VERSION 5.8 ;
BUSBITCHARS "[]" ;
DIVIDERCHAR "/" ;
UNITS
    DATABASE MICRONS 1000 ;
END UNITS

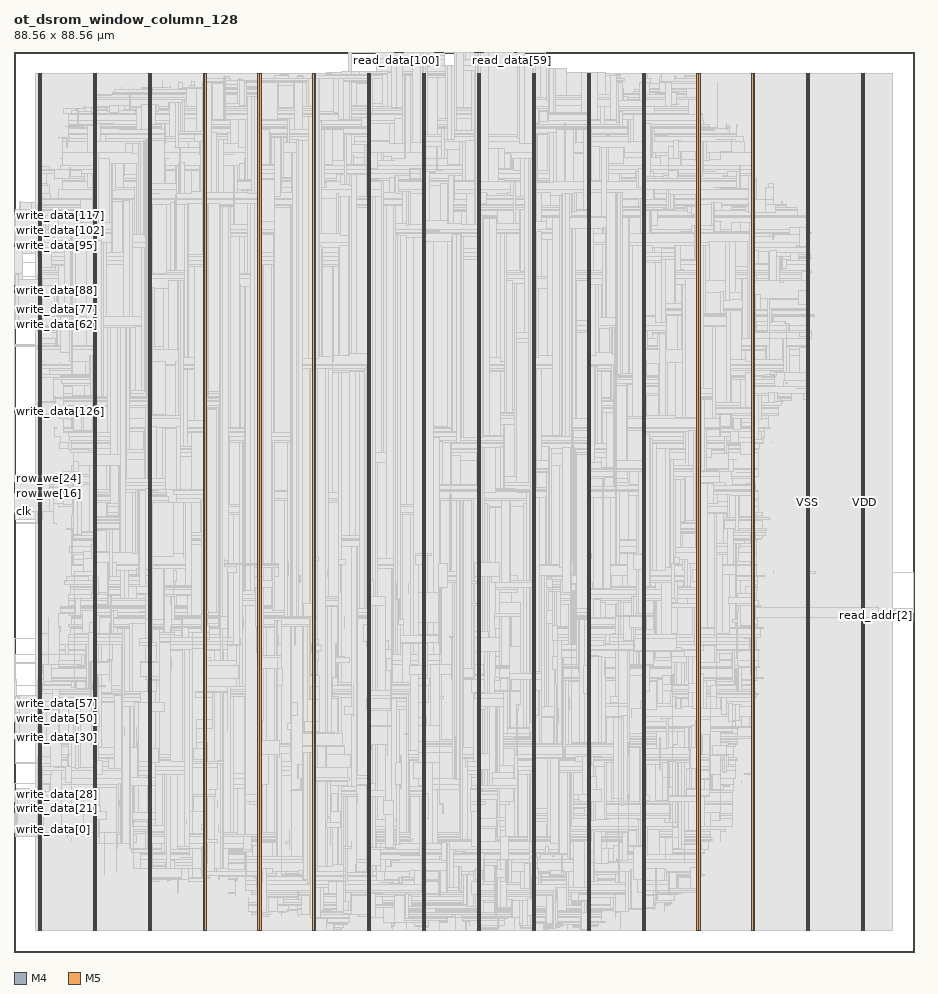
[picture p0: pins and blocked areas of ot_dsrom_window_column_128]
MACRO ot_dsrom_window_column_128
  FOREIGN ot_dsrom_window_column_128 0 0 ;
  CLASS BLOCK ;
  SIZE 88.56 BY 88.56 ;
  PIN clk
    DIRECTION INPUT ;
    USE SIGNAL ;
    PORT
      LAYER M4 ;
        RECT  0 43.344 0.084 43.368 ;
    END
  END clk
  PIN read_addr[0]
    DIRECTION INPUT ;
    USE SIGNAL ;
    PORT
      LAYER M4 ;
        RECT  88.476 32.88 88.56 32.904 ;
    END
  END read_addr[0]
  PIN read_addr[1]
    DIRECTION INPUT ;
    USE SIGNAL ;
    PORT
      LAYER M4 ;
        RECT  88.476 32.976 88.56 33 ;
    END
  END read_addr[1]
  PIN read_addr[2]
    DIRECTION INPUT ;
    USE SIGNAL ;
    PORT
      LAYER M4 ;
        RECT  88.476 33.072 88.56 33.096 ;
    END
  END read_addr[2]
  PIN read_addr[3]
    DIRECTION INPUT ;
    USE SIGNAL ;
    PORT
      LAYER M4 ;
        RECT  88.476 33.168 88.56 33.192 ;
    END
  END read_addr[3]
  PIN read_addr[4]
    DIRECTION INPUT ;
    USE SIGNAL ;
    PORT
      LAYER M4 ;
        RECT  88.476 33.264 88.56 33.288 ;
    END
  END read_addr[4]
  PIN read_data[0]
    DIRECTION OUTPUT ;
    USE SIGNAL ;
    PORT
      LAYER M5 ;
        RECT  43.344 88.476 43.368 88.56 ;
    END
  END read_data[0]
  PIN read_data[100]
    DIRECTION OUTPUT ;
    USE SIGNAL ;
    PORT
      LAYER M5 ;
        RECT  37.584 88.476 37.608 88.56 ;
    END
  END read_data[100]
  PIN read_data[101]
    DIRECTION OUTPUT ;
    USE SIGNAL ;
    PORT
      LAYER M5 ;
        RECT  37.68 88.476 37.704 88.56 ;
    END
  END read_data[101]
  PIN read_data[102]
    DIRECTION OUTPUT ;
    USE SIGNAL ;
    PORT
      LAYER M5 ;
        RECT  37.776 88.476 37.8 88.56 ;
    END
  END read_data[102]
  PIN read_data[103]
    DIRECTION OUTPUT ;
    USE SIGNAL ;
    PORT
      LAYER M5 ;
        RECT  37.872 88.476 37.896 88.56 ;
    END
  END read_data[103]
  PIN read_data[104]
    DIRECTION OUTPUT ;
    USE SIGNAL ;
    PORT
      LAYER M5 ;
        RECT  37.968 88.476 37.992 88.56 ;
    END
  END read_data[104]
  PIN read_data[105]
    DIRECTION OUTPUT ;
    USE SIGNAL ;
    PORT
      LAYER M5 ;
        RECT  38.064 88.476 38.088 88.56 ;
    END
  END read_data[105]
  PIN read_data[106]
    DIRECTION OUTPUT ;
    USE SIGNAL ;
    PORT
      LAYER M5 ;
        RECT  38.16 88.476 38.184 88.56 ;
    END
  END read_data[106]
  PIN read_data[107]
    DIRECTION OUTPUT ;
    USE SIGNAL ;
    PORT
      LAYER M5 ;
        RECT  38.256 88.476 38.28 88.56 ;
    END
  END read_data[107]
  PIN read_data[108]
    DIRECTION OUTPUT ;
    USE SIGNAL ;
    PORT
      LAYER M5 ;
        RECT  38.352 88.476 38.376 88.56 ;
    END
  END read_data[108]
  PIN read_data[109]
    DIRECTION OUTPUT ;
    USE SIGNAL ;
    PORT
      LAYER M5 ;
        RECT  38.448 88.476 38.472 88.56 ;
    END
  END read_data[109]
  PIN read_data[10]
    DIRECTION OUTPUT ;
    USE SIGNAL ;
    PORT
      LAYER M5 ;
        RECT  44.304 88.476 44.328 88.56 ;
    END
  END read_data[10]
  PIN read_data[110]
    DIRECTION OUTPUT ;
    USE SIGNAL ;
    PORT
      LAYER M5 ;
        RECT  38.544 88.476 38.568 88.56 ;
    END
  END read_data[110]
  PIN read_data[111]
    DIRECTION OUTPUT ;
    USE SIGNAL ;
    PORT
      LAYER M5 ;
        RECT  38.64 88.476 38.664 88.56 ;
    END
  END read_data[111]
  PIN read_data[112]
    DIRECTION OUTPUT ;
    USE SIGNAL ;
    PORT
      LAYER M5 ;
        RECT  38.736 88.476 38.76 88.56 ;
    END
  END read_data[112]
  PIN read_data[113]
    DIRECTION OUTPUT ;
    USE SIGNAL ;
    PORT
      LAYER M5 ;
        RECT  38.832 88.476 38.856 88.56 ;
    END
  END read_data[113]
  PIN read_data[114]
    DIRECTION OUTPUT ;
    USE SIGNAL ;
    PORT
      LAYER M5 ;
        RECT  38.928 88.476 38.952 88.56 ;
    END
  END read_data[114]
  PIN read_data[115]
    DIRECTION OUTPUT ;
    USE SIGNAL ;
    PORT
      LAYER M5 ;
        RECT  39.024 88.476 39.048 88.56 ;
    END
  END read_data[115]
  PIN read_data[116]
    DIRECTION OUTPUT ;
    USE SIGNAL ;
    PORT
      LAYER M5 ;
        RECT  39.12 88.476 39.144 88.56 ;
    END
  END read_data[116]
  PIN read_data[117]
    DIRECTION OUTPUT ;
    USE SIGNAL ;
    PORT
      LAYER M5 ;
        RECT  39.216 88.476 39.24 88.56 ;
    END
  END read_data[117]
  PIN read_data[118]
    DIRECTION OUTPUT ;
    USE SIGNAL ;
    PORT
      LAYER M5 ;
        RECT  39.312 88.476 39.336 88.56 ;
    END
  END read_data[118]
  PIN read_data[119]
    DIRECTION OUTPUT ;
    USE SIGNAL ;
    PORT
      LAYER M5 ;
        RECT  39.408 88.476 39.432 88.56 ;
    END
  END read_data[119]
  PIN read_data[11]
    DIRECTION OUTPUT ;
    USE SIGNAL ;
    PORT
      LAYER M5 ;
        RECT  44.4 88.476 44.424 88.56 ;
    END
  END read_data[11]
  PIN read_data[120]
    DIRECTION OUTPUT ;
    USE SIGNAL ;
    PORT
      LAYER M5 ;
        RECT  39.504 88.476 39.528 88.56 ;
    END
  END read_data[120]
  PIN read_data[121]
    DIRECTION OUTPUT ;
    USE SIGNAL ;
    PORT
      LAYER M5 ;
        RECT  39.6 88.476 39.624 88.56 ;
    END
  END read_data[121]
  PIN read_data[122]
    DIRECTION OUTPUT ;
    USE SIGNAL ;
    PORT
      LAYER M5 ;
        RECT  39.696 88.476 39.72 88.56 ;
    END
  END read_data[122]
  PIN read_data[123]
    DIRECTION OUTPUT ;
    USE SIGNAL ;
    PORT
      LAYER M5 ;
        RECT  39.792 88.476 39.816 88.56 ;
    END
  END read_data[123]
  PIN read_data[124]
    DIRECTION OUTPUT ;
    USE SIGNAL ;
    PORT
      LAYER M5 ;
        RECT  39.888 88.476 39.912 88.56 ;
    END
  END read_data[124]
  PIN read_data[125]
    DIRECTION OUTPUT ;
    USE SIGNAL ;
    PORT
      LAYER M5 ;
        RECT  39.984 88.476 40.008 88.56 ;
    END
  END read_data[125]
  PIN read_data[126]
    DIRECTION OUTPUT ;
    USE SIGNAL ;
    PORT
      LAYER M5 ;
        RECT  40.08 88.476 40.104 88.56 ;
    END
  END read_data[126]
  PIN read_data[127]
    DIRECTION OUTPUT ;
    USE SIGNAL ;
    PORT
      LAYER M5 ;
        RECT  40.176 88.476 40.2 88.56 ;
    END
  END read_data[127]
  PIN read_data[12]
    DIRECTION OUTPUT ;
    USE SIGNAL ;
    PORT
      LAYER M5 ;
        RECT  44.496 88.476 44.52 88.56 ;
    END
  END read_data[12]
  PIN read_data[13]
    DIRECTION OUTPUT ;
    USE SIGNAL ;
    PORT
      LAYER M5 ;
        RECT  44.592 88.476 44.616 88.56 ;
    END
  END read_data[13]
  PIN read_data[14]
    DIRECTION OUTPUT ;
    USE SIGNAL ;
    PORT
      LAYER M5 ;
        RECT  44.688 88.476 44.712 88.56 ;
    END
  END read_data[14]
  PIN read_data[15]
    DIRECTION OUTPUT ;
    USE SIGNAL ;
    PORT
      LAYER M5 ;
        RECT  44.784 88.476 44.808 88.56 ;
    END
  END read_data[15]
  PIN read_data[16]
    DIRECTION OUTPUT ;
    USE SIGNAL ;
    PORT
      LAYER M5 ;
        RECT  44.88 88.476 44.904 88.56 ;
    END
  END read_data[16]
  PIN read_data[17]
    DIRECTION OUTPUT ;
    USE SIGNAL ;
    PORT
      LAYER M5 ;
        RECT  44.976 88.476 45 88.56 ;
    END
  END read_data[17]
  PIN read_data[18]
    DIRECTION OUTPUT ;
    USE SIGNAL ;
    PORT
      LAYER M5 ;
        RECT  45.072 88.476 45.096 88.56 ;
    END
  END read_data[18]
  PIN read_data[19]
    DIRECTION OUTPUT ;
    USE SIGNAL ;
    PORT
      LAYER M5 ;
        RECT  45.168 88.476 45.192 88.56 ;
    END
  END read_data[19]
  PIN read_data[1]
    DIRECTION OUTPUT ;
    USE SIGNAL ;
    PORT
      LAYER M5 ;
        RECT  43.44 88.476 43.464 88.56 ;
    END
  END read_data[1]
  PIN read_data[20]
    DIRECTION OUTPUT ;
    USE SIGNAL ;
    PORT
      LAYER M5 ;
        RECT  45.264 88.476 45.288 88.56 ;
    END
  END read_data[20]
  PIN read_data[21]
    DIRECTION OUTPUT ;
    USE SIGNAL ;
    PORT
      LAYER M5 ;
        RECT  45.36 88.476 45.384 88.56 ;
    END
  END read_data[21]
  PIN read_data[22]
    DIRECTION OUTPUT ;
    USE SIGNAL ;
    PORT
      LAYER M5 ;
        RECT  45.456 88.476 45.48 88.56 ;
    END
  END read_data[22]
  PIN read_data[23]
    DIRECTION OUTPUT ;
    USE SIGNAL ;
    PORT
      LAYER M5 ;
        RECT  45.552 88.476 45.576 88.56 ;
    END
  END read_data[23]
  PIN read_data[24]
    DIRECTION OUTPUT ;
    USE SIGNAL ;
    PORT
      LAYER M5 ;
        RECT  45.648 88.476 45.672 88.56 ;
    END
  END read_data[24]
  PIN read_data[25]
    DIRECTION OUTPUT ;
    USE SIGNAL ;
    PORT
      LAYER M5 ;
        RECT  45.744 88.476 45.768 88.56 ;
    END
  END read_data[25]
  PIN read_data[26]
    DIRECTION OUTPUT ;
    USE SIGNAL ;
    PORT
      LAYER M5 ;
        RECT  45.84 88.476 45.864 88.56 ;
    END
  END read_data[26]
  PIN read_data[27]
    DIRECTION OUTPUT ;
    USE SIGNAL ;
    PORT
      LAYER M5 ;
        RECT  45.936 88.476 45.96 88.56 ;
    END
  END read_data[27]
  PIN read_data[28]
    DIRECTION OUTPUT ;
    USE SIGNAL ;
    PORT
      LAYER M5 ;
        RECT  46.032 88.476 46.056 88.56 ;
    END
  END read_data[28]
  PIN read_data[29]
    DIRECTION OUTPUT ;
    USE SIGNAL ;
    PORT
      LAYER M5 ;
        RECT  46.128 88.476 46.152 88.56 ;
    END
  END read_data[29]
  PIN read_data[2]
    DIRECTION OUTPUT ;
    USE SIGNAL ;
    PORT
      LAYER M5 ;
        RECT  43.536 88.476 43.56 88.56 ;
    END
  END read_data[2]
  PIN read_data[30]
    DIRECTION OUTPUT ;
    USE SIGNAL ;
    PORT
      LAYER M5 ;
        RECT  46.224 88.476 46.248 88.56 ;
    END
  END read_data[30]
  PIN read_data[31]
    DIRECTION OUTPUT ;
    USE SIGNAL ;
    PORT
      LAYER M5 ;
        RECT  46.32 88.476 46.344 88.56 ;
    END
  END read_data[31]
  PIN read_data[32]
    DIRECTION OUTPUT ;
    USE SIGNAL ;
    PORT
      LAYER M5 ;
        RECT  46.416 88.476 46.44 88.56 ;
    END
  END read_data[32]
  PIN read_data[33]
    DIRECTION OUTPUT ;
    USE SIGNAL ;
    PORT
      LAYER M5 ;
        RECT  46.512 88.476 46.536 88.56 ;
    END
  END read_data[33]
  PIN read_data[34]
    DIRECTION OUTPUT ;
    USE SIGNAL ;
    PORT
      LAYER M5 ;
        RECT  46.608 88.476 46.632 88.56 ;
    END
  END read_data[34]
  PIN read_data[35]
    DIRECTION OUTPUT ;
    USE SIGNAL ;
    PORT
      LAYER M5 ;
        RECT  46.704 88.476 46.728 88.56 ;
    END
  END read_data[35]
  PIN read_data[36]
    DIRECTION OUTPUT ;
    USE SIGNAL ;
    PORT
      LAYER M5 ;
        RECT  46.8 88.476 46.824 88.56 ;
    END
  END read_data[36]
  PIN read_data[37]
    DIRECTION OUTPUT ;
    USE SIGNAL ;
    PORT
      LAYER M5 ;
        RECT  46.896 88.476 46.92 88.56 ;
    END
  END read_data[37]
  PIN read_data[38]
    DIRECTION OUTPUT ;
    USE SIGNAL ;
    PORT
      LAYER M5 ;
        RECT  46.992 88.476 47.016 88.56 ;
    END
  END read_data[38]
  PIN read_data[39]
    DIRECTION OUTPUT ;
    USE SIGNAL ;
    PORT
      LAYER M5 ;
        RECT  47.088 88.476 47.112 88.56 ;
    END
  END read_data[39]
  PIN read_data[3]
    DIRECTION OUTPUT ;
    USE SIGNAL ;
    PORT
      LAYER M5 ;
        RECT  43.632 88.476 43.656 88.56 ;
    END
  END read_data[3]
  PIN read_data[40]
    DIRECTION OUTPUT ;
    USE SIGNAL ;
    PORT
      LAYER M5 ;
        RECT  47.184 88.476 47.208 88.56 ;
    END
  END read_data[40]
  PIN read_data[41]
    DIRECTION OUTPUT ;
    USE SIGNAL ;
    PORT
      LAYER M5 ;
        RECT  47.28 88.476 47.304 88.56 ;
    END
  END read_data[41]
  PIN read_data[42]
    DIRECTION OUTPUT ;
    USE SIGNAL ;
    PORT
      LAYER M5 ;
        RECT  47.376 88.476 47.4 88.56 ;
    END
  END read_data[42]
  PIN read_data[43]
    DIRECTION OUTPUT ;
    USE SIGNAL ;
    PORT
      LAYER M5 ;
        RECT  47.472 88.476 47.496 88.56 ;
    END
  END read_data[43]
  PIN read_data[44]
    DIRECTION OUTPUT ;
    USE SIGNAL ;
    PORT
      LAYER M5 ;
        RECT  47.568 88.476 47.592 88.56 ;
    END
  END read_data[44]
  PIN read_data[45]
    DIRECTION OUTPUT ;
    USE SIGNAL ;
    PORT
      LAYER M5 ;
        RECT  47.664 88.476 47.688 88.56 ;
    END
  END read_data[45]
  PIN read_data[46]
    DIRECTION OUTPUT ;
    USE SIGNAL ;
    PORT
      LAYER M5 ;
        RECT  47.76 88.476 47.784 88.56 ;
    END
  END read_data[46]
  PIN read_data[47]
    DIRECTION OUTPUT ;
    USE SIGNAL ;
    PORT
      LAYER M5 ;
        RECT  47.856 88.476 47.88 88.56 ;
    END
  END read_data[47]
  PIN read_data[48]
    DIRECTION OUTPUT ;
    USE SIGNAL ;
    PORT
      LAYER M5 ;
        RECT  47.952 88.476 47.976 88.56 ;
    END
  END read_data[48]
  PIN read_data[49]
    DIRECTION OUTPUT ;
    USE SIGNAL ;
    PORT
      LAYER M5 ;
        RECT  48.048 88.476 48.072 88.56 ;
    END
  END read_data[49]
  PIN read_data[4]
    DIRECTION OUTPUT ;
    USE SIGNAL ;
    PORT
      LAYER M5 ;
        RECT  43.728 88.476 43.752 88.56 ;
    END
  END read_data[4]
  PIN read_data[50]
    DIRECTION OUTPUT ;
    USE SIGNAL ;
    PORT
      LAYER M5 ;
        RECT  48.144 88.476 48.168 88.56 ;
    END
  END read_data[50]
  PIN read_data[51]
    DIRECTION OUTPUT ;
    USE SIGNAL ;
    PORT
      LAYER M5 ;
        RECT  48.24 88.476 48.264 88.56 ;
    END
  END read_data[51]
  PIN read_data[52]
    DIRECTION OUTPUT ;
    USE SIGNAL ;
    PORT
      LAYER M5 ;
        RECT  48.336 88.476 48.36 88.56 ;
    END
  END read_data[52]
  PIN read_data[53]
    DIRECTION OUTPUT ;
    USE SIGNAL ;
    PORT
      LAYER M5 ;
        RECT  48.432 88.476 48.456 88.56 ;
    END
  END read_data[53]
  PIN read_data[54]
    DIRECTION OUTPUT ;
    USE SIGNAL ;
    PORT
      LAYER M5 ;
        RECT  48.528 88.476 48.552 88.56 ;
    END
  END read_data[54]
  PIN read_data[55]
    DIRECTION OUTPUT ;
    USE SIGNAL ;
    PORT
      LAYER M5 ;
        RECT  48.624 88.476 48.648 88.56 ;
    END
  END read_data[55]
  PIN read_data[56]
    DIRECTION OUTPUT ;
    USE SIGNAL ;
    PORT
      LAYER M5 ;
        RECT  48.72 88.476 48.744 88.56 ;
    END
  END read_data[56]
  PIN read_data[57]
    DIRECTION OUTPUT ;
    USE SIGNAL ;
    PORT
      LAYER M5 ;
        RECT  48.816 88.476 48.84 88.56 ;
    END
  END read_data[57]
  PIN read_data[58]
    DIRECTION OUTPUT ;
    USE SIGNAL ;
    PORT
      LAYER M5 ;
        RECT  48.912 88.476 48.936 88.56 ;
    END
  END read_data[58]
  PIN read_data[59]
    DIRECTION OUTPUT ;
    USE SIGNAL ;
    PORT
      LAYER M5 ;
        RECT  49.008 88.476 49.032 88.56 ;
    END
  END read_data[59]
  PIN read_data[5]
    DIRECTION OUTPUT ;
    USE SIGNAL ;
    PORT
      LAYER M5 ;
        RECT  43.824 88.476 43.848 88.56 ;
    END
  END read_data[5]
  PIN read_data[60]
    DIRECTION OUTPUT ;
    USE SIGNAL ;
    PORT
      LAYER M5 ;
        RECT  49.104 88.476 49.128 88.56 ;
    END
  END read_data[60]
  PIN read_data[61]
    DIRECTION OUTPUT ;
    USE SIGNAL ;
    PORT
      LAYER M5 ;
        RECT  49.2 88.476 49.224 88.56 ;
    END
  END read_data[61]
  PIN read_data[62]
    DIRECTION OUTPUT ;
    USE SIGNAL ;
    PORT
      LAYER M5 ;
        RECT  49.296 88.476 49.32 88.56 ;
    END
  END read_data[62]
  PIN read_data[63]
    DIRECTION OUTPUT ;
    USE SIGNAL ;
    PORT
      LAYER M5 ;
        RECT  49.392 88.476 49.416 88.56 ;
    END
  END read_data[63]
  PIN read_data[64]
    DIRECTION OUTPUT ;
    USE SIGNAL ;
    PORT
      LAYER M5 ;
        RECT  40.272 88.476 40.296 88.56 ;
    END
  END read_data[64]
  PIN read_data[65]
    DIRECTION OUTPUT ;
    USE SIGNAL ;
    PORT
      LAYER M5 ;
        RECT  40.368 88.476 40.392 88.56 ;
    END
  END read_data[65]
  PIN read_data[66]
    DIRECTION OUTPUT ;
    USE SIGNAL ;
    PORT
      LAYER M5 ;
        RECT  40.464 88.476 40.488 88.56 ;
    END
  END read_data[66]
  PIN read_data[67]
    DIRECTION OUTPUT ;
    USE SIGNAL ;
    PORT
      LAYER M5 ;
        RECT  40.56 88.476 40.584 88.56 ;
    END
  END read_data[67]
  PIN read_data[68]
    DIRECTION OUTPUT ;
    USE SIGNAL ;
    PORT
      LAYER M5 ;
        RECT  40.656 88.476 40.68 88.56 ;
    END
  END read_data[68]
  PIN read_data[69]
    DIRECTION OUTPUT ;
    USE SIGNAL ;
    PORT
      LAYER M5 ;
        RECT  40.752 88.476 40.776 88.56 ;
    END
  END read_data[69]
  PIN read_data[6]
    DIRECTION OUTPUT ;
    USE SIGNAL ;
    PORT
      LAYER M5 ;
        RECT  43.92 88.476 43.944 88.56 ;
    END
  END read_data[6]
  PIN read_data[70]
    DIRECTION OUTPUT ;
    USE SIGNAL ;
    PORT
      LAYER M5 ;
        RECT  40.848 88.476 40.872 88.56 ;
    END
  END read_data[70]
  PIN read_data[71]
    DIRECTION OUTPUT ;
    USE SIGNAL ;
    PORT
      LAYER M5 ;
        RECT  40.944 88.476 40.968 88.56 ;
    END
  END read_data[71]
  PIN read_data[72]
    DIRECTION OUTPUT ;
    USE SIGNAL ;
    PORT
      LAYER M5 ;
        RECT  41.04 88.476 41.064 88.56 ;
    END
  END read_data[72]
  PIN read_data[73]
    DIRECTION OUTPUT ;
    USE SIGNAL ;
    PORT
      LAYER M5 ;
        RECT  41.136 88.476 41.16 88.56 ;
    END
  END read_data[73]
  PIN read_data[74]
    DIRECTION OUTPUT ;
    USE SIGNAL ;
    PORT
      LAYER M5 ;
        RECT  41.232 88.476 41.256 88.56 ;
    END
  END read_data[74]
  PIN read_data[75]
    DIRECTION OUTPUT ;
    USE SIGNAL ;
    PORT
      LAYER M5 ;
        RECT  41.328 88.476 41.352 88.56 ;
    END
  END read_data[75]
  PIN read_data[76]
    DIRECTION OUTPUT ;
    USE SIGNAL ;
    PORT
      LAYER M5 ;
        RECT  41.424 88.476 41.448 88.56 ;
    END
  END read_data[76]
  PIN read_data[77]
    DIRECTION OUTPUT ;
    USE SIGNAL ;
    PORT
      LAYER M5 ;
        RECT  41.52 88.476 41.544 88.56 ;
    END
  END read_data[77]
  PIN read_data[78]
    DIRECTION OUTPUT ;
    USE SIGNAL ;
    PORT
      LAYER M5 ;
        RECT  41.616 88.476 41.64 88.56 ;
    END
  END read_data[78]
  PIN read_data[79]
    DIRECTION OUTPUT ;
    USE SIGNAL ;
    PORT
      LAYER M5 ;
        RECT  41.712 88.476 41.736 88.56 ;
    END
  END read_data[79]
  PIN read_data[7]
    DIRECTION OUTPUT ;
    USE SIGNAL ;
    PORT
      LAYER M5 ;
        RECT  44.016 88.476 44.04 88.56 ;
    END
  END read_data[7]
  PIN read_data[80]
    DIRECTION OUTPUT ;
    USE SIGNAL ;
    PORT
      LAYER M5 ;
        RECT  41.808 88.476 41.832 88.56 ;
    END
  END read_data[80]
  PIN read_data[81]
    DIRECTION OUTPUT ;
    USE SIGNAL ;
    PORT
      LAYER M5 ;
        RECT  41.904 88.476 41.928 88.56 ;
    END
  END read_data[81]
  PIN read_data[82]
    DIRECTION OUTPUT ;
    USE SIGNAL ;
    PORT
      LAYER M5 ;
        RECT  42 88.476 42.024 88.56 ;
    END
  END read_data[82]
  PIN read_data[83]
    DIRECTION OUTPUT ;
    USE SIGNAL ;
    PORT
      LAYER M5 ;
        RECT  42.096 88.476 42.12 88.56 ;
    END
  END read_data[83]
  PIN read_data[84]
    DIRECTION OUTPUT ;
    USE SIGNAL ;
    PORT
      LAYER M5 ;
        RECT  42.192 88.476 42.216 88.56 ;
    END
  END read_data[84]
  PIN read_data[85]
    DIRECTION OUTPUT ;
    USE SIGNAL ;
    PORT
      LAYER M5 ;
        RECT  42.288 88.476 42.312 88.56 ;
    END
  END read_data[85]
  PIN read_data[86]
    DIRECTION OUTPUT ;
    USE SIGNAL ;
    PORT
      LAYER M5 ;
        RECT  42.384 88.476 42.408 88.56 ;
    END
  END read_data[86]
  PIN read_data[87]
    DIRECTION OUTPUT ;
    USE SIGNAL ;
    PORT
      LAYER M5 ;
        RECT  42.48 88.476 42.504 88.56 ;
    END
  END read_data[87]
  PIN read_data[88]
    DIRECTION OUTPUT ;
    USE SIGNAL ;
    PORT
      LAYER M5 ;
        RECT  42.576 88.476 42.6 88.56 ;
    END
  END read_data[88]
  PIN read_data[89]
    DIRECTION OUTPUT ;
    USE SIGNAL ;
    PORT
      LAYER M5 ;
        RECT  42.672 88.476 42.696 88.56 ;
    END
  END read_data[89]
  PIN read_data[8]
    DIRECTION OUTPUT ;
    USE SIGNAL ;
    PORT
      LAYER M5 ;
        RECT  44.112 88.476 44.136 88.56 ;
    END
  END read_data[8]
  PIN read_data[90]
    DIRECTION OUTPUT ;
    USE SIGNAL ;
    PORT
      LAYER M5 ;
        RECT  42.768 88.476 42.792 88.56 ;
    END
  END read_data[90]
  PIN read_data[91]
    DIRECTION OUTPUT ;
    USE SIGNAL ;
    PORT
      LAYER M5 ;
        RECT  42.864 88.476 42.888 88.56 ;
    END
  END read_data[91]
  PIN read_data[92]
    DIRECTION OUTPUT ;
    USE SIGNAL ;
    PORT
      LAYER M5 ;
        RECT  42.96 88.476 42.984 88.56 ;
    END
  END read_data[92]
  PIN read_data[93]
    DIRECTION OUTPUT ;
    USE SIGNAL ;
    PORT
      LAYER M5 ;
        RECT  43.056 88.476 43.08 88.56 ;
    END
  END read_data[93]
  PIN read_data[94]
    DIRECTION OUTPUT ;
    USE SIGNAL ;
    PORT
      LAYER M5 ;
        RECT  43.152 88.476 43.176 88.56 ;
    END
  END read_data[94]
  PIN read_data[95]
    DIRECTION OUTPUT ;
    USE SIGNAL ;
    PORT
      LAYER M5 ;
        RECT  43.248 88.476 43.272 88.56 ;
    END
  END read_data[95]
  PIN read_data[96]
    DIRECTION OUTPUT ;
    USE SIGNAL ;
    PORT
      LAYER M5 ;
        RECT  37.2 88.476 37.224 88.56 ;
    END
  END read_data[96]
  PIN read_data[97]
    DIRECTION OUTPUT ;
    USE SIGNAL ;
    PORT
      LAYER M5 ;
        RECT  37.296 88.476 37.32 88.56 ;
    END
  END read_data[97]
  PIN read_data[98]
    DIRECTION OUTPUT ;
    USE SIGNAL ;
    PORT
      LAYER M5 ;
        RECT  37.392 88.476 37.416 88.56 ;
    END
  END read_data[98]
  PIN read_data[99]
    DIRECTION OUTPUT ;
    USE SIGNAL ;
    PORT
      LAYER M5 ;
        RECT  37.488 88.476 37.512 88.56 ;
    END
  END read_data[99]
  PIN read_data[9]
    DIRECTION OUTPUT ;
    USE SIGNAL ;
    PORT
      LAYER M5 ;
        RECT  44.208 88.476 44.232 88.56 ;
    END
  END read_data[9]
  PIN read_v
    DIRECTION INPUT ;
    USE SIGNAL ;
    PORT
      LAYER M4 ;
        RECT  0 43.44 0.084 43.464 ;
    END
  END read_v
  PIN row_we[0]
    DIRECTION INPUT ;
    USE SIGNAL ;
    PORT
      LAYER M4 ;
        RECT  0 43.536 0.084 43.56 ;
    END
  END row_we[0]
  PIN row_we[10]
    DIRECTION INPUT ;
    USE SIGNAL ;
    PORT
      LAYER M4 ;
        RECT  0 44.496 0.084 44.52 ;
    END
  END row_we[10]
  PIN row_we[11]
    DIRECTION INPUT ;
    USE SIGNAL ;
    PORT
      LAYER M4 ;
        RECT  0 44.592 0.084 44.616 ;
    END
  END row_we[11]
  PIN row_we[12]
    DIRECTION INPUT ;
    USE SIGNAL ;
    PORT
      LAYER M4 ;
        RECT  0 44.688 0.084 44.712 ;
    END
  END row_we[12]
  PIN row_we[13]
    DIRECTION INPUT ;
    USE SIGNAL ;
    PORT
      LAYER M4 ;
        RECT  0 44.784 0.084 44.808 ;
    END
  END row_we[13]
  PIN row_we[14]
    DIRECTION INPUT ;
    USE SIGNAL ;
    PORT
      LAYER M4 ;
        RECT  0 44.88 0.084 44.904 ;
    END
  END row_we[14]
  PIN row_we[15]
    DIRECTION INPUT ;
    USE SIGNAL ;
    PORT
      LAYER M4 ;
        RECT  0 44.976 0.084 45 ;
    END
  END row_we[15]
  PIN row_we[16]
    DIRECTION INPUT ;
    USE SIGNAL ;
    PORT
      LAYER M4 ;
        RECT  0 45.072 0.084 45.096 ;
    END
  END row_we[16]
  PIN row_we[17]
    DIRECTION INPUT ;
    USE SIGNAL ;
    PORT
      LAYER M4 ;
        RECT  0 45.168 0.084 45.192 ;
    END
  END row_we[17]
  PIN row_we[18]
    DIRECTION INPUT ;
    USE SIGNAL ;
    PORT
      LAYER M4 ;
        RECT  0 45.264 0.084 45.288 ;
    END
  END row_we[18]
  PIN row_we[19]
    DIRECTION INPUT ;
    USE SIGNAL ;
    PORT
      LAYER M4 ;
        RECT  0 45.36 0.084 45.384 ;
    END
  END row_we[19]
  PIN row_we[1]
    DIRECTION INPUT ;
    USE SIGNAL ;
    PORT
      LAYER M4 ;
        RECT  0 43.632 0.084 43.656 ;
    END
  END row_we[1]
  PIN row_we[20]
    DIRECTION INPUT ;
    USE SIGNAL ;
    PORT
      LAYER M4 ;
        RECT  0 45.456 0.084 45.48 ;
    END
  END row_we[20]
  PIN row_we[21]
    DIRECTION INPUT ;
    USE SIGNAL ;
    PORT
      LAYER M4 ;
        RECT  0 45.552 0.084 45.576 ;
    END
  END row_we[21]
  PIN row_we[22]
    DIRECTION INPUT ;
    USE SIGNAL ;
    PORT
      LAYER M4 ;
        RECT  0 45.648 0.084 45.672 ;
    END
  END row_we[22]
  PIN row_we[23]
    DIRECTION INPUT ;
    USE SIGNAL ;
    PORT
      LAYER M4 ;
        RECT  0 45.744 0.084 45.768 ;
    END
  END row_we[23]
  PIN row_we[24]
    DIRECTION INPUT ;
    USE SIGNAL ;
    PORT
      LAYER M4 ;
        RECT  0 45.84 0.084 45.864 ;
    END
  END row_we[24]
  PIN row_we[25]
    DIRECTION INPUT ;
    USE SIGNAL ;
    PORT
      LAYER M4 ;
        RECT  0 45.936 0.084 45.96 ;
    END
  END row_we[25]
  PIN row_we[26]
    DIRECTION INPUT ;
    USE SIGNAL ;
    PORT
      LAYER M4 ;
        RECT  0 46.032 0.084 46.056 ;
    END
  END row_we[26]
  PIN row_we[27]
    DIRECTION INPUT ;
    USE SIGNAL ;
    PORT
      LAYER M4 ;
        RECT  0 46.128 0.084 46.152 ;
    END
  END row_we[27]
  PIN row_we[28]
    DIRECTION INPUT ;
    USE SIGNAL ;
    PORT
      LAYER M4 ;
        RECT  0 46.224 0.084 46.248 ;
    END
  END row_we[28]
  PIN row_we[29]
    DIRECTION INPUT ;
    USE SIGNAL ;
    PORT
      LAYER M4 ;
        RECT  0 46.32 0.084 46.344 ;
    END
  END row_we[29]
  PIN row_we[2]
    DIRECTION INPUT ;
    USE SIGNAL ;
    PORT
      LAYER M4 ;
        RECT  0 43.728 0.084 43.752 ;
    END
  END row_we[2]
  PIN row_we[30]
    DIRECTION INPUT ;
    USE SIGNAL ;
    PORT
      LAYER M4 ;
        RECT  0 11.856 0.084 11.88 ;
    END
  END row_we[30]
  PIN row_we[31]
    DIRECTION INPUT ;
    USE SIGNAL ;
    PORT
      LAYER M4 ;
        RECT  0 11.952 0.084 11.976 ;
    END
  END row_we[31]
  PIN row_we[3]
    DIRECTION INPUT ;
    USE SIGNAL ;
    PORT
      LAYER M4 ;
        RECT  0 43.824 0.084 43.848 ;
    END
  END row_we[3]
  PIN row_we[4]
    DIRECTION INPUT ;
    USE SIGNAL ;
    PORT
      LAYER M4 ;
        RECT  0 43.92 0.084 43.944 ;
    END
  END row_we[4]
  PIN row_we[5]
    DIRECTION INPUT ;
    USE SIGNAL ;
    PORT
      LAYER M4 ;
        RECT  0 44.016 0.084 44.04 ;
    END
  END row_we[5]
  PIN row_we[6]
    DIRECTION INPUT ;
    USE SIGNAL ;
    PORT
      LAYER M4 ;
        RECT  0 44.112 0.084 44.136 ;
    END
  END row_we[6]
  PIN row_we[7]
    DIRECTION INPUT ;
    USE SIGNAL ;
    PORT
      LAYER M4 ;
        RECT  0 44.208 0.084 44.232 ;
    END
  END row_we[7]
  PIN row_we[8]
    DIRECTION INPUT ;
    USE SIGNAL ;
    PORT
      LAYER M4 ;
        RECT  0 44.304 0.084 44.328 ;
    END
  END row_we[8]
  PIN row_we[9]
    DIRECTION INPUT ;
    USE SIGNAL ;
    PORT
      LAYER M4 ;
        RECT  0 44.4 0.084 44.424 ;
    END
  END row_we[9]
  PIN rst_n
    DIRECTION INPUT ;
    USE SIGNAL ;
    PORT
      LAYER M5 ;
        RECT  37.104 88.476 37.128 88.56 ;
    END
  END rst_n
  PIN write_data[0]
    DIRECTION INPUT ;
    USE SIGNAL ;
    PORT
      LAYER M4 ;
        RECT  0 12.048 0.084 12.072 ;
    END
  END write_data[0]
  PIN write_data[100]
    DIRECTION INPUT ;
    USE SIGNAL ;
    PORT
      LAYER M4 ;
        RECT  0 70.032 0.084 70.056 ;
    END
  END write_data[100]
  PIN write_data[101]
    DIRECTION INPUT ;
    USE SIGNAL ;
    PORT
      LAYER M4 ;
        RECT  0 70.128 0.084 70.152 ;
    END
  END write_data[101]
  PIN write_data[102]
    DIRECTION INPUT ;
    USE SIGNAL ;
    PORT
      LAYER M4 ;
        RECT  0 70.224 0.084 70.248 ;
    END
  END write_data[102]
  PIN write_data[103]
    DIRECTION INPUT ;
    USE SIGNAL ;
    PORT
      LAYER M4 ;
        RECT  0 70.32 0.084 70.344 ;
    END
  END write_data[103]
  PIN write_data[104]
    DIRECTION INPUT ;
    USE SIGNAL ;
    PORT
      LAYER M4 ;
        RECT  0 70.416 0.084 70.44 ;
    END
  END write_data[104]
  PIN write_data[105]
    DIRECTION INPUT ;
    USE SIGNAL ;
    PORT
      LAYER M4 ;
        RECT  0 70.512 0.084 70.536 ;
    END
  END write_data[105]
  PIN write_data[106]
    DIRECTION INPUT ;
    USE SIGNAL ;
    PORT
      LAYER M4 ;
        RECT  0 70.608 0.084 70.632 ;
    END
  END write_data[106]
  PIN write_data[107]
    DIRECTION INPUT ;
    USE SIGNAL ;
    PORT
      LAYER M4 ;
        RECT  0 70.704 0.084 70.728 ;
    END
  END write_data[107]
  PIN write_data[108]
    DIRECTION INPUT ;
    USE SIGNAL ;
    PORT
      LAYER M4 ;
        RECT  0 70.8 0.084 70.824 ;
    END
  END write_data[108]
  PIN write_data[109]
    DIRECTION INPUT ;
    USE SIGNAL ;
    PORT
      LAYER M4 ;
        RECT  0 70.896 0.084 70.92 ;
    END
  END write_data[109]
  PIN write_data[10]
    DIRECTION INPUT ;
    USE SIGNAL ;
    PORT
      LAYER M4 ;
        RECT  0 13.008 0.084 13.032 ;
    END
  END write_data[10]
  PIN write_data[110]
    DIRECTION INPUT ;
    USE SIGNAL ;
    PORT
      LAYER M4 ;
        RECT  0 70.992 0.084 71.016 ;
    END
  END write_data[110]
  PIN write_data[111]
    DIRECTION INPUT ;
    USE SIGNAL ;
    PORT
      LAYER M4 ;
        RECT  0 71.088 0.084 71.112 ;
    END
  END write_data[111]
  PIN write_data[112]
    DIRECTION INPUT ;
    USE SIGNAL ;
    PORT
      LAYER M4 ;
        RECT  0 71.184 0.084 71.208 ;
    END
  END write_data[112]
  PIN write_data[113]
    DIRECTION INPUT ;
    USE SIGNAL ;
    PORT
      LAYER M4 ;
        RECT  0 71.28 0.084 71.304 ;
    END
  END write_data[113]
  PIN write_data[114]
    DIRECTION INPUT ;
    USE SIGNAL ;
    PORT
      LAYER M4 ;
        RECT  0 71.376 0.084 71.4 ;
    END
  END write_data[114]
  PIN write_data[115]
    DIRECTION INPUT ;
    USE SIGNAL ;
    PORT
      LAYER M4 ;
        RECT  0 71.472 0.084 71.496 ;
    END
  END write_data[115]
  PIN write_data[116]
    DIRECTION INPUT ;
    USE SIGNAL ;
    PORT
      LAYER M4 ;
        RECT  0 71.568 0.084 71.592 ;
    END
  END write_data[116]
  PIN write_data[117]
    DIRECTION INPUT ;
    USE SIGNAL ;
    PORT
      LAYER M4 ;
        RECT  0 71.664 0.084 71.688 ;
    END
  END write_data[117]
  PIN write_data[118]
    DIRECTION INPUT ;
    USE SIGNAL ;
    PORT
      LAYER M4 ;
        RECT  0 71.76 0.084 71.784 ;
    END
  END write_data[118]
  PIN write_data[119]
    DIRECTION INPUT ;
    USE SIGNAL ;
    PORT
      LAYER M4 ;
        RECT  0 71.856 0.084 71.88 ;
    END
  END write_data[119]
  PIN write_data[11]
    DIRECTION INPUT ;
    USE SIGNAL ;
    PORT
      LAYER M4 ;
        RECT  0 13.104 0.084 13.128 ;
    END
  END write_data[11]
  PIN write_data[120]
    DIRECTION INPUT ;
    USE SIGNAL ;
    PORT
      LAYER M4 ;
        RECT  0 71.952 0.084 71.976 ;
    END
  END write_data[120]
  PIN write_data[121]
    DIRECTION INPUT ;
    USE SIGNAL ;
    PORT
      LAYER M4 ;
        RECT  0 72.048 0.084 72.072 ;
    END
  END write_data[121]
  PIN write_data[122]
    DIRECTION INPUT ;
    USE SIGNAL ;
    PORT
      LAYER M4 ;
        RECT  0 72.144 0.084 72.168 ;
    END
  END write_data[122]
  PIN write_data[123]
    DIRECTION INPUT ;
    USE SIGNAL ;
    PORT
      LAYER M4 ;
        RECT  0 72.24 0.084 72.264 ;
    END
  END write_data[123]
  PIN write_data[124]
    DIRECTION INPUT ;
    USE SIGNAL ;
    PORT
      LAYER M4 ;
        RECT  0 72.336 0.084 72.36 ;
    END
  END write_data[124]
  PIN write_data[125]
    DIRECTION INPUT ;
    USE SIGNAL ;
    PORT
      LAYER M4 ;
        RECT  0 72.432 0.084 72.456 ;
    END
  END write_data[125]
  PIN write_data[126]
    DIRECTION INPUT ;
    USE SIGNAL ;
    PORT
      LAYER M4 ;
        RECT  0 53.136 0.084 53.16 ;
    END
  END write_data[126]
  PIN write_data[127]
    DIRECTION INPUT ;
    USE SIGNAL ;
    PORT
      LAYER M4 ;
        RECT  0 53.232 0.084 53.256 ;
    END
  END write_data[127]
  PIN write_data[12]
    DIRECTION INPUT ;
    USE SIGNAL ;
    PORT
      LAYER M4 ;
        RECT  0 13.2 0.084 13.224 ;
    END
  END write_data[12]
  PIN write_data[13]
    DIRECTION INPUT ;
    USE SIGNAL ;
    PORT
      LAYER M4 ;
        RECT  0 13.296 0.084 13.32 ;
    END
  END write_data[13]
  PIN write_data[14]
    DIRECTION INPUT ;
    USE SIGNAL ;
    PORT
      LAYER M4 ;
        RECT  0 13.392 0.084 13.416 ;
    END
  END write_data[14]
  PIN write_data[15]
    DIRECTION INPUT ;
    USE SIGNAL ;
    PORT
      LAYER M4 ;
        RECT  0 13.488 0.084 13.512 ;
    END
  END write_data[15]
  PIN write_data[16]
    DIRECTION INPUT ;
    USE SIGNAL ;
    PORT
      LAYER M4 ;
        RECT  0 13.584 0.084 13.608 ;
    END
  END write_data[16]
  PIN write_data[17]
    DIRECTION INPUT ;
    USE SIGNAL ;
    PORT
      LAYER M4 ;
        RECT  0 13.68 0.084 13.704 ;
    END
  END write_data[17]
  PIN write_data[18]
    DIRECTION INPUT ;
    USE SIGNAL ;
    PORT
      LAYER M4 ;
        RECT  0 13.776 0.084 13.8 ;
    END
  END write_data[18]
  PIN write_data[19]
    DIRECTION INPUT ;
    USE SIGNAL ;
    PORT
      LAYER M4 ;
        RECT  0 13.872 0.084 13.896 ;
    END
  END write_data[19]
  PIN write_data[1]
    DIRECTION INPUT ;
    USE SIGNAL ;
    PORT
      LAYER M4 ;
        RECT  0 12.144 0.084 12.168 ;
    END
  END write_data[1]
  PIN write_data[20]
    DIRECTION INPUT ;
    USE SIGNAL ;
    PORT
      LAYER M4 ;
        RECT  0 13.968 0.084 13.992 ;
    END
  END write_data[20]
  PIN write_data[21]
    DIRECTION INPUT ;
    USE SIGNAL ;
    PORT
      LAYER M4 ;
        RECT  0 14.064 0.084 14.088 ;
    END
  END write_data[21]
  PIN write_data[22]
    DIRECTION INPUT ;
    USE SIGNAL ;
    PORT
      LAYER M4 ;
        RECT  0 14.16 0.084 14.184 ;
    END
  END write_data[22]
  PIN write_data[23]
    DIRECTION INPUT ;
    USE SIGNAL ;
    PORT
      LAYER M4 ;
        RECT  0 14.256 0.084 14.28 ;
    END
  END write_data[23]
  PIN write_data[24]
    DIRECTION INPUT ;
    USE SIGNAL ;
    PORT
      LAYER M4 ;
        RECT  0 14.352 0.084 14.376 ;
    END
  END write_data[24]
  PIN write_data[25]
    DIRECTION INPUT ;
    USE SIGNAL ;
    PORT
      LAYER M4 ;
        RECT  0 14.448 0.084 14.472 ;
    END
  END write_data[25]
  PIN write_data[26]
    DIRECTION INPUT ;
    USE SIGNAL ;
    PORT
      LAYER M4 ;
        RECT  0 14.544 0.084 14.568 ;
    END
  END write_data[26]
  PIN write_data[27]
    DIRECTION INPUT ;
    USE SIGNAL ;
    PORT
      LAYER M4 ;
        RECT  0 14.64 0.084 14.664 ;
    END
  END write_data[27]
  PIN write_data[28]
    DIRECTION INPUT ;
    USE SIGNAL ;
    PORT
      LAYER M4 ;
        RECT  0 14.736 0.084 14.76 ;
    END
  END write_data[28]
  PIN write_data[29]
    DIRECTION INPUT ;
    USE SIGNAL ;
    PORT
      LAYER M4 ;
        RECT  0 14.832 0.084 14.856 ;
    END
  END write_data[29]
  PIN write_data[2]
    DIRECTION INPUT ;
    USE SIGNAL ;
    PORT
      LAYER M4 ;
        RECT  0 12.24 0.084 12.264 ;
    END
  END write_data[2]
  PIN write_data[30]
    DIRECTION INPUT ;
    USE SIGNAL ;
    PORT
      LAYER M4 ;
        RECT  0 21.072 0.084 21.096 ;
    END
  END write_data[30]
  PIN write_data[31]
    DIRECTION INPUT ;
    USE SIGNAL ;
    PORT
      LAYER M4 ;
        RECT  0 21.168 0.084 21.192 ;
    END
  END write_data[31]
  PIN write_data[32]
    DIRECTION INPUT ;
    USE SIGNAL ;
    PORT
      LAYER M4 ;
        RECT  0 21.264 0.084 21.288 ;
    END
  END write_data[32]
  PIN write_data[33]
    DIRECTION INPUT ;
    USE SIGNAL ;
    PORT
      LAYER M4 ;
        RECT  0 21.36 0.084 21.384 ;
    END
  END write_data[33]
  PIN write_data[34]
    DIRECTION INPUT ;
    USE SIGNAL ;
    PORT
      LAYER M4 ;
        RECT  0 21.456 0.084 21.48 ;
    END
  END write_data[34]
  PIN write_data[35]
    DIRECTION INPUT ;
    USE SIGNAL ;
    PORT
      LAYER M4 ;
        RECT  0 21.552 0.084 21.576 ;
    END
  END write_data[35]
  PIN write_data[36]
    DIRECTION INPUT ;
    USE SIGNAL ;
    PORT
      LAYER M4 ;
        RECT  0 21.648 0.084 21.672 ;
    END
  END write_data[36]
  PIN write_data[37]
    DIRECTION INPUT ;
    USE SIGNAL ;
    PORT
      LAYER M4 ;
        RECT  0 21.744 0.084 21.768 ;
    END
  END write_data[37]
  PIN write_data[38]
    DIRECTION INPUT ;
    USE SIGNAL ;
    PORT
      LAYER M4 ;
        RECT  0 21.84 0.084 21.864 ;
    END
  END write_data[38]
  PIN write_data[39]
    DIRECTION INPUT ;
    USE SIGNAL ;
    PORT
      LAYER M4 ;
        RECT  0 21.936 0.084 21.96 ;
    END
  END write_data[39]
  PIN write_data[3]
    DIRECTION INPUT ;
    USE SIGNAL ;
    PORT
      LAYER M4 ;
        RECT  0 12.336 0.084 12.36 ;
    END
  END write_data[3]
  PIN write_data[40]
    DIRECTION INPUT ;
    USE SIGNAL ;
    PORT
      LAYER M4 ;
        RECT  0 22.032 0.084 22.056 ;
    END
  END write_data[40]
  PIN write_data[41]
    DIRECTION INPUT ;
    USE SIGNAL ;
    PORT
      LAYER M4 ;
        RECT  0 22.128 0.084 22.152 ;
    END
  END write_data[41]
  PIN write_data[42]
    DIRECTION INPUT ;
    USE SIGNAL ;
    PORT
      LAYER M4 ;
        RECT  0 22.224 0.084 22.248 ;
    END
  END write_data[42]
  PIN write_data[43]
    DIRECTION INPUT ;
    USE SIGNAL ;
    PORT
      LAYER M4 ;
        RECT  0 22.32 0.084 22.344 ;
    END
  END write_data[43]
  PIN write_data[44]
    DIRECTION INPUT ;
    USE SIGNAL ;
    PORT
      LAYER M4 ;
        RECT  0 22.416 0.084 22.44 ;
    END
  END write_data[44]
  PIN write_data[45]
    DIRECTION INPUT ;
    USE SIGNAL ;
    PORT
      LAYER M4 ;
        RECT  0 22.512 0.084 22.536 ;
    END
  END write_data[45]
  PIN write_data[46]
    DIRECTION INPUT ;
    USE SIGNAL ;
    PORT
      LAYER M4 ;
        RECT  0 22.608 0.084 22.632 ;
    END
  END write_data[46]
  PIN write_data[47]
    DIRECTION INPUT ;
    USE SIGNAL ;
    PORT
      LAYER M4 ;
        RECT  0 22.704 0.084 22.728 ;
    END
  END write_data[47]
  PIN write_data[48]
    DIRECTION INPUT ;
    USE SIGNAL ;
    PORT
      LAYER M4 ;
        RECT  0 22.8 0.084 22.824 ;
    END
  END write_data[48]
  PIN write_data[49]
    DIRECTION INPUT ;
    USE SIGNAL ;
    PORT
      LAYER M4 ;
        RECT  0 22.896 0.084 22.92 ;
    END
  END write_data[49]
  PIN write_data[4]
    DIRECTION INPUT ;
    USE SIGNAL ;
    PORT
      LAYER M4 ;
        RECT  0 12.432 0.084 12.456 ;
    END
  END write_data[4]
  PIN write_data[50]
    DIRECTION INPUT ;
    USE SIGNAL ;
    PORT
      LAYER M4 ;
        RECT  0 22.992 0.084 23.016 ;
    END
  END write_data[50]
  PIN write_data[51]
    DIRECTION INPUT ;
    USE SIGNAL ;
    PORT
      LAYER M4 ;
        RECT  0 23.088 0.084 23.112 ;
    END
  END write_data[51]
  PIN write_data[52]
    DIRECTION INPUT ;
    USE SIGNAL ;
    PORT
      LAYER M4 ;
        RECT  0 23.184 0.084 23.208 ;
    END
  END write_data[52]
  PIN write_data[53]
    DIRECTION INPUT ;
    USE SIGNAL ;
    PORT
      LAYER M4 ;
        RECT  0 23.28 0.084 23.304 ;
    END
  END write_data[53]
  PIN write_data[54]
    DIRECTION INPUT ;
    USE SIGNAL ;
    PORT
      LAYER M4 ;
        RECT  0 23.376 0.084 23.4 ;
    END
  END write_data[54]
  PIN write_data[55]
    DIRECTION INPUT ;
    USE SIGNAL ;
    PORT
      LAYER M4 ;
        RECT  0 23.472 0.084 23.496 ;
    END
  END write_data[55]
  PIN write_data[56]
    DIRECTION INPUT ;
    USE SIGNAL ;
    PORT
      LAYER M4 ;
        RECT  0 23.568 0.084 23.592 ;
    END
  END write_data[56]
  PIN write_data[57]
    DIRECTION INPUT ;
    USE SIGNAL ;
    PORT
      LAYER M4 ;
        RECT  0 23.664 0.084 23.688 ;
    END
  END write_data[57]
  PIN write_data[58]
    DIRECTION INPUT ;
    USE SIGNAL ;
    PORT
      LAYER M4 ;
        RECT  0 23.76 0.084 23.784 ;
    END
  END write_data[58]
  PIN write_data[59]
    DIRECTION INPUT ;
    USE SIGNAL ;
    PORT
      LAYER M4 ;
        RECT  0 23.856 0.084 23.88 ;
    END
  END write_data[59]
  PIN write_data[5]
    DIRECTION INPUT ;
    USE SIGNAL ;
    PORT
      LAYER M4 ;
        RECT  0 12.528 0.084 12.552 ;
    END
  END write_data[5]
  PIN write_data[60]
    DIRECTION INPUT ;
    USE SIGNAL ;
    PORT
      LAYER M4 ;
        RECT  0 23.952 0.084 23.976 ;
    END
  END write_data[60]
  PIN write_data[61]
    DIRECTION INPUT ;
    USE SIGNAL ;
    PORT
      LAYER M4 ;
        RECT  0 24.048 0.084 24.072 ;
    END
  END write_data[61]
  PIN write_data[62]
    DIRECTION INPUT ;
    USE SIGNAL ;
    PORT
      LAYER M4 ;
        RECT  0 62.544 0.084 62.568 ;
    END
  END write_data[62]
  PIN write_data[63]
    DIRECTION INPUT ;
    USE SIGNAL ;
    PORT
      LAYER M4 ;
        RECT  0 62.64 0.084 62.664 ;
    END
  END write_data[63]
  PIN write_data[64]
    DIRECTION INPUT ;
    USE SIGNAL ;
    PORT
      LAYER M4 ;
        RECT  0 62.736 0.084 62.76 ;
    END
  END write_data[64]
  PIN write_data[65]
    DIRECTION INPUT ;
    USE SIGNAL ;
    PORT
      LAYER M4 ;
        RECT  0 62.832 0.084 62.856 ;
    END
  END write_data[65]
  PIN write_data[66]
    DIRECTION INPUT ;
    USE SIGNAL ;
    PORT
      LAYER M4 ;
        RECT  0 62.928 0.084 62.952 ;
    END
  END write_data[66]
  PIN write_data[67]
    DIRECTION INPUT ;
    USE SIGNAL ;
    PORT
      LAYER M4 ;
        RECT  0 63.024 0.084 63.048 ;
    END
  END write_data[67]
  PIN write_data[68]
    DIRECTION INPUT ;
    USE SIGNAL ;
    PORT
      LAYER M4 ;
        RECT  0 63.12 0.084 63.144 ;
    END
  END write_data[68]
  PIN write_data[69]
    DIRECTION INPUT ;
    USE SIGNAL ;
    PORT
      LAYER M4 ;
        RECT  0 63.216 0.084 63.24 ;
    END
  END write_data[69]
  PIN write_data[6]
    DIRECTION INPUT ;
    USE SIGNAL ;
    PORT
      LAYER M4 ;
        RECT  0 12.624 0.084 12.648 ;
    END
  END write_data[6]
  PIN write_data[70]
    DIRECTION INPUT ;
    USE SIGNAL ;
    PORT
      LAYER M4 ;
        RECT  0 63.312 0.084 63.336 ;
    END
  END write_data[70]
  PIN write_data[71]
    DIRECTION INPUT ;
    USE SIGNAL ;
    PORT
      LAYER M4 ;
        RECT  0 63.408 0.084 63.432 ;
    END
  END write_data[71]
  PIN write_data[72]
    DIRECTION INPUT ;
    USE SIGNAL ;
    PORT
      LAYER M4 ;
        RECT  0 63.504 0.084 63.528 ;
    END
  END write_data[72]
  PIN write_data[73]
    DIRECTION INPUT ;
    USE SIGNAL ;
    PORT
      LAYER M4 ;
        RECT  0 63.6 0.084 63.624 ;
    END
  END write_data[73]
  PIN write_data[74]
    DIRECTION INPUT ;
    USE SIGNAL ;
    PORT
      LAYER M4 ;
        RECT  0 63.696 0.084 63.72 ;
    END
  END write_data[74]
  PIN write_data[75]
    DIRECTION INPUT ;
    USE SIGNAL ;
    PORT
      LAYER M4 ;
        RECT  0 63.792 0.084 63.816 ;
    END
  END write_data[75]
  PIN write_data[76]
    DIRECTION INPUT ;
    USE SIGNAL ;
    PORT
      LAYER M4 ;
        RECT  0 63.888 0.084 63.912 ;
    END
  END write_data[76]
  PIN write_data[77]
    DIRECTION INPUT ;
    USE SIGNAL ;
    PORT
      LAYER M4 ;
        RECT  0 63.984 0.084 64.008 ;
    END
  END write_data[77]
  PIN write_data[78]
    DIRECTION INPUT ;
    USE SIGNAL ;
    PORT
      LAYER M4 ;
        RECT  0 64.08 0.084 64.104 ;
    END
  END write_data[78]
  PIN write_data[79]
    DIRECTION INPUT ;
    USE SIGNAL ;
    PORT
      LAYER M4 ;
        RECT  0 64.176 0.084 64.2 ;
    END
  END write_data[79]
  PIN write_data[7]
    DIRECTION INPUT ;
    USE SIGNAL ;
    PORT
      LAYER M4 ;
        RECT  0 12.72 0.084 12.744 ;
    END
  END write_data[7]
  PIN write_data[80]
    DIRECTION INPUT ;
    USE SIGNAL ;
    PORT
      LAYER M4 ;
        RECT  0 64.272 0.084 64.296 ;
    END
  END write_data[80]
  PIN write_data[81]
    DIRECTION INPUT ;
    USE SIGNAL ;
    PORT
      LAYER M4 ;
        RECT  0 64.368 0.084 64.392 ;
    END
  END write_data[81]
  PIN write_data[82]
    DIRECTION INPUT ;
    USE SIGNAL ;
    PORT
      LAYER M4 ;
        RECT  0 64.464 0.084 64.488 ;
    END
  END write_data[82]
  PIN write_data[83]
    DIRECTION INPUT ;
    USE SIGNAL ;
    PORT
      LAYER M4 ;
        RECT  0 64.56 0.084 64.584 ;
    END
  END write_data[83]
  PIN write_data[84]
    DIRECTION INPUT ;
    USE SIGNAL ;
    PORT
      LAYER M4 ;
        RECT  0 64.656 0.084 64.68 ;
    END
  END write_data[84]
  PIN write_data[85]
    DIRECTION INPUT ;
    USE SIGNAL ;
    PORT
      LAYER M4 ;
        RECT  0 64.752 0.084 64.776 ;
    END
  END write_data[85]
  PIN write_data[86]
    DIRECTION INPUT ;
    USE SIGNAL ;
    PORT
      LAYER M4 ;
        RECT  0 64.848 0.084 64.872 ;
    END
  END write_data[86]
  PIN write_data[87]
    DIRECTION INPUT ;
    USE SIGNAL ;
    PORT
      LAYER M4 ;
        RECT  0 64.944 0.084 64.968 ;
    END
  END write_data[87]
  PIN write_data[88]
    DIRECTION INPUT ;
    USE SIGNAL ;
    PORT
      LAYER M4 ;
        RECT  0 65.04 0.084 65.064 ;
    END
  END write_data[88]
  PIN write_data[89]
    DIRECTION INPUT ;
    USE SIGNAL ;
    PORT
      LAYER M4 ;
        RECT  0 65.136 0.084 65.16 ;
    END
  END write_data[89]
  PIN write_data[8]
    DIRECTION INPUT ;
    USE SIGNAL ;
    PORT
      LAYER M4 ;
        RECT  0 12.816 0.084 12.84 ;
    END
  END write_data[8]
  PIN write_data[90]
    DIRECTION INPUT ;
    USE SIGNAL ;
    PORT
      LAYER M4 ;
        RECT  0 65.232 0.084 65.256 ;
    END
  END write_data[90]
  PIN write_data[91]
    DIRECTION INPUT ;
    USE SIGNAL ;
    PORT
      LAYER M4 ;
        RECT  0 65.328 0.084 65.352 ;
    END
  END write_data[91]
  PIN write_data[92]
    DIRECTION INPUT ;
    USE SIGNAL ;
    PORT
      LAYER M4 ;
        RECT  0 65.424 0.084 65.448 ;
    END
  END write_data[92]
  PIN write_data[93]
    DIRECTION INPUT ;
    USE SIGNAL ;
    PORT
      LAYER M4 ;
        RECT  0 65.52 0.084 65.544 ;
    END
  END write_data[93]
  PIN write_data[94]
    DIRECTION INPUT ;
    USE SIGNAL ;
    PORT
      LAYER M4 ;
        RECT  0 69.456 0.084 69.48 ;
    END
  END write_data[94]
  PIN write_data[95]
    DIRECTION INPUT ;
    USE SIGNAL ;
    PORT
      LAYER M4 ;
        RECT  0 69.552 0.084 69.576 ;
    END
  END write_data[95]
  PIN write_data[96]
    DIRECTION INPUT ;
    USE SIGNAL ;
    PORT
      LAYER M4 ;
        RECT  0 69.648 0.084 69.672 ;
    END
  END write_data[96]
  PIN write_data[97]
    DIRECTION INPUT ;
    USE SIGNAL ;
    PORT
      LAYER M4 ;
        RECT  0 69.744 0.084 69.768 ;
    END
  END write_data[97]
  PIN write_data[98]
    DIRECTION INPUT ;
    USE SIGNAL ;
    PORT
      LAYER M4 ;
        RECT  0 69.84 0.084 69.864 ;
    END
  END write_data[98]
  PIN write_data[99]
    DIRECTION INPUT ;
    USE SIGNAL ;
    PORT
      LAYER M4 ;
        RECT  0 69.936 0.084 69.96 ;
    END
  END write_data[99]
  PIN write_data[9]
    DIRECTION INPUT ;
    USE SIGNAL ;
    PORT
      LAYER M4 ;
        RECT  0 12.912 0.084 12.936 ;
    END
  END write_data[9]
  PIN VDD
    DIRECTION INOUT ;
    USE POWER ;
    PORT
      LAYER M5 ;
        RECT  83.592 2.151 83.712 86.409 ;
        RECT  78.192 2.151 78.312 86.409 ;
        RECT  72.792 2.151 72.912 86.409 ;
        RECT  67.392 2.151 67.512 86.409 ;
        RECT  61.992 2.151 62.112 86.409 ;
        RECT  56.592 2.151 56.712 86.409 ;
        RECT  51.192 2.151 51.312 86.409 ;
        RECT  45.792 2.151 45.912 86.409 ;
        RECT  40.392 2.151 40.512 86.409 ;
        RECT  34.992 2.151 35.112 86.409 ;
        RECT  29.592 2.151 29.712 86.409 ;
        RECT  24.192 2.151 24.312 86.409 ;
        RECT  18.792 2.151 18.912 86.409 ;
        RECT  13.392 2.151 13.512 86.409 ;
        RECT  7.992 2.151 8.112 86.409 ;
        RECT  2.592 2.151 2.712 86.409 ;
    END
  END VDD
  PIN VSS
    DIRECTION INOUT ;
    USE GROUND ;
    PORT
      LAYER M5 ;
        RECT  83.4 2.137 83.52 86.423 ;
        RECT  78 2.137 78.12 86.423 ;
        RECT  72.6 2.137 72.72 86.423 ;
        RECT  67.2 2.137 67.32 86.423 ;
        RECT  61.8 2.137 61.92 86.423 ;
        RECT  56.4 2.137 56.52 86.423 ;
        RECT  51 2.137 51.12 86.423 ;
        RECT  45.6 2.137 45.72 86.423 ;
        RECT  40.2 2.137 40.32 86.423 ;
        RECT  34.8 2.137 34.92 86.423 ;
        RECT  29.4 2.137 29.52 86.423 ;
        RECT  24 2.137 24.12 86.423 ;
        RECT  18.6 2.137 18.72 86.423 ;
        RECT  13.2 2.137 13.32 86.423 ;
        RECT  7.8 2.137 7.92 86.423 ;
        RECT  2.4 2.137 2.52 86.423 ;
    END
  END VSS
  OBS
    LAYER RVTN ;
     RECT  2.16 2.16 86.4 2.295 ;
     RECT  2.16 2.565 86.4 2.835 ;
     RECT  2.16 3.105 86.4 3.375 ;
     RECT  2.16 3.645 86.4 3.915 ;
     RECT  2.16 4.185 86.4 4.455 ;
     RECT  2.16 4.725 86.4 4.995 ;
     RECT  2.16 5.265 86.4 5.535 ;
     RECT  2.16 5.805 86.4 6.075 ;
     RECT  2.16 6.345 86.4 6.615 ;
     RECT  2.16 6.885 86.4 7.155 ;
     RECT  2.16 7.425 86.4 7.695 ;
     RECT  2.16 7.965 86.4 8.235 ;
     RECT  2.16 8.505 86.4 8.775 ;
     RECT  2.16 9.045 86.4 9.315 ;
     RECT  2.16 9.585 86.4 9.855 ;
     RECT  2.16 10.125 86.4 10.395 ;
     RECT  2.16 10.665 86.4 10.935 ;
     RECT  2.16 11.205 86.4 11.475 ;
     RECT  2.16 11.745 86.4 12.015 ;
     RECT  2.16 12.285 86.4 12.555 ;
     RECT  2.16 12.825 86.4 13.095 ;
     RECT  2.16 13.365 86.4 13.635 ;
     RECT  2.16 13.905 86.4 14.175 ;
     RECT  2.16 14.445 86.4 14.715 ;
     RECT  2.16 14.985 86.4 15.255 ;
     RECT  2.16 15.525 86.4 15.795 ;
     RECT  2.16 16.065 86.4 16.335 ;
     RECT  2.16 16.605 86.4 16.875 ;
     RECT  2.16 17.145 86.4 17.415 ;
     RECT  2.16 17.685 86.4 17.955 ;
     RECT  2.16 18.225 86.4 18.495 ;
     RECT  2.16 18.765 86.4 19.035 ;
     RECT  2.16 19.305 86.4 19.575 ;
     RECT  2.16 19.845 86.4 20.115 ;
     RECT  2.16 20.385 86.4 20.655 ;
     RECT  2.16 20.925 86.4 21.195 ;
     RECT  2.16 21.465 86.4 21.735 ;
     RECT  2.16 22.005 86.4 22.275 ;
     RECT  2.16 22.545 86.4 22.815 ;
     RECT  2.16 23.085 86.4 23.355 ;
     RECT  2.16 23.625 86.4 23.895 ;
     RECT  2.16 24.165 86.4 24.435 ;
     RECT  2.16 24.705 86.4 24.975 ;
     RECT  2.16 25.245 86.4 25.515 ;
     RECT  2.16 25.785 86.4 26.055 ;
     RECT  2.16 26.325 86.4 26.595 ;
     RECT  2.16 26.865 86.4 27.135 ;
     RECT  2.16 27.405 86.4 27.675 ;
     RECT  2.16 27.945 86.4 28.215 ;
     RECT  2.16 28.485 86.4 28.755 ;
     RECT  2.16 29.025 86.4 29.295 ;
     RECT  2.16 29.565 86.4 29.835 ;
     RECT  2.16 30.105 86.4 30.375 ;
     RECT  2.16 30.645 86.4 30.915 ;
     RECT  2.16 31.185 86.4 31.455 ;
     RECT  2.16 31.725 86.4 31.995 ;
     RECT  2.16 32.265 86.4 32.535 ;
     RECT  2.16 32.805 86.4 33.075 ;
     RECT  2.16 33.345 86.4 33.615 ;
     RECT  2.16 33.885 86.4 34.155 ;
     RECT  2.16 34.425 86.4 34.695 ;
     RECT  2.16 34.965 86.4 35.235 ;
     RECT  2.16 35.505 86.4 35.775 ;
     RECT  2.16 36.045 86.4 36.315 ;
     RECT  2.16 36.585 86.4 36.855 ;
     RECT  2.16 37.125 86.4 37.395 ;
     RECT  2.16 37.665 86.4 37.935 ;
     RECT  2.16 38.205 86.4 38.475 ;
     RECT  2.16 38.745 86.4 39.015 ;
     RECT  2.16 39.285 86.4 39.555 ;
     RECT  2.16 39.825 86.4 40.095 ;
     RECT  2.16 40.365 86.4 40.635 ;
     RECT  2.16 40.905 86.4 41.175 ;
     RECT  2.16 41.445 86.4 41.715 ;
     RECT  2.16 41.985 86.4 42.255 ;
     RECT  2.16 42.525 86.4 42.795 ;
     RECT  2.16 43.065 86.4 43.335 ;
     RECT  2.16 43.605 86.4 43.875 ;
     RECT  2.16 44.145 86.4 44.415 ;
     RECT  2.16 44.685 86.4 44.955 ;
     RECT  2.16 45.225 86.4 45.495 ;
     RECT  2.16 45.765 86.4 46.035 ;
     RECT  2.16 46.305 86.4 46.575 ;
     RECT  2.16 46.845 86.4 47.115 ;
     RECT  2.16 47.385 86.4 47.655 ;
     RECT  2.16 47.925 86.4 48.195 ;
     RECT  2.16 48.465 86.4 48.735 ;
     RECT  2.16 49.005 86.4 49.275 ;
     RECT  2.16 49.545 86.4 49.815 ;
     RECT  2.16 50.085 86.4 50.355 ;
     RECT  2.16 50.625 86.4 50.895 ;
     RECT  2.16 51.165 86.4 51.435 ;
     RECT  2.16 51.705 86.4 51.975 ;
     RECT  2.16 52.245 86.4 52.515 ;
     RECT  2.16 52.785 86.4 53.055 ;
     RECT  2.16 53.325 86.4 53.595 ;
     RECT  2.16 53.865 86.4 54.135 ;
     RECT  2.16 54.405 86.4 54.675 ;
     RECT  2.16 54.945 86.4 55.215 ;
     RECT  2.16 55.485 86.4 55.755 ;
     RECT  2.16 56.025 86.4 56.295 ;
     RECT  2.16 56.565 86.4 56.835 ;
     RECT  2.16 57.105 86.4 57.375 ;
     RECT  2.16 57.645 86.4 57.915 ;
     RECT  2.16 58.185 86.4 58.455 ;
     RECT  2.16 58.725 86.4 58.995 ;
     RECT  2.16 59.265 86.4 59.535 ;
     RECT  2.16 59.805 86.4 60.075 ;
     RECT  2.16 60.345 86.4 60.615 ;
     RECT  2.16 60.885 86.4 61.155 ;
     RECT  2.16 61.425 86.4 61.695 ;
     RECT  2.16 61.965 86.4 62.235 ;
     RECT  2.16 62.505 86.4 62.775 ;
     RECT  2.16 63.045 86.4 63.315 ;
     RECT  2.16 63.585 86.4 63.855 ;
     RECT  2.16 64.125 86.4 64.395 ;
     RECT  2.16 64.665 86.4 64.935 ;
     RECT  2.16 65.205 86.4 65.475 ;
     RECT  2.16 65.745 86.4 66.015 ;
     RECT  2.16 66.285 86.4 66.555 ;
     RECT  2.16 66.825 86.4 67.095 ;
     RECT  2.16 67.365 86.4 67.635 ;
     RECT  2.16 67.905 86.4 68.175 ;
     RECT  2.16 68.445 86.4 68.715 ;
     RECT  2.16 68.985 86.4 69.255 ;
     RECT  2.16 69.525 86.4 69.795 ;
     RECT  2.16 70.065 86.4 70.335 ;
     RECT  2.16 70.605 86.4 70.875 ;
     RECT  2.16 71.145 86.4 71.415 ;
     RECT  2.16 71.685 86.4 71.955 ;
     RECT  2.16 72.225 86.4 72.495 ;
     RECT  2.16 72.765 86.4 73.035 ;
     RECT  2.16 73.305 86.4 73.575 ;
     RECT  2.16 73.845 86.4 74.115 ;
     RECT  2.16 74.385 86.4 74.655 ;
     RECT  2.16 74.925 86.4 75.195 ;
     RECT  2.16 75.465 86.4 75.735 ;
     RECT  2.16 76.005 86.4 76.275 ;
     RECT  2.16 76.545 86.4 76.815 ;
     RECT  2.16 77.085 86.4 77.355 ;
     RECT  2.16 77.625 86.4 77.895 ;
     RECT  2.16 78.165 86.4 78.435 ;
     RECT  2.16 78.705 86.4 78.975 ;
     RECT  2.16 79.245 86.4 79.515 ;
     RECT  2.16 79.785 86.4 80.055 ;
     RECT  2.16 80.325 86.4 80.595 ;
     RECT  2.16 80.865 86.4 81.135 ;
     RECT  2.16 81.405 86.4 81.675 ;
     RECT  2.16 81.945 86.4 82.215 ;
     RECT  2.16 82.485 86.4 82.755 ;
     RECT  2.16 83.025 86.4 83.295 ;
     RECT  2.16 83.565 86.4 83.835 ;
     RECT  2.16 84.105 86.4 84.375 ;
     RECT  2.16 84.645 86.4 84.915 ;
     RECT  2.16 85.185 86.4 85.455 ;
     RECT  2.16 85.725 86.4 85.995 ;
     RECT  2.16 86.265 86.4 86.4 ;
    LAYER RVTP ;
     RECT  2.16 2.295 86.4 2.565 ;
     RECT  2.16 2.835 86.4 3.105 ;
     RECT  2.16 3.375 86.4 3.645 ;
     RECT  2.16 3.915 86.4 4.185 ;
     RECT  2.16 4.455 86.4 4.725 ;
     RECT  2.16 4.995 86.4 5.265 ;
     RECT  2.16 5.535 86.4 5.805 ;
     RECT  2.16 6.075 86.4 6.345 ;
     RECT  2.16 6.615 86.4 6.885 ;
     RECT  2.16 7.155 86.4 7.425 ;
     RECT  2.16 7.695 86.4 7.965 ;
     RECT  2.16 8.235 86.4 8.505 ;
     RECT  2.16 8.775 86.4 9.045 ;
     RECT  2.16 9.315 86.4 9.585 ;
     RECT  2.16 9.855 86.4 10.125 ;
     RECT  2.16 10.395 86.4 10.665 ;
     RECT  2.16 10.935 86.4 11.205 ;
     RECT  2.16 11.475 86.4 11.745 ;
     RECT  2.16 12.015 86.4 12.285 ;
     RECT  2.16 12.555 86.4 12.825 ;
     RECT  2.16 13.095 86.4 13.365 ;
     RECT  2.16 13.635 86.4 13.905 ;
     RECT  2.16 14.175 86.4 14.445 ;
     RECT  2.16 14.715 86.4 14.985 ;
     RECT  2.16 15.255 86.4 15.525 ;
     RECT  2.16 15.795 86.4 16.065 ;
     RECT  2.16 16.335 86.4 16.605 ;
     RECT  2.16 16.875 86.4 17.145 ;
     RECT  2.16 17.415 86.4 17.685 ;
     RECT  2.16 17.955 86.4 18.225 ;
     RECT  2.16 18.495 86.4 18.765 ;
     RECT  2.16 19.035 86.4 19.305 ;
     RECT  2.16 19.575 86.4 19.845 ;
     RECT  2.16 20.115 86.4 20.385 ;
     RECT  2.16 20.655 86.4 20.925 ;
     RECT  2.16 21.195 86.4 21.465 ;
     RECT  2.16 21.735 86.4 22.005 ;
     RECT  2.16 22.275 86.4 22.545 ;
     RECT  2.16 22.815 86.4 23.085 ;
     RECT  2.16 23.355 86.4 23.625 ;
     RECT  2.16 23.895 86.4 24.165 ;
     RECT  2.16 24.435 86.4 24.705 ;
     RECT  2.16 24.975 86.4 25.245 ;
     RECT  2.16 25.515 86.4 25.785 ;
     RECT  2.16 26.055 86.4 26.325 ;
     RECT  2.16 26.595 86.4 26.865 ;
     RECT  2.16 27.135 86.4 27.405 ;
     RECT  2.16 27.675 86.4 27.945 ;
     RECT  2.16 28.215 86.4 28.485 ;
     RECT  2.16 28.755 86.4 29.025 ;
     RECT  2.16 29.295 86.4 29.565 ;
     RECT  2.16 29.835 86.4 30.105 ;
     RECT  2.16 30.375 86.4 30.645 ;
     RECT  2.16 30.915 86.4 31.185 ;
     RECT  2.16 31.455 86.4 31.725 ;
     RECT  2.16 31.995 86.4 32.265 ;
     RECT  2.16 32.535 86.4 32.805 ;
     RECT  2.16 33.075 86.4 33.345 ;
     RECT  2.16 33.615 86.4 33.885 ;
     RECT  2.16 34.155 86.4 34.425 ;
     RECT  2.16 34.695 86.4 34.965 ;
     RECT  2.16 35.235 86.4 35.505 ;
     RECT  2.16 35.775 86.4 36.045 ;
     RECT  2.16 36.315 86.4 36.585 ;
     RECT  2.16 36.855 86.4 37.125 ;
     RECT  2.16 37.395 86.4 37.665 ;
     RECT  2.16 37.935 86.4 38.205 ;
     RECT  2.16 38.475 86.4 38.745 ;
     RECT  2.16 39.015 86.4 39.285 ;
     RECT  2.16 39.555 86.4 39.825 ;
     RECT  2.16 40.095 86.4 40.365 ;
     RECT  2.16 40.635 86.4 40.905 ;
     RECT  2.16 41.175 86.4 41.445 ;
     RECT  2.16 41.715 86.4 41.985 ;
     RECT  2.16 42.255 86.4 42.525 ;
     RECT  2.16 42.795 86.4 43.065 ;
     RECT  2.16 43.335 86.4 43.605 ;
     RECT  2.16 43.875 86.4 44.145 ;
     RECT  2.16 44.415 86.4 44.685 ;
     RECT  2.16 44.955 86.4 45.225 ;
     RECT  2.16 45.495 86.4 45.765 ;
     RECT  2.16 46.035 86.4 46.305 ;
     RECT  2.16 46.575 86.4 46.845 ;
     RECT  2.16 47.115 86.4 47.385 ;
     RECT  2.16 47.655 86.4 47.925 ;
     RECT  2.16 48.195 86.4 48.465 ;
     RECT  2.16 48.735 86.4 49.005 ;
     RECT  2.16 49.275 86.4 49.545 ;
     RECT  2.16 49.815 86.4 50.085 ;
     RECT  2.16 50.355 86.4 50.625 ;
     RECT  2.16 50.895 86.4 51.165 ;
     RECT  2.16 51.435 86.4 51.705 ;
     RECT  2.16 51.975 86.4 52.245 ;
     RECT  2.16 52.515 86.4 52.785 ;
     RECT  2.16 53.055 86.4 53.325 ;
     RECT  2.16 53.595 86.4 53.865 ;
     RECT  2.16 54.135 86.4 54.405 ;
     RECT  2.16 54.675 86.4 54.945 ;
     RECT  2.16 55.215 86.4 55.485 ;
     RECT  2.16 55.755 86.4 56.025 ;
     RECT  2.16 56.295 86.4 56.565 ;
     RECT  2.16 56.835 86.4 57.105 ;
     RECT  2.16 57.375 86.4 57.645 ;
     RECT  2.16 57.915 86.4 58.185 ;
     RECT  2.16 58.455 86.4 58.725 ;
     RECT  2.16 58.995 86.4 59.265 ;
     RECT  2.16 59.535 86.4 59.805 ;
     RECT  2.16 60.075 86.4 60.345 ;
     RECT  2.16 60.615 86.4 60.885 ;
     RECT  2.16 61.155 86.4 61.425 ;
     RECT  2.16 61.695 86.4 61.965 ;
     RECT  2.16 62.235 86.4 62.505 ;
     RECT  2.16 62.775 86.4 63.045 ;
     RECT  2.16 63.315 86.4 63.585 ;
     RECT  2.16 63.855 86.4 64.125 ;
     RECT  2.16 64.395 86.4 64.665 ;
     RECT  2.16 64.935 86.4 65.205 ;
     RECT  2.16 65.475 86.4 65.745 ;
     RECT  2.16 66.015 86.4 66.285 ;
     RECT  2.16 66.555 86.4 66.825 ;
     RECT  2.16 67.095 86.4 67.365 ;
     RECT  2.16 67.635 86.4 67.905 ;
     RECT  2.16 68.175 86.4 68.445 ;
     RECT  2.16 68.715 86.4 68.985 ;
     RECT  2.16 69.255 86.4 69.525 ;
     RECT  2.16 69.795 86.4 70.065 ;
     RECT  2.16 70.335 86.4 70.605 ;
     RECT  2.16 70.875 86.4 71.145 ;
     RECT  2.16 71.415 86.4 71.685 ;
     RECT  2.16 71.955 86.4 72.225 ;
     RECT  2.16 72.495 86.4 72.765 ;
     RECT  2.16 73.035 86.4 73.305 ;
     RECT  2.16 73.575 86.4 73.845 ;
     RECT  2.16 74.115 86.4 74.385 ;
     RECT  2.16 74.655 86.4 74.925 ;
     RECT  2.16 75.195 86.4 75.465 ;
     RECT  2.16 75.735 86.4 76.005 ;
     RECT  2.16 76.275 86.4 76.545 ;
     RECT  2.16 76.815 86.4 77.085 ;
     RECT  2.16 77.355 86.4 77.625 ;
     RECT  2.16 77.895 86.4 78.165 ;
     RECT  2.16 78.435 86.4 78.705 ;
     RECT  2.16 78.975 86.4 79.245 ;
     RECT  2.16 79.515 86.4 79.785 ;
     RECT  2.16 80.055 86.4 80.325 ;
     RECT  2.16 80.595 86.4 80.865 ;
     RECT  2.16 81.135 86.4 81.405 ;
     RECT  2.16 81.675 86.4 81.945 ;
     RECT  2.16 82.215 86.4 82.485 ;
     RECT  2.16 82.755 86.4 83.025 ;
     RECT  2.16 83.295 86.4 83.565 ;
     RECT  2.16 83.835 86.4 84.105 ;
     RECT  2.16 84.375 86.4 84.645 ;
     RECT  2.16 84.915 86.4 85.185 ;
     RECT  2.16 85.455 86.4 85.725 ;
     RECT  2.16 85.995 86.4 86.265 ;
    LAYER M1 ;
     RECT  2.16 2.151 86.4 86.409 ;
    LAYER M2 ;
     RECT  0.031 65.25 0.067 65.268 ;
     RECT  0.031 66.726 0.067 66.744 ;
     RECT  0.031 12.996 0.103 13.014 ;
     RECT  0.031 45 0.103 45.018 ;
     RECT  0.067 71.082 0.103 71.1 ;
     RECT  0.031 26.676 0.131 26.694 ;
     RECT  0.103 12.996 0.139 13.086 ;
     RECT  0.103 69.192 0.139 69.318 ;
     RECT  0.103 70.461 0.139 71.1 ;
     RECT  0.067 22.131 0.167 22.149 ;
     RECT  0.139 69.192 0.167 71.1 ;
     RECT  0.139 11.52 0.175 11.538 ;
     RECT  0.139 12.528 0.175 13.086 ;
     RECT  0.103 45 0.203 45.414 ;
     RECT  0.067 65.106 0.203 65.268 ;
     RECT  0.067 66.492 0.203 66.744 ;
     RECT  0.167 69.192 0.239 70.479 ;
     RECT  0.103 42.57 0.535 42.588 ;
     RECT  0.203 45 0.535 45.018 ;
     RECT  0.139 72.27 0.535 72.288 ;
     RECT  0.103 73.044 0.535 73.062 ;
     RECT  0.239 69.192 0.571 69.822 ;
     RECT  0.535 72.27 0.571 73.062 ;
     RECT  0.571 68.724 1.723 69.822 ;
     RECT  0.571 72.27 1.723 73.8 ;
     RECT  0.175 11.52 2.16 13.086 ;
     RECT  1.723 14.652 2.16 14.67 ;
     RECT  0.031 16.542 2.16 16.56 ;
     RECT  0.067 28.422 2.16 28.44 ;
     RECT  0.103 29.232 2.16 29.25 ;
     RECT  0.031 30.852 2.16 30.87 ;
     RECT  0.535 42.57 2.16 43.326 ;
     RECT  0.535 44.766 2.16 45.018 ;
     RECT  0.067 59.742 2.16 59.76 ;
     RECT  0.283 61.398 2.16 61.416 ;
     RECT  0.139 62.28 2.16 62.298 ;
     RECT  0.247 63.828 2.16 63.846 ;
     RECT  0.203 65.25 2.16 65.268 ;
     RECT  0.203 66.492 2.16 66.51 ;
     RECT  0.535 67.806 2.16 67.824 ;
     RECT  1.723 68.724 2.16 69.858 ;
     RECT  1.723 70.731 2.16 70.749 ;
     RECT  1.723 71.892 2.16 73.8 ;
     RECT  2.16 2.151 30.775 86.409 ;
     RECT  30.775 2.151 32.251 86.526 ;
     RECT  32.251 2.151 34.987 86.598 ;
     RECT  34.987 2.151 37.247 86.634 ;
     RECT  37.247 2.151 38.579 86.598 ;
     RECT  38.579 2.151 39.811 86.526 ;
     RECT  39.811 2.151 40.459 86.562 ;
     RECT  40.459 2.151 41.891 87.219 ;
     RECT  41.891 87.201 42.827 87.219 ;
     RECT  41.891 2.151 43.411 86.454 ;
     RECT  43.411 2.151 44.455 86.598 ;
     RECT  44.455 2.151 44.555 86.634 ;
     RECT  44.555 2.151 49.279 86.598 ;
     RECT  49.279 2.151 49.811 86.634 ;
     RECT  49.811 2.151 54.463 86.409 ;
     RECT  54.463 2.151 59.675 86.454 ;
     RECT  59.675 2.151 86.4 86.409 ;
     RECT  86.4 33.588 87.215 33.84 ;
     RECT  87.215 33.822 88.475 33.84 ;
     RECT  88.447 33.012 88.547 33.03 ;
     RECT  86.4 37.296 88.547 37.314 ;
    LAYER M3 ;
     RECT  56.415 2.143 56.505 2.227 ;
     RECT  32.148 2.191 32.166 2.251 ;
     RECT  45.615 2.143 45.705 2.251 ;
     RECT  52.56 2.191 52.578 2.263 ;
     RECT  52.128 2.263 52.578 2.293 ;
     RECT  51.015 2.143 51.105 2.299 ;
     RECT  55.764 2.227 56.505 2.299 ;
     RECT  31.5 2.251 32.166 2.371 ;
     RECT  40.215 2.143 40.305 2.371 ;
     RECT  45.615 2.251 46.206 2.371 ;
     RECT  47.592 2.299 47.61 2.371 ;
     RECT  50.004 2.299 51.105 2.371 ;
     RECT  52.128 2.293 53.262 2.371 ;
     RECT  55.62 2.299 56.505 2.371 ;
     RECT  2.415 2.143 2.505 2.413 ;
     RECT  7.815 2.143 7.905 2.413 ;
     RECT  13.215 2.143 13.305 2.413 ;
     RECT  18.615 2.143 18.705 2.413 ;
     RECT  24.015 2.143 24.105 2.413 ;
     RECT  29.415 2.143 29.505 2.413 ;
     RECT  34.815 2.143 34.905 2.413 ;
     RECT  49.968 2.371 51.105 2.413 ;
     RECT  61.815 2.143 61.905 2.413 ;
     RECT  67.215 2.143 67.305 2.413 ;
     RECT  72.615 2.143 72.705 2.413 ;
     RECT  78.015 2.143 78.105 2.413 ;
     RECT  83.415 2.143 83.505 2.413 ;
     RECT  40.215 2.371 40.77 2.461 ;
     RECT  55.044 2.371 56.754 2.491 ;
     RECT  37.116 2.371 37.134 2.533 ;
     RECT  39.6 2.461 40.77 2.533 ;
     RECT  52.128 2.371 53.658 2.533 ;
     RECT  55.044 2.491 57.402 2.533 ;
     RECT  37.116 2.533 37.314 2.569 ;
     RECT  39.528 2.533 40.77 2.569 ;
     RECT  54.936 2.533 57.402 2.569 ;
     RECT  37.116 2.569 37.386 2.641 ;
     RECT  45.615 2.371 47.79 2.641 ;
     RECT  49.968 2.413 51.297 2.641 ;
     RECT  52.128 2.533 53.838 2.641 ;
     RECT  31.5 2.371 32.382 2.731 ;
     RECT  52.128 2.641 54.09 2.731 ;
     RECT  54.936 2.569 57.51 2.731 ;
     RECT  31.5 2.731 32.814 2.767 ;
     RECT  37.116 2.641 37.422 2.767 ;
     RECT  37.08 2.767 37.53 2.875 ;
     RECT  30.816 2.767 32.814 2.911 ;
     RECT  36.396 2.875 37.53 2.911 ;
     RECT  38.412 2.875 38.43 2.911 ;
     RECT  39.456 2.569 40.77 2.911 ;
     RECT  42.192 2.767 42.21 2.911 ;
     RECT  49.788 2.641 51.297 2.911 ;
     RECT  52.128 2.731 57.51 2.911 ;
     RECT  41.904 2.911 42.678 3.001 ;
     RECT  44.784 2.569 44.802 3.001 ;
     RECT  49.788 2.911 58.158 3.029 ;
     RECT  41.832 3.001 42.678 3.037 ;
     RECT  49.788 3.029 57.762 3.037 ;
     RECT  44.1 3.001 44.802 3.073 ;
     RECT  45.615 2.641 48.258 3.073 ;
     RECT  36.396 2.911 40.77 3.109 ;
     RECT  41.724 3.037 42.678 3.109 ;
     RECT  30.816 2.911 33.03 3.271 ;
     RECT  34.815 2.413 35.097 3.271 ;
     RECT  36.396 3.109 42.678 3.271 ;
     RECT  44.1 3.073 48.258 3.307 ;
     RECT  29.415 2.413 29.697 3.343 ;
     RECT  30.78 3.271 33.03 3.343 ;
     RECT  36.216 3.271 42.678 3.355 ;
     RECT  34.815 3.271 35.19 3.379 ;
     RECT  35.928 3.355 42.678 3.379 ;
     RECT  44.1 3.307 48.546 3.379 ;
     RECT  29.415 3.343 33.03 3.403 ;
     RECT  34.815 3.379 42.678 3.403 ;
     RECT  49.752 3.037 57.762 3.403 ;
     RECT  34.815 3.403 43.29 3.451 ;
     RECT  44.028 3.379 48.546 3.451 ;
     RECT  49.392 3.403 57.762 3.451 ;
     RECT  24.015 2.413 24.297 3.541 ;
     RECT  25.056 3.451 25.074 3.541 ;
     RECT  24.015 3.541 25.074 3.685 ;
     RECT  27.972 3.541 27.99 3.685 ;
     RECT  23.364 3.685 25.074 3.721 ;
     RECT  27.936 3.685 27.99 3.721 ;
     RECT  29.232 3.403 33.03 3.721 ;
     RECT  33.876 3.451 43.29 3.721 ;
     RECT  44.028 3.451 57.762 3.721 ;
     RECT  26.28 3.451 26.298 3.847 ;
     RECT  59.184 3.271 59.202 3.847 ;
     RECT  27.936 3.721 28.134 3.883 ;
     RECT  28.872 3.721 57.762 3.883 ;
     RECT  59.148 3.847 59.31 3.883 ;
     RECT  26.28 3.847 26.694 3.919 ;
     RECT  26.064 3.919 26.73 3.955 ;
     RECT  27.936 3.883 57.762 3.955 ;
     RECT  59.148 3.883 59.526 3.955 ;
     RECT  23.364 3.721 25.218 3.979 ;
     RECT  26.064 3.955 27.018 3.979 ;
     RECT  23.364 3.979 27.018 3.991 ;
     RECT  27.936 3.955 57.942 3.991 ;
     RECT  27.9 3.991 57.942 4.081 ;
     RECT  59.004 3.955 59.526 4.081 ;
     RECT  27.9 4.081 59.706 4.189 ;
     RECT  60.444 3.979 60.462 4.189 ;
     RECT  61.815 2.413 62.097 4.189 ;
     RECT  27.9 4.189 62.097 4.261 ;
     RECT  62.892 4.225 62.91 4.261 ;
     RECT  23.04 3.991 27.018 4.531 ;
     RECT  27.9 4.261 63.162 4.531 ;
     RECT  64.008 3.991 64.026 4.531 ;
     RECT  64.008 4.531 64.386 4.621 ;
     RECT  23.04 4.531 63.162 4.649 ;
     RECT  64.008 4.621 64.458 4.693 ;
     RECT  36.288 4.649 63.162 4.801 ;
     RECT  64.008 4.693 64.638 4.801 ;
     RECT  23.04 4.649 35.55 4.829 ;
     RECT  36.288 4.801 63.27 4.891 ;
     RECT  64.008 4.801 64.71 4.891 ;
     RECT  36.288 4.891 64.71 5.021 ;
     RECT  55.548 5.021 64.71 5.071 ;
     RECT  23.04 4.829 23.058 5.333 ;
     RECT  23.94 4.829 35.55 5.431 ;
     RECT  36.288 5.021 54.81 5.431 ;
     RECT  55.548 5.071 64.998 5.611 ;
     RECT  23.94 5.431 54.81 5.701 ;
     RECT  21.78 5.539 21.798 5.773 ;
     RECT  55.548 5.611 65.322 5.773 ;
     RECT  55.548 5.773 65.718 5.845 ;
     RECT  21.096 5.773 21.798 5.873 ;
     RECT  23.328 5.701 54.81 5.881 ;
     RECT  55.548 5.845 66.186 5.881 ;
     RECT  67.215 2.413 67.497 5.881 ;
     RECT  23.328 5.881 67.497 6.079 ;
     RECT  22.824 6.079 67.497 6.691 ;
     RECT  13.215 2.413 13.497 6.889 ;
     RECT  17.82 6.889 17.838 6.925 ;
     RECT  17.172 6.925 17.838 6.961 ;
     RECT  18.615 2.413 18.897 6.961 ;
     RECT  21.78 5.873 21.798 6.961 ;
     RECT  15.084 6.961 15.102 7.051 ;
     RECT  21.708 6.961 21.798 7.051 ;
     RECT  22.752 6.691 67.497 7.079 ;
     RECT  13.215 6.889 14.202 7.087 ;
     RECT  15.084 7.051 15.354 7.087 ;
     RECT  16.128 5.845 16.146 7.087 ;
     RECT  21.708 7.051 21.978 7.123 ;
     RECT  36.468 7.079 67.497 7.133 ;
     RECT  17.172 6.961 18.897 7.195 ;
     RECT  13.215 7.087 16.146 7.231 ;
     RECT  16.92 7.195 18.897 7.231 ;
     RECT  21.132 7.123 21.978 7.231 ;
     RECT  13.215 7.231 19.206 7.349 ;
     RECT  45.615 7.133 67.497 7.357 ;
     RECT  20.16 7.123 20.178 7.393 ;
     RECT  21.06 7.231 21.978 7.393 ;
     RECT  20.16 7.393 21.978 7.465 ;
     RECT  22.752 7.079 35.658 7.465 ;
     RECT  45.615 7.357 67.59 7.465 ;
     RECT  18.432 7.349 19.206 7.501 ;
     RECT  20.16 7.465 35.658 7.501 ;
     RECT  45.615 7.465 67.626 7.501 ;
     RECT  45.615 7.501 67.914 7.619 ;
     RECT  45.615 7.619 67.626 7.861 ;
     RECT  36.468 7.133 44.694 7.897 ;
     RECT  45.612 7.861 67.626 7.897 ;
     RECT  18.432 7.501 35.658 7.949 ;
     RECT  19.944 7.949 35.658 7.963 ;
     RECT  36.468 7.897 67.626 7.963 ;
     RECT  18.432 7.949 19.206 8.131 ;
     RECT  13.215 7.349 17.55 8.203 ;
     RECT  18.324 8.131 19.206 8.203 ;
     RECT  13.215 8.203 19.206 8.545 ;
     RECT  8.856 7.663 8.874 8.707 ;
     RECT  12.492 8.545 19.206 8.815 ;
     RECT  19.944 7.963 67.626 8.815 ;
     RECT  12.492 8.815 67.626 9.067 ;
     RECT  12.42 9.067 67.626 9.589 ;
     RECT  12.42 9.589 67.662 9.661 ;
     RECT  11.52 9.751 11.538 9.787 ;
     RECT  12.42 9.661 67.914 9.787 ;
     RECT  11.52 9.787 67.914 10.049 ;
     RECT  23.364 10.049 67.914 10.093 ;
     RECT  11.52 10.049 22.59 10.165 ;
     RECT  10.08 7.969 10.098 10.201 ;
     RECT  11.484 10.165 22.59 10.201 ;
     RECT  7.815 2.413 8.097 10.651 ;
     RECT  8.856 8.707 8.946 10.651 ;
     RECT  11.34 10.201 22.59 10.705 ;
     RECT  23.364 10.093 68.382 10.867 ;
     RECT  23.364 10.867 68.562 10.939 ;
     RECT  23.364 10.939 68.742 11.039 ;
     RECT  5.616 11.011 5.634 11.129 ;
     RECT  2.415 2.413 2.697 11.137 ;
     RECT  23.364 11.039 68.67 11.309 ;
     RECT  10.944 10.705 22.59 11.407 ;
     RECT  23.364 11.309 68.562 11.407 ;
     RECT  10.08 10.201 10.206 11.515 ;
     RECT  10.944 11.407 68.562 11.515 ;
     RECT  0.144 11.515 0.162 11.755 ;
     RECT  5.256 11.245 5.274 11.755 ;
     RECT  0.108 11.755 0.162 11.785 ;
     RECT  4.68 11.755 5.274 11.785 ;
     RECT  2.304 11.137 2.697 11.821 ;
     RECT  3.42 11.803 3.438 11.821 ;
     RECT  4.536 11.785 5.274 11.821 ;
     RECT  7.815 10.651 8.946 11.821 ;
     RECT  10.08 11.515 68.562 11.821 ;
     RECT  69.516 10.867 69.534 11.821 ;
     RECT  4.284 11.821 5.274 11.911 ;
     RECT  2.304 11.821 3.438 12.055 ;
     RECT  7.815 11.821 68.562 12.091 ;
     RECT  69.516 11.821 70.038 12.091 ;
     RECT  2.268 12.055 3.438 12.181 ;
     RECT  4.284 11.911 5.67 12.181 ;
     RECT  7.815 12.091 70.038 12.325 ;
     RECT  6.876 11.641 6.894 12.361 ;
     RECT  2.268 12.181 5.67 12.451 ;
     RECT  6.588 12.361 6.966 12.451 ;
     RECT  2.268 12.451 6.966 12.479 ;
     RECT  2.268 12.479 6.678 12.551 ;
     RECT  6.66 12.551 6.678 12.557 ;
     RECT  0.108 11.785 0.198 12.859 ;
     RECT  0.108 12.859 0.27 12.991 ;
     RECT  0.036 12.991 0.27 13.037 ;
     RECT  7.704 12.325 70.722 13.171 ;
     RECT  2.268 12.551 5.922 13.195 ;
     RECT  1.728 13.195 5.922 13.291 ;
     RECT  1.728 13.291 6.138 13.405 ;
     RECT  7.416 13.171 70.722 13.405 ;
     RECT  1.728 13.405 70.722 13.595 ;
     RECT  7.272 13.595 70.722 13.661 ;
     RECT  1.728 13.595 5.994 13.667 ;
     RECT  0.036 13.037 0.126 13.819 ;
     RECT  0.036 13.819 0.162 14.059 ;
     RECT  0.036 14.059 0.342 14.189 ;
     RECT  5.004 13.667 5.994 14.341 ;
     RECT  5.004 14.341 6.534 14.381 ;
     RECT  7.344 13.661 70.722 14.521 ;
     RECT  1.728 13.667 4.266 14.635 ;
     RECT  5.004 14.381 5.994 14.635 ;
     RECT  6.768 14.521 70.722 14.639 ;
     RECT  1.728 14.635 5.994 14.675 ;
     RECT  6.768 14.639 16.722 14.819 ;
     RECT  17.46 14.639 70.722 14.819 ;
     RECT  0.036 14.189 0.126 14.957 ;
     RECT  17.46 14.819 55.674 15.053 ;
     RECT  2.34 14.675 5.994 15.403 ;
     RECT  2.304 15.403 5.994 15.421 ;
     RECT  6.984 14.819 16.722 15.451 ;
     RECT  17.46 15.053 55.53 15.451 ;
     RECT  56.415 14.819 70.722 15.691 ;
     RECT  2.304 15.421 6.21 15.755 ;
     RECT  4.68 15.755 6.21 15.787 ;
     RECT  6.984 15.451 55.53 15.787 ;
     RECT  4.68 15.787 55.53 15.871 ;
     RECT  56.268 15.691 70.722 15.871 ;
     RECT  2.304 15.755 2.697 16.295 ;
     RECT  2.34 16.295 2.697 16.501 ;
     RECT  3.528 15.755 3.618 16.501 ;
     RECT  4.68 15.871 70.758 16.501 ;
     RECT  2.34 16.501 3.618 16.541 ;
     RECT  0.036 14.957 0.054 16.565 ;
     RECT  71.568 16.681 71.586 16.871 ;
     RECT  4.68 16.501 70.83 17.077 ;
     RECT  72.615 2.413 72.897 17.455 ;
     RECT  2.415 16.541 3.618 17.491 ;
     RECT  71.928 17.455 72.897 17.609 ;
     RECT  2.415 17.491 3.654 17.851 ;
     RECT  4.68 17.077 71.01 17.851 ;
     RECT  2.415 17.851 71.01 18.221 ;
     RECT  2.415 18.221 3.618 18.535 ;
     RECT  4.68 18.221 71.01 18.841 ;
     RECT  4.68 18.841 71.19 18.959 ;
     RECT  4.68 18.959 71.082 19.139 ;
     RECT  2.304 18.535 3.618 19.265 ;
     RECT  4.68 19.139 70.794 19.435 ;
     RECT  4.644 19.435 70.794 20.191 ;
     RECT  4.644 20.191 71.01 20.461 ;
     RECT  4.644 20.461 71.19 20.551 ;
     RECT  2.376 19.265 3.618 20.615 ;
     RECT  4.572 20.551 71.19 20.731 ;
     RECT  3.6 20.615 3.618 20.92 ;
     RECT  4.5 20.731 71.19 20.92 ;
     RECT  2.376 20.615 2.826 20.965 ;
     RECT  3.6 20.92 71.19 21.001 ;
     RECT  72.615 17.609 72.897 21.001 ;
     RECT  0.108 20.971 0.126 21.101 ;
     RECT  3.6 21.001 72.897 21.191 ;
     RECT  2.304 20.965 2.826 21.505 ;
     RECT  3.6 21.191 71.226 21.505 ;
     RECT  2.304 21.505 71.226 21.547 ;
     RECT  2.232 21.547 71.226 21.965 ;
     RECT  2.268 21.965 71.226 21.973 ;
     RECT  2.268 21.973 71.334 22.045 ;
     RECT  72.615 21.191 72.897 22.045 ;
     RECT  0.144 22.12 0.162 22.126 ;
     RECT  2.268 22.045 72.897 22.199 ;
     RECT  0.072 22.126 0.162 22.267 ;
     RECT  0.072 22.267 0.198 22.411 ;
     RECT  2.268 22.199 71.586 23.161 ;
     RECT  72.396 22.199 72.897 23.161 ;
     RECT  0.072 22.411 0.342 23.885 ;
     RECT  2.268 23.161 72.897 24.125 ;
     RECT  2.304 24.125 72.897 24.629 ;
     RECT  4.5 24.629 72.897 25.051 ;
     RECT  4.5 25.051 73.062 25.321 ;
     RECT  4.5 25.321 73.278 25.439 ;
     RECT  2.304 24.629 3.762 25.475 ;
     RECT  4.5 25.439 72.954 25.619 ;
     RECT  2.34 25.475 3.762 25.861 ;
     RECT  4.5 25.619 72.897 25.861 ;
     RECT  2.34 25.861 72.897 26.203 ;
     RECT  2.304 26.203 72.897 26.285 ;
     RECT  0.072 23.885 0.234 26.671 ;
     RECT  2.415 26.285 72.897 26.671 ;
     RECT  0.036 26.671 0.234 26.765 ;
     RECT  2.415 26.671 73.206 26.941 ;
     RECT  2.415 26.941 73.746 27.059 ;
     RECT  2.415 27.059 73.026 27.905 ;
     RECT  4.356 27.905 73.026 28.021 ;
     RECT  4.356 28.021 73.35 28.139 ;
     RECT  2.415 27.905 3.582 28.175 ;
     RECT  4.356 28.139 73.278 28.715 ;
     RECT  0.036 26.765 0.126 29.255 ;
     RECT  4.5 28.715 73.278 29.641 ;
     RECT  4.5 29.641 73.314 29.759 ;
     RECT  4.5 29.759 73.098 30.221 ;
     RECT  5.328 30.221 73.098 30.569 ;
     RECT  0.036 29.255 0.054 30.875 ;
     RECT  5.364 30.569 73.098 30.991 ;
     RECT  5.364 30.991 73.422 31.217 ;
     RECT  2.415 28.175 3.438 31.379 ;
     RECT  4.5 30.221 4.518 31.495 ;
     RECT  5.544 31.217 73.422 31.801 ;
     RECT  5.544 31.801 73.746 31.919 ;
     RECT  4.5 31.495 4.59 31.963 ;
     RECT  4.356 31.963 4.59 31.991 ;
     RECT  5.544 31.919 73.17 32.071 ;
     RECT  5.328 32.071 73.17 32.225 ;
     RECT  5.652 32.225 73.17 32.773 ;
     RECT  78.015 2.413 78.297 32.872 ;
     RECT  3.42 31.379 3.438 32.873 ;
     RECT  5.652 32.773 73.206 32.881 ;
     RECT  77.904 32.872 78.297 32.909 ;
     RECT  5.652 32.881 73.422 32.999 ;
     RECT  88.452 32.971 88.47 33.007 ;
     RECT  5.652 32.999 73.35 33.035 ;
     RECT  5.652 33.035 72.897 33.067 ;
     RECT  4.356 31.991 4.374 33.305 ;
     RECT  5.436 33.067 72.897 33.421 ;
     RECT  85.896 33.421 85.914 33.539 ;
     RECT  87.192 33.259 87.21 33.611 ;
     RECT  4.572 33.421 72.897 33.781 ;
     RECT  88.452 33.007 88.542 33.845 ;
     RECT  4.572 33.781 72.954 33.853 ;
     RECT  4.572 33.853 73.278 33.953 ;
     RECT  5.364 33.953 73.278 33.961 ;
     RECT  84.996 33.883 85.014 33.989 ;
     RECT  4.572 33.953 4.59 34.079 ;
     RECT  5.364 33.961 73.494 34.079 ;
     RECT  5.364 34.079 73.242 34.619 ;
     RECT  5.364 34.619 73.098 34.771 ;
     RECT  5.328 34.771 73.098 35.195 ;
     RECT  5.544 35.195 73.098 35.707 ;
     RECT  5.544 35.707 73.134 35.851 ;
     RECT  5.544 35.851 73.206 35.969 ;
     RECT  5.544 35.969 73.17 36.121 ;
     RECT  4.968 36.121 73.17 36.509 ;
     RECT  5.184 36.509 73.17 36.931 ;
     RECT  5.184 36.931 73.89 36.959 ;
     RECT  5.652 36.959 73.89 37.049 ;
     RECT  78.015 32.909 78.297 37.291 ;
     RECT  88.524 33.845 88.542 37.319 ;
     RECT  78.015 37.291 78.822 37.463 ;
     RECT  74.736 37.327 74.754 37.499 ;
     RECT  5.652 37.049 73.098 38.011 ;
     RECT  5.652 38.011 73.206 38.129 ;
     RECT  5.652 38.129 73.098 39.325 ;
     RECT  5.472 39.325 73.098 39.917 ;
     RECT  5.652 39.917 73.098 40.531 ;
     RECT  5.652 40.531 73.206 40.567 ;
     RECT  5.652 40.567 73.242 40.603 ;
     RECT  5.652 40.603 73.458 40.711 ;
     RECT  5.652 40.711 73.638 40.981 ;
     RECT  5.652 40.981 73.962 41.279 ;
     RECT  5.652 41.279 68.994 41.369 ;
     RECT  69.768 41.279 73.962 41.485 ;
     RECT  5.652 41.369 68.778 41.611 ;
     RECT  5.22 41.611 68.778 41.675 ;
     RECT  69.768 41.485 74.034 41.711 ;
     RECT  4.212 42.061 4.23 42.151 ;
     RECT  3.852 42.151 4.23 42.179 ;
     RECT  5.652 41.675 68.778 42.179 ;
     RECT  2.415 31.379 2.697 42.181 ;
     RECT  6.408 42.179 68.778 42.223 ;
     RECT  6.408 42.223 69.102 42.457 ;
     RECT  69.912 41.711 73.638 42.457 ;
     RECT  2.304 42.181 2.697 42.601 ;
     RECT  6.408 42.457 73.638 42.601 ;
     RECT  6.408 42.601 74.322 42.719 ;
     RECT  5.652 42.179 5.67 42.955 ;
     RECT  6.408 42.719 73.674 42.955 ;
     RECT  5.652 42.955 73.674 42.989 ;
     RECT  5.76 42.989 73.674 43.259 ;
     RECT  0.108 42.565 0.126 43.303 ;
     RECT  3.852 42.179 3.87 43.373 ;
     RECT  2.304 42.601 2.79 43.411 ;
     RECT  0.108 43.303 0.558 43.565 ;
     RECT  4.356 43.771 4.374 43.807 ;
     RECT  4.356 43.807 5.022 43.843 ;
     RECT  5.76 43.259 73.242 43.843 ;
     RECT  0.144 43.565 0.558 43.853 ;
     RECT  4.356 43.843 73.242 43.853 ;
     RECT  2.304 43.411 2.898 43.951 ;
     RECT  4.356 43.853 21.834 44.105 ;
     RECT  0.144 43.853 0.162 44.141 ;
     RECT  2.304 43.951 3.258 44.299 ;
     RECT  2.268 44.299 3.258 44.375 ;
     RECT  2.304 44.375 3.258 44.383 ;
     RECT  4.356 44.105 15.174 44.383 ;
     RECT  22.68 43.853 73.242 44.447 ;
     RECT  23.112 44.447 73.242 44.609 ;
     RECT  15.948 44.105 21.834 44.617 ;
     RECT  2.304 44.383 15.174 44.789 ;
     RECT  2.304 44.789 14.994 44.915 ;
     RECT  0.54 44.761 0.558 44.995 ;
     RECT  2.304 44.915 3.726 45.023 ;
     RECT  4.644 44.915 14.994 45.023 ;
     RECT  15.948 44.617 22.302 45.031 ;
     RECT  0.036 44.995 0.558 45.101 ;
     RECT  4.824 45.023 14.994 45.185 ;
     RECT  23.22 44.609 73.242 45.301 ;
     RECT  23.22 45.301 73.278 45.391 ;
     RECT  15.732 45.031 22.302 45.403 ;
     RECT  23.076 45.391 73.278 45.403 ;
     RECT  15.732 45.403 73.278 45.419 ;
     RECT  5.256 45.185 14.994 45.535 ;
     RECT  15.732 45.419 72.918 45.535 ;
     RECT  0.036 45.101 0.198 45.725 ;
     RECT  2.304 45.023 3.654 45.805 ;
     RECT  5.256 45.535 72.918 45.869 ;
     RECT  70.704 45.869 72.918 45.959 ;
     RECT  2.268 45.805 3.87 45.995 ;
     RECT  5.256 45.869 69.966 46.229 ;
     RECT  2.304 45.995 3.87 46.499 ;
     RECT  70.704 45.959 72.897 46.615 ;
     RECT  3.852 46.499 3.87 46.769 ;
     RECT  5.256 46.229 69.426 46.769 ;
     RECT  70.632 46.615 72.897 46.777 ;
     RECT  2.304 46.499 2.697 46.805 ;
     RECT  5.76 46.769 69.426 47.275 ;
     RECT  4.86 46.921 4.878 47.309 ;
     RECT  5.76 47.275 69.786 47.461 ;
     RECT  70.632 46.777 73.242 47.461 ;
     RECT  5.76 47.461 73.242 47.579 ;
     RECT  5.832 47.579 73.242 49.171 ;
     RECT  5.544 49.171 73.242 49.435 ;
     RECT  5.4 49.435 73.242 49.475 ;
     RECT  5.616 49.475 73.242 49.549 ;
     RECT  5.616 49.549 73.35 50.053 ;
     RECT  5.616 50.053 73.71 50.153 ;
     RECT  74.52 50.161 74.538 50.279 ;
     RECT  5.616 50.153 70.506 50.359 ;
     RECT  71.244 50.153 73.71 50.593 ;
     RECT  4.536 50.107 4.554 50.701 ;
     RECT  5.472 50.359 70.506 50.701 ;
     RECT  3.996 50.701 4.554 50.729 ;
     RECT  5.4 50.701 70.506 51.133 ;
     RECT  4.896 51.133 70.506 51.241 ;
     RECT  71.244 50.593 73.818 51.241 ;
     RECT  3.996 50.729 4.014 51.511 ;
     RECT  4.896 51.241 73.818 51.511 ;
     RECT  3.996 51.511 4.158 51.629 ;
     RECT  4.896 51.511 74.43 51.629 ;
     RECT  4.896 51.629 74.214 52.459 ;
     RECT  4.464 52.459 74.214 52.825 ;
     RECT  75.24 52.753 75.258 52.825 ;
     RECT  2.415 46.805 2.697 52.843 ;
     RECT  4.464 52.825 75.258 52.979 ;
     RECT  2.415 52.843 2.826 52.987 ;
     RECT  2.415 52.987 3.186 53.035 ;
     RECT  2.415 53.035 3.726 53.095 ;
     RECT  2.376 53.095 3.726 53.131 ;
     RECT  4.716 52.979 75.258 53.519 ;
     RECT  2.304 53.131 3.726 53.555 ;
     RECT  2.415 53.555 3.726 53.563 ;
     RECT  4.824 53.519 75.258 53.597 ;
     RECT  4.896 53.597 75.258 53.797 ;
     RECT  2.415 53.563 3.906 54.125 ;
     RECT  3.888 54.125 3.906 54.139 ;
     RECT  4.896 53.797 75.546 54.211 ;
     RECT  4.896 54.211 75.762 54.301 ;
     RECT  78.015 37.463 78.297 54.409 ;
     RECT  3.888 54.139 4.086 54.481 ;
     RECT  4.896 54.301 76.482 54.481 ;
     RECT  3.888 54.481 76.482 54.599 ;
     RECT  3.888 54.599 4.086 54.635 ;
     RECT  4.896 54.599 76.482 54.643 ;
     RECT  4.896 54.643 76.518 54.913 ;
     RECT  77.724 54.409 78.297 54.913 ;
     RECT  4.896 54.913 78.297 55.679 ;
     RECT  4.896 55.679 74.898 55.787 ;
     RECT  4.896 55.787 74.79 55.921 ;
     RECT  75.744 55.679 78.297 56.255 ;
     RECT  3.888 54.635 3.906 56.335 ;
     RECT  4.716 55.921 74.79 56.335 ;
     RECT  3.888 56.335 74.79 56.491 ;
     RECT  3.6 56.491 74.79 56.533 ;
     RECT  3.6 56.533 74.934 56.641 ;
     RECT  3.528 56.641 74.934 56.731 ;
     RECT  3.528 56.731 75.042 57.181 ;
     RECT  75.78 56.255 78.297 57.181 ;
     RECT  2.415 54.125 2.697 57.415 ;
     RECT  3.528 57.181 78.297 57.415 ;
     RECT  2.415 57.415 78.297 57.685 ;
     RECT  2.415 57.685 78.318 57.839 ;
     RECT  2.415 57.839 78.297 59.275 ;
     RECT  2.376 59.275 78.297 59.575 ;
     RECT  2.304 59.575 78.297 59.645 ;
     RECT  0.036 45.725 0.054 59.737 ;
     RECT  2.415 59.645 78.297 60.385 ;
     RECT  2.415 60.385 78.426 60.925 ;
     RECT  2.376 60.925 78.426 61.151 ;
     RECT  2.376 61.151 78.297 61.195 ;
     RECT  0.036 59.737 0.09 61.393 ;
     RECT  2.304 61.195 78.297 61.619 ;
     RECT  0.036 61.393 0.306 62.189 ;
     RECT  19.692 61.619 78.297 62.581 ;
     RECT  2.304 61.619 18.897 62.671 ;
     RECT  19.62 62.581 78.75 62.671 ;
     RECT  2.304 62.671 78.75 62.699 ;
     RECT  2.304 62.699 78.297 63.115 ;
     RECT  2.268 63.115 78.297 63.211 ;
     RECT  2.232 63.211 78.297 63.275 ;
     RECT  0.072 62.189 0.306 63.691 ;
     RECT  2.268 63.275 78.297 64.253 ;
     RECT  0.072 63.691 0.342 64.363 ;
     RECT  0.072 64.363 0.846 65.245 ;
     RECT  2.304 64.253 78.297 66.245 ;
     RECT  2.34 66.245 78.297 66.659 ;
     RECT  0.036 65.245 0.846 66.749 ;
     RECT  2.415 66.659 78.297 66.901 ;
     RECT  2.415 66.901 78.498 67.091 ;
     RECT  2.415 67.091 78.297 67.675 ;
     RECT  2.376 67.675 78.297 68.009 ;
     RECT  77.184 68.009 78.297 68.251 ;
     RECT  77.184 68.251 78.426 68.369 ;
     RECT  2.376 68.009 76.41 68.485 ;
     RECT  77.184 68.369 78.39 68.639 ;
     RECT  2.268 68.485 76.41 68.791 ;
     RECT  77.184 68.639 78.297 68.791 ;
     RECT  2.268 68.791 78.297 69.331 ;
     RECT  0.072 66.749 0.846 69.791 ;
     RECT  2.232 69.331 78.297 69.835 ;
     RECT  1.728 69.835 78.297 70.681 ;
     RECT  1.728 70.681 78.498 70.799 ;
     RECT  1.728 70.799 78.297 71.069 ;
     RECT  0.072 69.791 0.594 71.105 ;
     RECT  0.108 71.105 0.594 71.371 ;
     RECT  1.728 71.069 3.402 71.371 ;
     RECT  0.108 71.371 3.402 71.887 ;
     RECT  0.108 71.887 3.654 71.915 ;
     RECT  4.392 71.069 78.297 72.301 ;
     RECT  2.232 71.915 3.654 72.331 ;
     RECT  4.392 72.301 78.318 72.331 ;
     RECT  2.232 72.331 78.318 72.419 ;
     RECT  2.232 72.419 78.297 72.455 ;
     RECT  0.108 71.915 1.134 72.797 ;
     RECT  2.232 72.455 77.13 72.995 ;
     RECT  2.268 72.995 77.13 73.031 ;
     RECT  0.108 72.797 0.594 73.067 ;
     RECT  2.268 73.031 76.986 73.229 ;
     RECT  2.268 73.229 76.014 73.265 ;
     RECT  2.34 73.265 76.014 73.499 ;
     RECT  2.34 73.499 75.978 73.517 ;
     RECT  2.34 73.517 75.582 73.535 ;
     RECT  0.576 73.067 0.594 73.805 ;
     RECT  75.564 73.535 75.582 73.841 ;
     RECT  2.415 73.535 74.718 74.039 ;
     RECT  2.415 74.039 73.062 74.147 ;
     RECT  2.415 74.147 3.582 74.669 ;
     RECT  4.392 74.147 73.062 74.993 ;
     RECT  4.428 74.993 73.062 75.029 ;
     RECT  73.908 74.039 74.718 75.227 ;
     RECT  2.415 74.669 3.294 75.659 ;
     RECT  74.196 75.227 74.718 75.659 ;
     RECT  4.788 75.029 73.062 75.811 ;
     RECT  4.788 75.811 73.098 75.929 ;
     RECT  4.788 75.929 73.062 76.073 ;
     RECT  3.996 76.058 4.014 76.081 ;
     RECT  4.788 76.073 72.897 76.081 ;
     RECT  2.415 75.659 3.222 76.621 ;
     RECT  3.996 76.081 72.897 76.621 ;
     RECT  2.415 76.621 72.897 76.973 ;
     RECT  2.415 76.973 3.51 77.279 ;
     RECT  4.572 76.973 72.897 77.387 ;
     RECT  4.752 77.387 72.897 78.653 ;
     RECT  4.752 78.653 71.838 78.665 ;
     RECT  4.788 78.665 71.838 79.709 ;
     RECT  18.54 79.709 71.838 79.745 ;
     RECT  4.788 79.709 17.766 80.015 ;
     RECT  4.356 80.095 4.374 80.141 ;
     RECT  18.54 79.745 71.802 80.249 ;
     RECT  5.364 80.015 17.766 80.491 ;
     RECT  18.54 80.249 71.118 80.491 ;
     RECT  5.364 80.491 71.118 80.519 ;
     RECT  5.364 80.519 70.362 81.059 ;
     RECT  5.364 81.059 69.246 81.095 ;
     RECT  70.056 81.059 70.362 81.095 ;
     RECT  5.364 81.095 68.418 81.205 ;
     RECT  71.1 80.519 71.118 81.211 ;
     RECT  5.076 81.205 68.418 81.245 ;
     RECT  70.092 81.095 70.362 81.329 ;
     RECT  71.1 81.211 71.154 81.329 ;
     RECT  70.092 81.329 70.182 81.365 ;
     RECT  5.364 81.245 68.418 81.401 ;
     RECT  71.1 81.329 71.118 81.473 ;
     RECT  70.092 81.365 70.11 81.509 ;
     RECT  5.364 81.401 67.806 81.779 ;
     RECT  5.364 81.779 67.734 82.409 ;
     RECT  5.364 82.409 66.402 82.525 ;
     RECT  4.86 82.525 66.402 82.553 ;
     RECT  67.215 82.409 67.734 82.553 ;
     RECT  67.215 82.553 67.59 82.589 ;
     RECT  5.688 82.553 66.402 82.787 ;
     RECT  5.688 82.787 6.102 82.823 ;
     RECT  6.012 82.823 6.102 82.859 ;
     RECT  4.86 82.553 4.878 83.021 ;
     RECT  6.084 82.859 6.102 83.021 ;
     RECT  6.876 82.787 66.402 83.021 ;
     RECT  6.876 83.021 7.038 83.219 ;
     RECT  7.776 83.021 66.402 83.219 ;
     RECT  7.815 83.219 66.402 83.911 ;
     RECT  67.215 82.589 67.497 83.911 ;
     RECT  7.815 83.911 67.497 84.065 ;
     RECT  7.815 84.065 66.186 84.335 ;
     RECT  9.54 84.335 66.186 84.371 ;
     RECT  9.684 84.371 66.186 84.479 ;
     RECT  9.684 84.479 59.958 84.569 ;
     RECT  60.984 84.479 66.186 84.713 ;
     RECT  9.936 84.569 59.958 84.839 ;
     RECT  11.628 84.839 11.646 84.875 ;
     RECT  61.056 84.713 66.186 84.875 ;
     RECT  9.936 84.839 10.602 84.911 ;
     RECT  12.528 84.839 59.958 84.911 ;
     RECT  16.164 84.911 59.958 84.941 ;
     RECT  61.596 84.875 66.186 84.991 ;
     RECT  67.215 84.065 67.497 84.991 ;
     RECT  10.584 84.911 10.602 85.019 ;
     RECT  12.528 84.911 15.426 85.109 ;
     RECT  16.164 84.941 59.886 85.109 ;
     RECT  17.244 85.109 17.73 85.217 ;
     RECT  15.408 85.109 15.426 85.289 ;
     RECT  61.596 84.991 67.497 85.451 ;
     RECT  61.596 85.451 62.658 85.517 ;
     RECT  18.54 85.109 59.886 85.523 ;
     RECT  69.228 81.095 69.246 85.559 ;
     RECT  16.164 85.109 16.182 85.649 ;
     RECT  17.496 85.217 17.73 85.649 ;
     RECT  18.54 85.523 21.33 85.649 ;
     RECT  63.54 85.451 67.497 85.649 ;
     RECT  22.068 85.523 59.886 85.685 ;
     RECT  53.928 85.685 59.886 85.729 ;
     RECT  17.496 85.649 17.514 85.757 ;
     RECT  22.068 85.685 53.118 85.793 ;
     RECT  22.068 85.793 22.626 85.805 ;
     RECT  14.616 85.109 14.634 85.829 ;
     RECT  18.615 85.649 21.33 85.919 ;
     RECT  22.068 85.805 22.266 85.919 ;
     RECT  24.015 85.793 53.118 85.919 ;
     RECT  53.928 85.729 60.102 85.919 ;
     RECT  61.812 85.517 62.658 85.919 ;
     RECT  64.98 85.649 67.497 85.919 ;
     RECT  27.936 85.919 53.118 85.949 ;
     RECT  18.615 85.919 19.53 85.955 ;
     RECT  20.664 85.919 21.33 85.955 ;
     RECT  24.015 85.919 24.822 85.955 ;
     RECT  29.304 85.949 53.118 85.955 ;
     RECT  53.928 85.919 59.994 85.955 ;
     RECT  61.812 85.919 62.514 85.955 ;
     RECT  53.928 85.955 59.67 86.063 ;
     RECT  2.415 77.279 2.697 86.147 ;
     RECT  7.815 84.335 8.097 86.147 ;
     RECT  13.215 85.109 13.497 86.147 ;
     RECT  18.615 85.955 18.897 86.147 ;
     RECT  24.015 85.955 24.297 86.147 ;
     RECT  65.988 85.919 67.497 86.147 ;
     RECT  72.615 78.653 72.897 86.147 ;
     RECT  78.015 72.455 78.297 86.147 ;
     RECT  83.415 2.413 83.697 86.147 ;
     RECT  20.664 85.955 21.186 86.189 ;
     RECT  27.936 85.949 28.53 86.189 ;
     RECT  61.812 85.955 62.37 86.189 ;
     RECT  63.54 85.649 63.738 86.189 ;
     RECT  64.98 85.919 65.142 86.189 ;
     RECT  20.664 86.189 20.682 86.225 ;
     RECT  25.632 85.919 26.982 86.225 ;
     RECT  27.936 86.189 28.386 86.225 ;
     RECT  29.304 85.955 53.082 86.225 ;
     RECT  53.928 86.063 54.594 86.225 ;
     RECT  55.368 86.063 58.23 86.225 ;
     RECT  58.968 86.063 59.67 86.225 ;
     RECT  64.98 86.189 64.998 86.225 ;
     RECT  65.988 86.147 67.305 86.225 ;
     RECT  27.936 86.225 27.954 86.261 ;
     RECT  26.244 86.225 26.982 86.297 ;
     RECT  30.636 86.225 53.082 86.297 ;
     RECT  54.036 86.225 54.594 86.297 ;
     RECT  55.656 86.225 58.23 86.297 ;
     RECT  30.78 86.297 34.002 86.333 ;
     RECT  55.656 86.297 56.505 86.333 ;
     RECT  61.815 86.189 62.37 86.333 ;
     RECT  34.815 86.297 53.082 86.369 ;
     RECT  55.656 86.333 55.674 86.369 ;
     RECT  58.14 86.297 58.23 86.369 ;
     RECT  59.22 86.225 59.67 86.369 ;
     RECT  63.72 86.189 63.738 86.369 ;
     RECT  2.415 86.147 2.505 86.417 ;
     RECT  7.815 86.147 7.905 86.417 ;
     RECT  13.215 86.147 13.305 86.417 ;
     RECT  18.615 86.147 18.705 86.417 ;
     RECT  24.015 86.147 24.105 86.417 ;
     RECT  29.415 86.225 29.505 86.417 ;
     RECT  34.815 86.369 47.97 86.417 ;
     RECT  48.708 86.369 53.082 86.417 ;
     RECT  56.415 86.333 56.505 86.417 ;
     RECT  61.815 86.333 61.905 86.417 ;
     RECT  67.215 86.225 67.305 86.417 ;
     RECT  72.615 86.147 72.705 86.417 ;
     RECT  78.015 86.147 78.105 86.417 ;
     RECT  83.415 86.147 83.505 86.417 ;
     RECT  48.708 86.417 50.922 86.429 ;
     RECT  30.78 86.333 31.194 86.459 ;
     RECT  34.956 86.417 47.97 86.459 ;
     RECT  54.036 86.297 54.486 86.459 ;
     RECT  59.652 86.369 59.67 86.459 ;
     RECT  48.744 86.429 50.922 86.477 ;
     RECT  33.984 86.333 34.002 86.495 ;
     RECT  58.212 86.369 58.23 86.525 ;
     RECT  30.78 86.459 30.798 86.531 ;
     RECT  54.036 86.459 54.342 86.573 ;
     RECT  32.256 86.333 33.246 86.603 ;
     RECT  48.744 86.477 50.778 86.621 ;
     RECT  51.732 86.417 53.082 86.621 ;
     RECT  34.992 86.459 47.97 86.639 ;
     RECT  35.712 86.639 47.97 86.669 ;
     RECT  54.324 86.573 54.342 86.909 ;
     RECT  48.744 86.621 50.238 87.197 ;
     RECT  35.712 86.669 47.61 87.224 ;
     RECT  35.712 87.224 42.354 87.245 ;
     RECT  43.092 87.224 47.61 87.245 ;
     RECT  51.732 86.621 52.65 87.485 ;
     RECT  51.732 87.485 52.326 87.533 ;
     RECT  48.996 87.197 50.238 87.581 ;
     RECT  43.416 87.245 47.61 87.821 ;
     RECT  37.224 87.245 42.354 87.869 ;
     RECT  35.712 87.245 36.45 87.917 ;
     RECT  36.432 87.917 36.45 88.013 ;
     RECT  39.852 87.869 42.354 88.253 ;
     RECT  46.44 87.821 47.286 88.301 ;
     RECT  48.996 87.581 49.986 88.301 ;
     RECT  39.852 88.253 42.318 88.349 ;
     RECT  49.356 88.301 49.986 88.349 ;
     RECT  39.852 88.349 41.886 88.397 ;
     RECT  43.668 87.821 45.342 88.397 ;
     RECT  49.788 88.349 49.986 88.397 ;
     RECT  37.224 87.869 39.078 88.445 ;
     RECT  39.852 88.397 41.13 88.445 ;
     RECT  41.868 88.397 41.886 88.445 ;
     RECT  43.74 88.397 44.334 88.445 ;
     RECT  45.324 88.397 45.342 88.445 ;
     RECT  46.44 88.301 47.214 88.445 ;
     RECT  49.968 88.397 49.986 88.445 ;
     RECT  32.904 86.603 33.246 88.493 ;
     RECT  37.476 88.445 38.034 88.493 ;
     RECT  39.996 88.445 40.374 88.493 ;
     RECT  32.904 88.493 32.922 88.541 ;
     RECT  37.584 88.493 37.602 88.541 ;
     RECT  39.996 88.493 40.014 88.541 ;
     RECT  47.16 88.445 47.178 88.541 ;
     RECT  48.06 88.363 48.078 88.541 ;
     RECT  52.308 87.533 52.326 88.541 ;
    LAYER M4 ;
     RECT  0.025 62.16 0.06 62.184 ;
     RECT  0.06 11.856 0.097 14.856 ;
     RECT  0.06 21.072 0.097 24.072 ;
     RECT  0.097 11.76 0.133 14.952 ;
     RECT  0.06 62.16 0.133 65.544 ;
     RECT  0.06 69.456 0.133 72.456 ;
     RECT  0.097 20.976 0.181 24.072 ;
     RECT  0.133 69.456 0.181 72.984 ;
     RECT  0.133 11.376 0.229 15.432 ;
     RECT  0.097 26.736 0.229 26.76 ;
     RECT  0.229 26.208 0.245 26.76 ;
     RECT  0.229 11.376 0.277 16.008 ;
     RECT  0.133 25.104 0.373 25.128 ;
     RECT  0.133 61.44 0.419 66.696 ;
     RECT  0.181 20.976 0.517 24.12 ;
     RECT  0.373 25.104 0.517 25.224 ;
     RECT  0.277 11.376 2.285 16.104 ;
     RECT  0.517 20.976 2.285 25.224 ;
     RECT  0.245 26.208 2.285 26.232 ;
     RECT  0.133 18.576 2.293 18.6 ;
     RECT  2.285 20.976 2.293 26.232 ;
     RECT  0.06 53.136 2.293 53.256 ;
     RECT  0.181 59.616 2.293 59.64 ;
     RECT  2.285 11.376 2.408 16.536 ;
     RECT  2.293 18.576 2.408 18.84 ;
     RECT  2.293 20.976 2.408 26.808 ;
     RECT  0.277 42.192 2.408 42.216 ;
     RECT  0.06 43.344 2.408 46.344 ;
     RECT  2.293 53.136 2.408 54.12 ;
     RECT  2.293 59.28 2.408 59.64 ;
     RECT  0.419 61.44 2.408 66.168 ;
     RECT  0.181 69.456 2.408 73.08 ;
     RECT  2.408 2.148 2.512 86.412 ;
     RECT  2.512 2.418 2.704 86.142 ;
     RECT  2.704 20.688 2.801 24.648 ;
     RECT  2.704 61.44 2.819 66.408 ;
     RECT  2.704 18.24 2.845 18.264 ;
     RECT  2.704 25.632 2.845 28.296 ;
     RECT  2.704 11.76 2.867 15.432 ;
     RECT  2.845 26.448 2.867 28.296 ;
     RECT  2.704 70.32 2.873 72.984 ;
     RECT  2.704 58.128 2.905 58.152 ;
     RECT  2.873 70.32 3.125 72.504 ;
     RECT  2.801 20.688 3.233 23.88 ;
     RECT  3.125 70.32 3.395 71.112 ;
     RECT  2.704 43.344 3.521 46.056 ;
     RECT  2.704 74.64 3.539 75.384 ;
     RECT  3.539 74.64 3.593 74.664 ;
     RECT  2.867 26.64 3.665 28.296 ;
     RECT  2.704 67.392 3.665 69.336 ;
     RECT  3.521 43.344 3.881 45.72 ;
     RECT  2.704 52.848 3.973 54.12 ;
     RECT  2.704 76.944 3.985 76.968 ;
     RECT  2.819 61.44 4.021 61.56 ;
     RECT  2.819 62.544 4.021 65.544 ;
     RECT  3.395 70.32 4.025 70.728 ;
     RECT  2.704 59.712 4.049 59.832 ;
     RECT  3.665 67.392 4.093 67.56 ;
     RECT  3.973 52.848 4.097 54.168 ;
     RECT  3.665 68.784 4.129 69.336 ;
     RECT  4.049 59.712 4.165 60.312 ;
     RECT  4.021 61.44 4.165 65.544 ;
     RECT  4.165 59.712 4.277 65.544 ;
     RECT  4.277 63.6 4.345 65.544 ;
     RECT  4.093 67.104 4.345 67.56 ;
     RECT  3.233 20.688 4.412 23.832 ;
     RECT  4.097 52.848 4.453 53.592 ;
     RECT  4.412 20.688 4.499 24.6 ;
     RECT  4.453 49.536 4.525 49.56 ;
     RECT  4.277 59.712 4.549 62.568 ;
     RECT  4.508 58.032 4.595 58.056 ;
     RECT  2.704 56.496 4.601 56.856 ;
     RECT  2.867 11.76 4.709 15 ;
     RECT  4.549 78.096 4.781 78.12 ;
     RECT  3.665 26.64 4.817 26.76 ;
     RECT  3.881 44.16 4.849 45.72 ;
     RECT  4.345 63.6 4.993 67.56 ;
     RECT  4.129 68.784 4.993 70.056 ;
     RECT  2.704 29.28 5.065 29.304 ;
     RECT  4.345 80.112 5.132 80.136 ;
     RECT  5.077 16.656 5.164 16.68 ;
     RECT  4.957 36.48 5.173 36.504 ;
     RECT  5.173 36.48 5.213 36.936 ;
     RECT  5.132 79.152 5.219 80.136 ;
     RECT  3.985 18.192 5.279 18.216 ;
     RECT  4.633 19.44 5.279 19.464 ;
     RECT  4.453 52.464 5.281 53.592 ;
     RECT  5.279 18.192 5.317 19.464 ;
     RECT  4.499 20.688 5.317 24.072 ;
     RECT  4.817 26.64 5.317 26.664 ;
     RECT  5.065 29.28 5.357 30.216 ;
     RECT  4.525 49.536 5.389 50.136 ;
     RECT  4.345 33.264 5.425 33.288 ;
     RECT  4.549 59.04 5.425 62.568 ;
     RECT  5.065 81.216 5.425 81.24 ;
     RECT  3.985 76.08 5.501 76.968 ;
     RECT  5.219 79.728 5.501 80.136 ;
     RECT  5.501 76.32 5.509 76.968 ;
     RECT  4.237 74.064 5.533 74.088 ;
     RECT  4.993 63.6 5.569 70.056 ;
     RECT  5.509 76.32 5.596 77.16 ;
     RECT  5.533 74.064 5.617 74.136 ;
     RECT  5.389 49.44 5.645 50.136 ;
     RECT  4.849 47.28 5.653 47.304 ;
     RECT  5.317 26.592 5.677 26.664 ;
     RECT  5.281 52.416 5.677 53.592 ;
     RECT  4.601 56.832 5.677 56.856 ;
     RECT  5.425 58.128 5.677 62.568 ;
     RECT  5.645 49.44 5.699 49.56 ;
     RECT  5.461 39.888 5.701 39.912 ;
     RECT  5.209 41.616 5.701 41.64 ;
     RECT  5.677 56.832 5.701 62.568 ;
     RECT  5.569 63.6 5.701 70.728 ;
     RECT  5.701 38.112 5.747 41.64 ;
     RECT  5.701 56.832 5.747 70.728 ;
     RECT  4.849 44.064 5.749 45.72 ;
     RECT  5.677 51.648 5.749 53.592 ;
     RECT  5.747 40.464 5.845 41.64 ;
     RECT  5.749 44.064 5.845 46.248 ;
     RECT  5.653 47.28 5.857 47.88 ;
     RECT  5.747 38.112 5.861 39.096 ;
     RECT  5.845 40.464 5.861 46.248 ;
     RECT  5.749 51.6 5.893 53.592 ;
     RECT  5.677 26.016 5.929 26.664 ;
     RECT  5.213 36.912 5.941 36.936 ;
     RECT  5.929 26.016 6.013 26.76 ;
     RECT  5.425 33.072 6.037 33.288 ;
     RECT  5.317 18.192 6.073 24.072 ;
     RECT  5.617 74.064 6.073 74.088 ;
     RECT  5.747 62.544 6.077 70.728 ;
     RECT  6.013 26.016 6.181 26.664 ;
     RECT  3.125 72.096 6.181 72.504 ;
     RECT  6.073 74.016 6.221 74.088 ;
     RECT  3.665 28.272 6.253 28.296 ;
     RECT  6.181 71.904 6.253 72.504 ;
     RECT  5.861 41.04 6.275 46.248 ;
     RECT  5.425 81.216 6.277 81.336 ;
     RECT  4.849 82.992 6.277 83.016 ;
     RECT  5.857 47.28 6.325 48.312 ;
     RECT  5.941 36.912 6.329 37.416 ;
     RECT  6.277 81.216 6.364 83.016 ;
     RECT  6.073 18.096 6.365 24.072 ;
     RECT  6.325 46.992 6.371 48.312 ;
     RECT  6.253 71.76 6.469 72.504 ;
     RECT  6.037 33.072 6.509 34.824 ;
     RECT  6.469 71.76 6.541 72.936 ;
     RECT  6.221 74.016 6.541 74.04 ;
     RECT  6.365 18.144 6.581 24.072 ;
     RECT  5.893 51.312 6.611 53.592 ;
     RECT  6.253 28.224 6.613 28.296 ;
     RECT  5.357 29.28 6.613 29.304 ;
     RECT  5.596 76.32 6.653 76.92 ;
     RECT  6.275 41.04 6.689 46.008 ;
     RECT  5.929 31.344 6.721 31.368 ;
     RECT  6.509 33.072 6.721 33.576 ;
     RECT  4.709 11.808 6.793 15 ;
     RECT  5.861 38.64 6.793 39.096 ;
     RECT  6.611 51.36 6.829 53.592 ;
     RECT  6.364 81.216 6.829 81.336 ;
     RECT  5.785 54.768 6.901 55.752 ;
     RECT  6.653 76.32 6.901 76.584 ;
     RECT  6.613 28.224 6.937 29.304 ;
     RECT  6.937 27.984 7.009 29.304 ;
     RECT  6.364 82.704 7.009 83.016 ;
     RECT  6.181 25.968 7.045 26.664 ;
     RECT  5.747 56.832 7.081 58.152 ;
     RECT  7.045 25.968 7.117 26.904 ;
     RECT  7.009 27.984 7.117 30.072 ;
     RECT  5.747 59.664 7.141 61.464 ;
     RECT  6.077 62.544 7.141 69.816 ;
     RECT  6.901 75.84 7.189 76.584 ;
     RECT  5.501 79.728 7.217 79.752 ;
     RECT  6.829 81.168 7.217 81.336 ;
     RECT  5.425 78.624 7.237 78.648 ;
     RECT  7.217 79.728 7.237 81.336 ;
     RECT  7.117 25.968 7.333 30.072 ;
     RECT  6.329 37.056 7.333 37.416 ;
     RECT  5.699 49.536 7.369 49.56 ;
     RECT  7.333 25.968 7.441 30.168 ;
     RECT  6.689 41.376 7.441 46.008 ;
     RECT  6.371 46.992 7.441 47.832 ;
     RECT  7.081 56.784 7.441 58.152 ;
     RECT  7.441 25.824 7.513 30.168 ;
     RECT  7.513 25.488 7.549 30.168 ;
     RECT  6.901 54.72 7.549 55.752 ;
     RECT  7.441 56.784 7.549 58.68 ;
     RECT  7.009 82.704 7.585 83.064 ;
     RECT  7.549 25.152 7.621 30.168 ;
     RECT  6.509 34.8 7.669 34.824 ;
     RECT  6.793 38.64 7.669 39.384 ;
     RECT  6.541 71.76 7.693 74.04 ;
     RECT  7.189 75.264 7.693 76.584 ;
     RECT  7.549 54.72 7.729 58.68 ;
     RECT  6.829 51.36 7.765 53.688 ;
     RECT  7.729 54.672 7.765 58.68 ;
     RECT  7.669 34.8 7.801 35.352 ;
     RECT  7.333 36.576 7.801 37.416 ;
     RECT  6.793 11.808 7.808 15.816 ;
     RECT  6.581 18.144 7.808 24.024 ;
     RECT  7.621 25.104 7.808 30.168 ;
     RECT  6.721 31.344 7.808 33.576 ;
     RECT  7.801 34.8 7.808 37.416 ;
     RECT  7.669 38.64 7.808 40.056 ;
     RECT  7.441 41.376 7.808 47.832 ;
     RECT  7.369 49.392 7.808 49.56 ;
     RECT  7.765 51.36 7.808 58.68 ;
     RECT  7.141 59.664 7.808 69.816 ;
     RECT  7.693 71.76 7.808 76.584 ;
     RECT  7.237 78.624 7.808 81.336 ;
     RECT  7.585 82.608 7.808 83.064 ;
     RECT  7.808 2.148 7.912 86.412 ;
     RECT  7.912 2.418 8.104 86.142 ;
     RECT  8.104 82.704 8.129 83.064 ;
     RECT  8.104 71.76 8.309 78.648 ;
     RECT  8.104 18.768 8.345 30.264 ;
     RECT  8.104 10.656 8.381 16.152 ;
     RECT  8.104 31.344 8.417 33.144 ;
     RECT  8.104 79.728 8.531 81.528 ;
     RECT  8.345 20.112 8.561 30.264 ;
     RECT  8.561 25.536 8.597 30.264 ;
     RECT  8.104 54.672 8.597 70.056 ;
     RECT  8.104 17.472 8.723 17.496 ;
     RECT  8.597 54.672 8.777 69.816 ;
     RECT  8.531 79.728 8.963 80.424 ;
     RECT  8.104 42.816 9.097 44.184 ;
     RECT  8.104 45.552 9.097 47.832 ;
     RECT  8.129 82.896 9.097 83.064 ;
     RECT  8.104 39.456 9.133 41.448 ;
     RECT  9.097 82.8 9.133 83.064 ;
     RECT  8.777 62.544 9.137 69.816 ;
     RECT  8.104 51.168 9.169 53.64 ;
     RECT  8.777 54.672 9.169 61.464 ;
     RECT  9.097 42.768 9.173 44.184 ;
     RECT  8.104 34.128 9.205 34.152 ;
     RECT  8.104 35.328 9.205 38.28 ;
     RECT  9.133 82.8 9.205 83.16 ;
     RECT  9.205 34.128 9.281 38.28 ;
     RECT  8.345 18.768 9.313 19.032 ;
     RECT  9.205 82.752 9.352 83.16 ;
     RECT  9.281 36.528 9.385 38.28 ;
     RECT  9.133 39.456 9.385 41.544 ;
     RECT  9.097 45.504 9.385 47.832 ;
     RECT  8.963 80.4 9.389 80.424 ;
     RECT  9.352 82.656 9.421 83.16 ;
     RECT  9.385 36.528 9.425 41.544 ;
     RECT  8.309 71.76 9.425 78.072 ;
     RECT  8.417 31.344 9.457 32.904 ;
     RECT  9.281 34.128 9.457 35.064 ;
     RECT  9.173 44.16 9.457 44.184 ;
     RECT  9.385 45.168 9.457 47.832 ;
     RECT  8.104 48.96 9.457 49.56 ;
     RECT  9.169 51.168 9.457 61.464 ;
     RECT  8.597 25.584 9.569 30.264 ;
     RECT  8.104 84.288 9.569 84.312 ;
     RECT  9.425 71.76 9.601 77.544 ;
     RECT  9.137 68.784 9.637 69.816 ;
     RECT  9.601 71.184 9.637 77.544 ;
     RECT  9.457 31.344 9.641 35.064 ;
     RECT  9.637 68.784 9.677 77.544 ;
     RECT  9.425 36.912 9.713 41.544 ;
     RECT  9.641 31.344 9.785 33.624 ;
     RECT  8.531 81.504 9.821 81.528 ;
     RECT  9.313 18.048 9.853 19.032 ;
     RECT  8.561 20.112 9.853 24.552 ;
     RECT  9.853 18.048 9.925 24.552 ;
     RECT  9.677 74.976 9.965 77.544 ;
     RECT  9.713 36.912 10.037 38.28 ;
     RECT  8.381 11.808 10.069 16.152 ;
     RECT  9.785 32.88 10.145 33.624 ;
     RECT  9.457 48.96 10.177 61.464 ;
     RECT  9.785 31.344 10.181 31.896 ;
     RECT  10.069 11.808 10.249 16.488 ;
     RECT  9.173 42.768 10.249 42.84 ;
     RECT  9.457 44.16 10.249 47.832 ;
     RECT  9.421 82.656 10.325 83.256 ;
     RECT  9.713 39.312 10.393 41.544 ;
     RECT  10.249 42.768 10.393 47.832 ;
     RECT  10.393 39.312 10.465 47.832 ;
     RECT  10.177 48.912 10.465 61.464 ;
     RECT  8.381 10.656 10.501 10.68 ;
     RECT  10.249 11.808 10.501 16.584 ;
     RECT  9.641 34.752 10.501 35.064 ;
     RECT  10.037 36.912 10.501 37.56 ;
     RECT  10.145 32.88 10.505 32.904 ;
     RECT  9.925 18.048 10.573 25.224 ;
     RECT  9.569 26.208 10.573 30.264 ;
     RECT  10.501 10.656 10.609 16.584 ;
     RECT  10.573 18.048 10.609 30.264 ;
     RECT  10.609 10.656 10.645 30.264 ;
     RECT  10.181 31.344 10.645 31.8 ;
     RECT  10.645 10.656 10.685 31.8 ;
     RECT  9.677 68.784 10.717 73.848 ;
     RECT  9.137 62.544 10.753 67.656 ;
     RECT  10.717 68.784 10.753 73.992 ;
     RECT  9.965 75.216 10.787 77.544 ;
     RECT  10.325 82.8 10.829 83.256 ;
     RECT  10.685 25.2 10.865 31.8 ;
     RECT  10.787 76.368 10.865 77.544 ;
     RECT  10.501 34.752 10.901 37.56 ;
     RECT  9.637 78.624 10.933 78.648 ;
     RECT  10.465 39.312 10.973 61.464 ;
     RECT  10.933 78.624 11.005 79.32 ;
     RECT  10.973 46.56 11.081 61.464 ;
     RECT  10.901 34.8 11.225 37.56 ;
     RECT  10.685 10.656 11.329 24.12 ;
     RECT  10.865 25.632 11.329 31.8 ;
     RECT  10.829 82.944 11.365 83.256 ;
     RECT  10.753 62.544 11.401 73.992 ;
     RECT  11.081 49.488 11.405 61.464 ;
     RECT  11.365 82.944 11.413 83.544 ;
     RECT  11.405 54.768 11.441 61.464 ;
     RECT  11.413 82.944 11.459 84.408 ;
     RECT  11.329 10.272 11.473 24.12 ;
     RECT  11.329 25.632 11.617 32.28 ;
     RECT  11.005 78.624 11.617 79.512 ;
     RECT  10.973 39.312 11.653 45.192 ;
     RECT  11.459 84.384 11.657 84.408 ;
     RECT  11.401 62.544 11.693 74.088 ;
     RECT  11.473 10.176 11.747 24.12 ;
     RECT  11.747 12.816 11.869 24.12 ;
     RECT  11.693 70.56 11.869 74.088 ;
     RECT  10.787 75.216 11.869 75.24 ;
     RECT  11.653 39.216 11.941 45.192 ;
     RECT  11.441 55.248 11.941 61.464 ;
     RECT  11.459 82.944 11.941 83.064 ;
     RECT  11.869 70.56 12.013 75.24 ;
     RECT  10.865 76.464 12.013 77.544 ;
     RECT  10.393 80.928 12.013 80.952 ;
     RECT  11.941 82.464 12.013 83.064 ;
     RECT  11.225 34.8 12.017 35.976 ;
     RECT  11.225 37.104 12.085 37.56 ;
     RECT  11.941 39.216 12.121 45.288 ;
     RECT  12.085 37.104 12.229 37.752 ;
     RECT  12.121 39.216 12.229 45.432 ;
     RECT  12.013 70.56 12.229 77.544 ;
     RECT  11.617 78.576 12.229 79.512 ;
     RECT  11.869 12.816 12.233 24.552 ;
     RECT  12.017 35.328 12.337 35.976 ;
     RECT  12.337 35.328 12.373 36.12 ;
     RECT  12.229 37.104 12.373 45.432 ;
     RECT  11.749 8.208 12.409 8.232 ;
     RECT  12.229 70.56 12.481 79.512 ;
     RECT  11.941 55.248 12.517 61.512 ;
     RECT  11.693 62.544 12.517 69.336 ;
     RECT  12.013 80.928 12.517 83.064 ;
     RECT  11.405 49.488 12.697 51.192 ;
     RECT  12.481 70.56 12.769 79.8 ;
     RECT  12.517 55.248 12.805 69.336 ;
     RECT  11.081 46.56 12.841 48.456 ;
     RECT  12.697 49.488 12.841 51.24 ;
     RECT  12.769 70.56 12.841 79.848 ;
     RECT  12.841 46.56 12.913 51.48 ;
     RECT  11.405 52.464 12.913 53.592 ;
     RECT  12.841 70.368 12.913 79.848 ;
     RECT  11.747 10.176 12.985 11.688 ;
     RECT  12.301 33.504 12.985 33.528 ;
     RECT  12.373 35.328 12.985 45.432 ;
     RECT  12.805 55.152 12.985 69.336 ;
     RECT  12.913 70.32 12.985 79.848 ;
     RECT  12.985 55.152 13.021 79.848 ;
     RECT  13.021 55.152 13.057 79.944 ;
     RECT  11.617 25.632 13.093 32.328 ;
     RECT  12.985 33.504 13.093 34.344 ;
     RECT  12.913 46.56 13.093 53.592 ;
     RECT  13.057 54.672 13.093 79.944 ;
     RECT  12.985 10.176 13.165 11.784 ;
     RECT  12.233 12.816 13.165 17.4 ;
     RECT  12.409 8.208 13.208 9.096 ;
     RECT  13.165 10.176 13.208 17.4 ;
     RECT  12.233 18.72 13.208 24.552 ;
     RECT  13.093 25.632 13.208 34.344 ;
     RECT  12.985 35.328 13.208 45.576 ;
     RECT  13.093 46.56 13.208 79.944 ;
     RECT  12.517 80.928 13.208 83.352 ;
     RECT  12.517 84.96 13.208 84.984 ;
     RECT  13.208 2.148 13.312 86.412 ;
     RECT  13.312 2.418 13.504 86.142 ;
     RECT  13.504 66.72 13.565 73.608 ;
     RECT  13.504 10.224 13.619 10.68 ;
     RECT  13.565 66.72 13.619 73.56 ;
     RECT  13.504 84.336 13.619 85.08 ;
     RECT  13.504 52.8 13.637 65.4 ;
     RECT  13.504 8.208 13.673 9.096 ;
     RECT  13.504 32.736 13.673 44.184 ;
     RECT  13.504 45.168 13.673 45.528 ;
     RECT  13.637 52.848 13.673 58.488 ;
     RECT  13.673 45.264 13.745 45.528 ;
     RECT  13.504 11.76 13.781 17.496 ;
     RECT  13.637 59.568 13.853 65.4 ;
     RECT  13.504 81.456 13.961 83.352 ;
     RECT  13.504 46.56 13.997 51.672 ;
     RECT  13.961 82.464 14.033 83.352 ;
     RECT  14.033 82.608 14.069 83.352 ;
     RECT  13.745 45.456 14.213 45.528 ;
     RECT  14.069 82.752 14.213 83.352 ;
     RECT  14.213 82.752 14.249 82.968 ;
     RECT  13.504 18.672 14.284 31.752 ;
     RECT  14.284 19.44 14.321 31.752 ;
     RECT  13.504 74.64 14.357 74.664 ;
     RECT  13.619 10.224 14.497 10.632 ;
     RECT  13.961 81.456 14.497 81.48 ;
     RECT  13.997 46.56 14.573 51.624 ;
     RECT  13.781 11.808 14.605 17.496 ;
     RECT  14.321 31.44 14.713 31.752 ;
     RECT  13.673 32.736 14.713 37.704 ;
     RECT  13.853 59.568 14.749 65.304 ;
     RECT  14.605 11.808 14.773 17.544 ;
     RECT  14.213 45.504 14.785 45.528 ;
     RECT  13.504 75.648 14.789 79.896 ;
     RECT  14.497 9.792 14.821 10.632 ;
     RECT  14.773 11.616 14.821 17.544 ;
     RECT  14.789 79.536 14.821 79.896 ;
     RECT  14.497 80.928 14.821 81.48 ;
     RECT  14.821 9.792 14.825 17.544 ;
     RECT  14.713 31.44 14.825 37.704 ;
     RECT  14.789 75.648 14.861 78.072 ;
     RECT  13.673 8.208 14.893 8.424 ;
     RECT  13.673 52.848 14.897 58.152 ;
     RECT  14.821 79.536 14.897 81.48 ;
     RECT  13.619 85.056 14.897 85.08 ;
     RECT  14.785 45.504 14.929 45.576 ;
     RECT  14.573 46.56 14.929 51.48 ;
     RECT  14.897 52.848 14.929 57.72 ;
     RECT  14.893 8.208 15.037 8.808 ;
     RECT  14.825 9.792 15.037 17.496 ;
     RECT  13.619 66.72 15.041 73.512 ;
     RECT  14.749 59.328 15.157 65.304 ;
     RECT  14.249 82.944 15.181 82.968 ;
     RECT  15.181 82.944 15.253 83.544 ;
     RECT  14.861 78.048 15.257 78.072 ;
     RECT  14.897 80.256 15.325 81.48 ;
     RECT  15.253 82.8 15.325 83.544 ;
     RECT  15.037 8.208 15.365 17.496 ;
     RECT  14.321 19.44 15.397 30.408 ;
     RECT  15.041 67.104 15.397 73.512 ;
     RECT  15.397 18.768 15.443 30.408 ;
     RECT  14.825 31.44 15.481 35.016 ;
     RECT  13.673 38.928 15.683 44.184 ;
     RECT  15.397 67.104 15.781 73.8 ;
     RECT  15.365 8.208 15.797 9.048 ;
     RECT  15.481 31.44 15.829 31.608 ;
     RECT  15.481 32.736 15.833 35.016 ;
     RECT  14.929 52.8 15.865 57.72 ;
     RECT  15.781 67.104 15.865 74.136 ;
     RECT  15.793 79.152 15.901 79.176 ;
     RECT  15.325 80.256 15.901 83.544 ;
     RECT  14.861 75.648 15.925 76.92 ;
     RECT  14.825 36.096 15.937 37.704 ;
     RECT  15.833 34.128 15.973 35.016 ;
     RECT  15.865 67.104 15.973 74.52 ;
     RECT  15.925 75.648 15.973 77.304 ;
     RECT  14.929 45.504 16.009 51.48 ;
     RECT  15.973 67.104 16.019 77.304 ;
     RECT  15.365 10.08 16.049 17.496 ;
     RECT  15.157 59.328 16.124 66.12 ;
     RECT  15.865 52.8 16.153 58.152 ;
     RECT  16.124 59.232 16.153 66.12 ;
     RECT  16.019 74.64 16.225 77.304 ;
     RECT  15.901 79.152 16.229 83.544 ;
     RECT  16.225 74.64 16.297 77.544 ;
     RECT  16.229 79.152 16.297 79.176 ;
     RECT  16.009 45.504 16.405 51.672 ;
     RECT  16.153 52.8 16.405 66.12 ;
     RECT  16.229 80.784 16.405 83.544 ;
     RECT  16.405 45.504 16.409 66.12 ;
     RECT  16.297 74.64 16.409 79.176 ;
     RECT  15.829 31.104 16.441 31.608 ;
     RECT  13.504 7.104 16.513 7.128 ;
     RECT  15.797 8.208 16.513 8.232 ;
     RECT  16.441 30.96 16.513 31.608 ;
     RECT  15.833 32.736 16.513 32.76 ;
     RECT  16.153 84.96 16.547 85.512 ;
     RECT  16.405 80.784 16.549 83.592 ;
     RECT  16.513 30.96 16.553 32.76 ;
     RECT  15.443 18.768 16.621 29.64 ;
     RECT  16.409 49.776 16.653 66.12 ;
     RECT  15.683 39.216 16.693 44.184 ;
     RECT  16.409 74.64 16.739 77.736 ;
     RECT  16.549 80.784 16.739 83.784 ;
     RECT  16.049 10.416 16.765 17.496 ;
     RECT  16.621 18.768 16.765 29.736 ;
     RECT  16.653 58.464 16.789 66.12 ;
     RECT  16.019 67.104 16.789 73.56 ;
     RECT  15.937 36.048 16.837 37.704 ;
     RECT  16.693 38.784 16.837 44.184 ;
     RECT  16.739 83.184 17.017 83.784 ;
     RECT  16.547 84.96 17.017 84.984 ;
     RECT  15.973 34.128 17.089 35.064 ;
     RECT  16.789 58.464 17.089 73.56 ;
     RECT  16.653 49.776 17.093 57.336 ;
     RECT  16.553 30.96 17.129 31.944 ;
     RECT  16.513 7.104 17.165 8.232 ;
     RECT  16.409 79.152 17.197 79.176 ;
     RECT  17.165 7.104 17.201 7.128 ;
     RECT  17.089 58.464 17.219 73.656 ;
     RECT  16.765 10.416 17.273 29.736 ;
     RECT  16.369 9.264 17.305 9.288 ;
     RECT  17.273 10.416 17.305 10.44 ;
     RECT  17.305 9.264 17.309 10.44 ;
     RECT  16.409 45.504 17.449 48.792 ;
     RECT  17.093 49.776 17.449 51.096 ;
     RECT  16.739 74.64 17.453 76.872 ;
     RECT  17.089 33.072 17.485 35.064 ;
     RECT  16.837 36.048 17.485 44.184 ;
     RECT  17.485 33.072 17.489 44.184 ;
     RECT  17.273 11.664 17.521 29.736 ;
     RECT  17.165 8.208 17.557 8.232 ;
     RECT  17.309 9.264 17.557 10.2 ;
     RECT  17.093 52.272 17.773 57.336 ;
     RECT  17.219 58.464 17.773 67.416 ;
     RECT  16.739 80.784 17.917 82.008 ;
     RECT  17.017 83.184 17.917 84.984 ;
     RECT  17.453 74.88 18.205 76.872 ;
     RECT  17.197 79.152 18.205 79.752 ;
     RECT  18.205 74.88 18.313 77.4 ;
     RECT  18.205 78.432 18.313 79.752 ;
     RECT  17.489 41.328 18.349 44.184 ;
     RECT  17.557 8.208 18.421 10.2 ;
     RECT  17.129 30.96 18.421 31.416 ;
     RECT  17.489 33.072 18.469 40.104 ;
     RECT  18.349 41.328 18.469 44.472 ;
     RECT  18.421 7.92 18.565 10.344 ;
     RECT  17.219 68.64 18.565 73.656 ;
     RECT  18.313 74.88 18.565 79.752 ;
     RECT  17.917 80.784 18.565 84.984 ;
     RECT  18.565 7.344 18.608 10.344 ;
     RECT  17.521 11.664 18.608 29.832 ;
     RECT  18.421 30.912 18.608 31.416 ;
     RECT  18.469 33.072 18.608 44.472 ;
     RECT  17.449 45.504 18.608 51.096 ;
     RECT  17.773 52.272 18.608 67.416 ;
     RECT  18.565 68.64 18.608 79.752 ;
     RECT  18.565 80.784 18.608 85.512 ;
     RECT  18.608 2.148 18.712 86.412 ;
     RECT  18.712 2.418 18.904 86.142 ;
     RECT  18.904 32.064 19.073 53.4 ;
     RECT  18.904 54.624 19.073 73.656 ;
     RECT  19.073 54.72 19.145 73.656 ;
     RECT  18.904 30.768 19.276 30.984 ;
     RECT  18.904 74.736 19.475 85.512 ;
     RECT  19.475 81.888 19.541 85.512 ;
     RECT  18.904 7.92 19.721 29.688 ;
     RECT  19.475 74.736 19.901 80.616 ;
     RECT  19.073 33.36 19.933 53.4 ;
     RECT  19.901 74.736 20.113 79.992 ;
     RECT  19.073 32.064 20.149 32.28 ;
     RECT  19.933 33.36 20.149 53.592 ;
     RECT  19.276 30.912 20.185 30.984 ;
     RECT  20.149 32.064 20.185 53.592 ;
     RECT  20.185 30.912 20.197 53.592 ;
     RECT  19.145 55.152 20.197 73.656 ;
     RECT  20.197 30.912 20.243 73.656 ;
     RECT  19.721 8.208 20.293 29.688 ;
     RECT  20.243 30.912 20.293 73.368 ;
     RECT  20.293 8.208 20.549 73.368 ;
     RECT  20.549 8.208 20.585 29.736 ;
     RECT  20.113 74.688 20.585 79.992 ;
     RECT  19.541 81.888 20.653 85.416 ;
     RECT  20.653 81.888 20.684 86.088 ;
     RECT  20.684 81.792 20.771 86.088 ;
     RECT  20.771 83.52 20.812 85.8 ;
     RECT  20.585 79.584 21.049 79.992 ;
     RECT  20.585 8.208 21.085 10.2 ;
     RECT  21.085 8.112 21.125 10.2 ;
     RECT  20.549 30.912 21.125 73.368 ;
     RECT  21.125 44.064 21.161 50.664 ;
     RECT  21.161 44.064 21.197 50.472 ;
     RECT  21.049 79.584 21.265 80.616 ;
     RECT  20.771 81.792 21.265 81.912 ;
     RECT  20.585 11.712 21.269 29.736 ;
     RECT  21.125 51.648 21.305 73.368 ;
     RECT  21.269 26.112 21.589 29.736 ;
     RECT  21.125 30.912 21.589 43.08 ;
     RECT  21.305 71.616 21.589 73.368 ;
     RECT  20.585 74.688 21.589 77.352 ;
     RECT  21.269 11.712 21.593 25.128 ;
     RECT  20.585 78.48 21.629 78.504 ;
     RECT  21.589 71.616 21.683 77.352 ;
     RECT  21.593 11.712 21.949 16.104 ;
     RECT  21.683 74.688 21.953 77.352 ;
     RECT  20.812 83.52 21.985 84.36 ;
     RECT  20.812 85.392 21.985 85.8 ;
     RECT  21.265 79.584 22.057 81.912 ;
     RECT  21.985 83.52 22.165 85.8 ;
     RECT  21.305 51.648 22.169 70.392 ;
     RECT  21.589 26.112 22.201 43.08 ;
     RECT  21.197 44.064 22.201 50.184 ;
     RECT  21.953 75.984 22.201 77.352 ;
     RECT  22.169 51.648 22.313 65.688 ;
     RECT  21.953 74.688 22.385 75 ;
     RECT  21.125 9.888 22.493 9.96 ;
     RECT  22.201 26.112 22.529 50.184 ;
     RECT  22.529 35.472 22.561 50.184 ;
     RECT  22.561 35.472 22.633 50.328 ;
     RECT  22.313 51.648 22.633 65.496 ;
     RECT  22.633 35.472 22.643 65.496 ;
     RECT  21.125 8.112 22.669 8.712 ;
     RECT  22.493 9.888 22.669 9.912 ;
     RECT  21.949 11.52 22.669 16.104 ;
     RECT  21.593 17.52 22.669 25.128 ;
     RECT  22.169 66.72 22.669 70.392 ;
     RECT  22.201 75.984 22.7 77.544 ;
     RECT  22.165 83.28 22.701 85.8 ;
     RECT  22.7 75.984 22.741 78.072 ;
     RECT  22.057 79.2 22.741 81.912 ;
     RECT  22.643 35.568 22.745 65.496 ;
     RECT  22.669 8.112 22.777 9.912 ;
     RECT  22.669 11.52 22.777 25.128 ;
     RECT  22.529 26.112 22.777 34.104 ;
     RECT  22.777 8.016 22.789 9.912 ;
     RECT  22.701 83.28 22.853 85.512 ;
     RECT  22.789 7.392 22.861 9.912 ;
     RECT  22.861 8.688 22.889 9.912 ;
     RECT  22.853 83.28 22.961 84.216 ;
     RECT  22.669 66.72 22.993 70.44 ;
     RECT  21.683 71.616 22.993 73.608 ;
     RECT  22.385 74.688 22.993 74.904 ;
     RECT  22.741 75.984 22.993 81.912 ;
     RECT  22.961 83.28 22.993 84.168 ;
     RECT  22.745 35.616 23.317 65.496 ;
     RECT  22.993 66.72 23.317 73.608 ;
     RECT  22.993 74.64 23.353 74.904 ;
     RECT  22.993 75.984 23.353 84.168 ;
     RECT  22.889 9.36 23.461 9.912 ;
     RECT  22.861 7.392 23.641 7.416 ;
     RECT  23.353 74.64 23.677 84.168 ;
     RECT  23.317 35.616 23.713 73.608 ;
     RECT  23.641 7.2 23.857 7.416 ;
     RECT  23.353 3.888 24.008 3.912 ;
     RECT  23.857 6.384 24.008 7.416 ;
     RECT  23.461 9.36 24.008 10.488 ;
     RECT  22.777 11.52 24.008 34.104 ;
     RECT  23.713 35.328 24.008 73.608 ;
     RECT  23.677 74.592 24.008 84.168 ;
     RECT  22.853 85.2 24.008 85.512 ;
     RECT  24.008 2.148 24.112 86.412 ;
     RECT  24.112 2.418 24.304 86.142 ;
     RECT  24.304 71.904 24.365 76.344 ;
     RECT  24.304 11.76 24.473 67.656 ;
     RECT  24.473 33.072 24.509 67.656 ;
     RECT  24.304 3.888 24.797 8.232 ;
     RECT  24.473 11.76 24.833 31.944 ;
     RECT  24.797 3.888 25.049 5.352 ;
     RECT  24.304 77.52 25.157 80.904 ;
     RECT  24.509 33.072 25.229 33.096 ;
     RECT  25.157 77.52 25.229 80.664 ;
     RECT  24.509 34.08 25.331 67.656 ;
     RECT  25.229 77.52 25.337 80.376 ;
     RECT  24.797 7.68 25.409 8.232 ;
     RECT  25.331 34.08 25.477 50.136 ;
     RECT  24.304 9.36 25.48 10.728 ;
     RECT  25.331 51.12 25.525 67.656 ;
     RECT  24.304 68.784 25.525 70.632 ;
     RECT  25.525 51.12 25.585 70.632 ;
     RECT  24.365 71.904 25.585 76.056 ;
     RECT  25.337 77.52 25.585 80.136 ;
     RECT  24.833 11.808 25.621 31.944 ;
     RECT  25.477 33.6 25.625 50.136 ;
     RECT  25.585 51.12 25.667 80.136 ;
     RECT  25.409 7.68 25.801 7.944 ;
     RECT  25.48 9.36 25.801 10.776 ;
     RECT  25.621 11.808 25.801 32.616 ;
     RECT  25.049 3.984 25.913 5.352 ;
     RECT  24.304 81.888 25.949 85.512 ;
     RECT  25.801 9.36 25.955 32.616 ;
     RECT  25.949 83.088 26.021 85.512 ;
     RECT  25.667 74.352 26.237 80.136 ;
     RECT  26.237 74.688 26.273 80.136 ;
     RECT  25.801 7.392 26.309 7.944 ;
     RECT  25.955 9.36 26.309 19.512 ;
     RECT  25.955 20.544 26.345 32.616 ;
     RECT  25.913 4.704 26.525 5.352 ;
     RECT  26.273 76.224 26.525 80.136 ;
     RECT  25.625 33.6 26.665 44.424 ;
     RECT  26.309 7.632 26.741 7.944 ;
     RECT  26.525 79.68 26.773 80.136 ;
     RECT  25.949 81.888 26.809 82.008 ;
     RECT  26.665 33.024 26.869 44.424 ;
     RECT  25.625 45.456 26.869 50.136 ;
     RECT  26.773 79.68 26.917 80.568 ;
     RECT  26.809 81.792 26.917 82.008 ;
     RECT  26.917 79.68 27.065 82.008 ;
     RECT  25.667 51.12 27.205 73.272 ;
     RECT  26.309 18.72 27.253 19.512 ;
     RECT  26.345 20.544 27.253 32.04 ;
     RECT  26.869 33.024 27.253 50.136 ;
     RECT  27.205 51.12 27.253 73.32 ;
     RECT  27.253 33.024 27.277 73.32 ;
     RECT  26.309 9.36 27.313 17.4 ;
     RECT  27.253 18.72 27.313 32.04 ;
     RECT  26.273 74.688 27.349 75.24 ;
     RECT  26.525 76.224 27.349 78.696 ;
     RECT  27.277 33.024 27.385 73.368 ;
     RECT  27.349 74.688 27.385 78.696 ;
     RECT  26.021 83.088 27.457 85.224 ;
     RECT  27.065 80.928 27.565 82.008 ;
     RECT  27.457 83.088 27.565 85.512 ;
     RECT  27.385 33.024 27.781 78.696 ;
     RECT  27.065 79.68 27.781 79.944 ;
     RECT  26.525 5.184 27.853 5.352 ;
     RECT  26.917 4.128 27.925 4.152 ;
     RECT  27.781 33.024 27.965 79.944 ;
     RECT  27.853 5.184 28.001 6.072 ;
     RECT  26.741 7.632 28.033 7.752 ;
     RECT  27.925 3.696 28.321 4.152 ;
     RECT  28.001 5.184 28.321 5.544 ;
     RECT  27.565 80.928 28.361 85.512 ;
     RECT  28.033 7.632 28.393 7.992 ;
     RECT  27.313 9.36 28.393 32.04 ;
     RECT  27.965 33.024 28.397 79.848 ;
     RECT  28.393 7.152 28.501 7.992 ;
     RECT  28.393 9.024 28.501 32.04 ;
     RECT  28.361 83.184 28.825 85.512 ;
     RECT  28.501 7.152 28.861 32.04 ;
     RECT  28.825 83.184 28.933 85.704 ;
     RECT  28.397 58.416 29.005 79.848 ;
     RECT  28.361 80.928 29.005 82.2 ;
     RECT  28.861 6.768 29.041 32.04 ;
     RECT  28.397 33.024 29.041 57.384 ;
     RECT  28.321 3.696 29.077 5.544 ;
     RECT  29.077 3.696 29.221 5.592 ;
     RECT  29.041 6.768 29.221 57.384 ;
     RECT  28.933 83.184 29.329 85.944 ;
     RECT  29.221 3.408 29.408 57.384 ;
     RECT  29.005 58.416 29.408 82.2 ;
     RECT  29.329 83.184 29.408 85.992 ;
     RECT  29.408 2.148 29.512 86.412 ;
     RECT  29.512 2.418 29.704 86.142 ;
     RECT  29.704 7.92 29.891 57.384 ;
     RECT  29.704 58.416 29.945 85.992 ;
     RECT  29.945 58.608 30.017 85.992 ;
     RECT  30.017 70.656 30.083 85.992 ;
     RECT  29.704 3.408 30.125 6.312 ;
     RECT  30.017 58.608 30.227 69.528 ;
     RECT  30.083 70.656 30.275 81.72 ;
     RECT  30.275 70.656 30.305 80.952 ;
     RECT  30.227 58.608 30.341 69.336 ;
     RECT  30.125 4.128 30.485 6.312 ;
     RECT  30.305 75.216 30.557 80.952 ;
     RECT  29.891 8.448 30.665 57.384 ;
     RECT  30.557 75.216 30.701 75.72 ;
     RECT  30.701 75.216 30.773 75.24 ;
     RECT  30.665 8.448 30.809 33.96 ;
     RECT  30.485 5.712 30.913 6.312 ;
     RECT  30.665 34.992 30.917 57.384 ;
     RECT  30.485 4.128 31.201 4.152 ;
     RECT  30.809 13.296 31.205 33.96 ;
     RECT  30.917 45.216 31.34 57.384 ;
     RECT  30.341 58.608 31.34 67.416 ;
     RECT  31.34 45.216 31.349 67.416 ;
     RECT  30.809 8.448 31.385 12.312 ;
     RECT  30.557 77.472 31.385 80.952 ;
     RECT  31.349 58.128 31.427 67.416 ;
     RECT  30.805 2.784 31.484 2.808 ;
     RECT  30.083 82.752 31.484 85.992 ;
     RECT  31.484 2.256 31.525 2.808 ;
     RECT  31.525 2.256 31.571 2.904 ;
     RECT  30.305 70.656 31.717 74.136 ;
     RECT  31.676 75.792 31.717 75.816 ;
     RECT  31.201 4.032 31.777 4.152 ;
     RECT  30.913 5.712 31.777 6.936 ;
     RECT  31.385 8.592 31.813 12.312 ;
     RECT  31.205 13.296 31.813 25.128 ;
     RECT  31.205 26.208 31.817 33.96 ;
     RECT  31.817 26.496 31.885 33.96 ;
     RECT  30.917 34.992 31.885 44.184 ;
     RECT  31.427 58.704 31.921 67.416 ;
     RECT  30.341 68.784 31.921 69.336 ;
     RECT  31.484 82.656 31.921 85.992 ;
     RECT  31.813 8.592 31.925 25.128 ;
     RECT  31.717 70.656 31.925 74.616 ;
     RECT  31.885 26.496 31.964 44.184 ;
     RECT  31.349 45.216 31.964 57.048 ;
     RECT  31.921 58.704 32.029 69.336 ;
     RECT  31.571 2.88 32.033 2.904 ;
     RECT  31.925 70.656 32.156 74.376 ;
     RECT  31.717 75.792 32.173 76.488 ;
     RECT  31.964 26.496 32.195 57.048 ;
     RECT  31.925 8.592 32.249 25.032 ;
     RECT  31.777 4.032 32.389 6.936 ;
     RECT  31.921 81.936 32.393 85.992 ;
     RECT  32.249 8.592 32.425 15.336 ;
     RECT  31.385 77.904 32.465 80.952 ;
     RECT  32.173 75.504 32.569 76.488 ;
     RECT  32.465 77.904 32.569 80.424 ;
     RECT  32.389 3.84 32.605 6.936 ;
     RECT  32.425 8.256 32.605 15.336 ;
     RECT  32.605 3.84 32.668 15.336 ;
     RECT  32.569 75.504 32.723 80.424 ;
     RECT  32.668 6.912 32.789 15.336 ;
     RECT  32.029 58.704 32.893 69.48 ;
     RECT  32.156 70.464 32.893 74.376 ;
     RECT  32.723 75.504 32.965 76.488 ;
     RECT  32.195 40.944 33.001 57.048 ;
     RECT  32.893 58.704 33.005 74.376 ;
     RECT  32.393 81.936 33.005 85.704 ;
     RECT  32.668 3.84 33.157 5.832 ;
     RECT  33.005 58.848 33.205 74.376 ;
     RECT  32.965 75.456 33.205 76.488 ;
     RECT  32.893 88.512 33.217 88.536 ;
     RECT  32.723 77.52 33.221 80.424 ;
     RECT  32.249 16.32 33.253 25.032 ;
     RECT  32.195 26.496 33.253 39.912 ;
     RECT  33.157 3.696 33.257 5.832 ;
     RECT  33.005 81.936 33.257 85.512 ;
     RECT  33.221 77.52 33.437 78.36 ;
     RECT  33.221 79.44 33.545 80.424 ;
     RECT  33.001 40.944 33.577 57.096 ;
     RECT  32.789 7.776 33.653 15.336 ;
     RECT  33.257 83.28 33.653 85.512 ;
     RECT  33.653 9.072 33.685 15.336 ;
     RECT  33.253 16.32 33.685 39.912 ;
     RECT  33.205 58.848 33.689 76.488 ;
     RECT  33.685 9.072 33.725 39.912 ;
     RECT  33.653 7.776 33.797 7.944 ;
     RECT  33.725 17.376 33.833 39.912 ;
     RECT  33.833 33.84 34.009 39.912 ;
     RECT  33.577 40.944 34.009 57.144 ;
     RECT  33.257 81.936 34.165 82.104 ;
     RECT  34.009 33.84 34.441 57.144 ;
     RECT  33.437 77.52 34.477 78.216 ;
     RECT  33.545 79.44 34.477 79.464 ;
     RECT  33.797 7.872 34.657 7.944 ;
     RECT  33.725 9.072 34.657 16.344 ;
     RECT  33.689 74.352 34.693 76.488 ;
     RECT  34.477 77.52 34.693 79.464 ;
     RECT  34.441 33.84 34.729 57.336 ;
     RECT  33.257 3.696 34.765 5.592 ;
     RECT  34.657 7.872 34.801 16.344 ;
     RECT  34.765 3.696 34.808 6.072 ;
     RECT  34.801 7.392 34.808 16.344 ;
     RECT  33.833 17.376 34.808 32.856 ;
     RECT  34.729 33.84 34.808 57.672 ;
     RECT  33.689 58.848 34.808 73.272 ;
     RECT  34.693 74.352 34.808 79.464 ;
     RECT  34.165 81.216 34.808 82.104 ;
     RECT  33.653 83.28 34.808 85.464 ;
     RECT  34.808 2.148 34.912 86.412 ;
     RECT  34.912 2.418 35.104 86.142 ;
     RECT  35.104 7.392 35.237 74.328 ;
     RECT  35.104 82.512 35.273 85.944 ;
     RECT  35.104 3.36 35.561 5.784 ;
     RECT  35.237 7.968 35.597 74.328 ;
     RECT  35.597 7.968 35.669 11.832 ;
     RECT  33.217 88.464 35.701 88.536 ;
     RECT  35.597 13.008 35.741 48.12 ;
     RECT  35.104 77.136 35.813 78.648 ;
     RECT  35.104 76.032 35.885 76.056 ;
     RECT  35.669 11.712 35.957 11.832 ;
     RECT  35.669 7.968 36.035 10.68 ;
     RECT  35.273 82.512 36.065 82.536 ;
     RECT  35.597 49.152 36.205 74.328 ;
     RECT  36.133 75.888 36.205 75.912 ;
     RECT  35.813 77.904 36.205 78.648 ;
     RECT  35.273 83.52 36.241 85.944 ;
     RECT  35.561 5.76 36.245 5.784 ;
     RECT  36.241 83.52 36.277 86.376 ;
     RECT  36.205 49.152 36.317 75.912 ;
     RECT  35.561 3.36 36.385 4.392 ;
     RECT  36.205 77.904 36.389 78.696 ;
     RECT  36.035 7.968 36.533 9.096 ;
     RECT  36.035 10.128 36.611 10.68 ;
     RECT  35.741 38.736 36.637 48.12 ;
     RECT  36.317 49.152 36.637 73.464 ;
     RECT  36.277 83.184 36.745 86.376 ;
     RECT  36.097 6.816 36.889 6.84 ;
     RECT  36.889 6.816 36.925 6.888 ;
     RECT  35.957 11.808 36.961 11.832 ;
     RECT  35.104 79.824 36.961 81.528 ;
     RECT  36.317 74.688 36.997 75.912 ;
     RECT  36.533 8.448 37.037 9.096 ;
     RECT  36.745 83.184 37.105 86.52 ;
     RECT  35.701 87.888 37.105 88.536 ;
     RECT  36.961 11.712 37.141 11.832 ;
     RECT  35.741 13.008 37.145 37.704 ;
     RECT  37.105 83.184 37.177 88.536 ;
     RECT  37.037 8.448 37.181 9 ;
     RECT  36.389 77.904 37.181 78.312 ;
     RECT  37.145 26.496 37.217 37.704 ;
     RECT  37.217 29.28 37.321 37.704 ;
     RECT  36.637 38.736 37.321 73.464 ;
     RECT  36.925 6.768 37.357 6.888 ;
     RECT  36.385 2.88 37.393 4.392 ;
     RECT  36.997 74.688 37.393 76.248 ;
     RECT  37.181 77.904 37.433 78.072 ;
     RECT  36.961 79.584 37.465 81.528 ;
     RECT  37.393 74.688 37.537 76.392 ;
     RECT  37.321 29.28 37.541 73.464 ;
     RECT  36.611 10.176 37.577 10.68 ;
     RECT  37.177 83.136 37.613 88.536 ;
     RECT  37.141 11.712 37.645 11.976 ;
     RECT  37.145 13.008 37.645 24.984 ;
     RECT  37.577 10.56 37.649 10.68 ;
     RECT  37.649 10.608 37.681 10.68 ;
     RECT  37.645 11.712 37.681 24.984 ;
     RECT  37.681 10.608 37.685 24.984 ;
     RECT  37.541 29.28 37.757 70.584 ;
     RECT  37.357 6.768 37.825 7.08 ;
     RECT  37.537 74.592 37.829 76.392 ;
     RECT  37.181 8.976 37.901 9 ;
     RECT  37.685 10.608 37.901 23.88 ;
     RECT  37.825 6.768 37.933 7.32 ;
     RECT  37.901 10.608 38.009 10.68 ;
     RECT  37.757 29.28 38.045 70.536 ;
     RECT  37.933 6.768 38.149 7.368 ;
     RECT  37.613 83.136 38.195 88.488 ;
     RECT  37.465 79.584 38.221 82.056 ;
     RECT  38.195 83.136 38.221 86.232 ;
     RECT  37.217 26.496 38.257 28.296 ;
     RECT  38.045 29.28 38.257 43.08 ;
     RECT  37.541 71.712 38.257 73.464 ;
     RECT  37.829 74.592 38.257 74.856 ;
     RECT  38.149 6.768 38.261 7.464 ;
     RECT  37.685 24.96 38.365 24.984 ;
     RECT  37.433 78.048 38.401 78.072 ;
     RECT  38.221 79.584 38.401 86.232 ;
     RECT  37.393 2.88 38.441 5.544 ;
     RECT  38.401 78.048 38.513 86.232 ;
     RECT  38.441 3.312 38.545 5.544 ;
     RECT  38.257 71.712 38.581 74.856 ;
     RECT  38.365 24.96 38.617 25.08 ;
     RECT  38.045 44.064 38.621 70.536 ;
     RECT  37.901 11.712 38.653 23.88 ;
     RECT  38.617 24.96 38.653 25.464 ;
     RECT  38.653 11.712 38.801 25.464 ;
     RECT  38.581 71.52 38.819 74.856 ;
     RECT  38.545 3.312 38.837 5.736 ;
     RECT  38.261 7.296 38.869 7.464 ;
     RECT  37.829 75.984 38.869 76.392 ;
     RECT  38.801 11.712 38.873 18.84 ;
     RECT  38.801 19.872 38.977 25.464 ;
     RECT  38.257 26.496 38.977 43.08 ;
     RECT  38.819 71.616 38.981 74.856 ;
     RECT  38.869 75.984 38.981 77.112 ;
     RECT  38.009 10.656 39.013 10.68 ;
     RECT  38.873 11.712 39.013 15.336 ;
     RECT  38.837 3.312 39.053 3.384 ;
     RECT  38.977 19.872 39.053 43.08 ;
     RECT  38.513 78.672 39.053 86.232 ;
     RECT  38.837 4.464 39.125 5.544 ;
     RECT  39.053 79.68 39.205 86.232 ;
     RECT  38.195 87.216 39.205 88.488 ;
     RECT  39.053 29.28 39.337 43.08 ;
     RECT  38.621 44.064 39.337 70.296 ;
     RECT  38.869 7.296 39.409 7.992 ;
     RECT  38.077 9.504 39.949 9.528 ;
     RECT  39.013 10.656 39.949 15.336 ;
     RECT  39.205 79.68 39.985 88.488 ;
     RECT  38.981 75.984 40.021 76.008 ;
     RECT  38.981 77.088 40.021 77.112 ;
     RECT  39.949 9.504 40.069 15.336 ;
     RECT  39.409 6.672 40.093 7.992 ;
     RECT  40.069 9.072 40.165 15.336 ;
     RECT  38.873 16.32 40.165 18.84 ;
     RECT  39.053 19.872 40.165 28.296 ;
     RECT  38.981 71.616 40.201 74.616 ;
     RECT  40.021 75.984 40.201 77.112 ;
     RECT  39.053 3.312 40.208 3.336 ;
     RECT  39.125 4.464 40.208 4.584 ;
     RECT  40.093 6 40.208 7.992 ;
     RECT  40.165 9.072 40.208 28.296 ;
     RECT  39.337 29.28 40.208 70.296 ;
     RECT  40.201 71.616 40.208 77.112 ;
     RECT  39.697 78.624 40.208 78.648 ;
     RECT  39.985 79.68 40.208 88.536 ;
     RECT  40.208 2.148 40.312 88.536 ;
     RECT  40.312 2.418 40.504 88.536 ;
     RECT  40.504 80.4 40.673 88.536 ;
     RECT  40.504 71.952 40.853 76.776 ;
     RECT  40.673 87.168 40.925 88.536 ;
     RECT  40.504 20.688 41.027 28.296 ;
     RECT  40.504 10.656 41.177 19.656 ;
     RECT  40.504 29.28 41.321 69.912 ;
     RECT  40.504 3.936 41.429 4.248 ;
     RECT  40.853 76.752 41.465 76.776 ;
     RECT  41.533 76.944 41.569 77.112 ;
     RECT  40.504 78.096 41.569 79.224 ;
     RECT  41.177 10.656 41.645 16.008 ;
     RECT  41.569 76.944 41.681 79.224 ;
     RECT  40.673 80.4 41.681 86.088 ;
     RECT  40.504 5.76 41.749 6.936 ;
     RECT  40.504 7.968 41.749 7.992 ;
     RECT  40.925 87.744 41.753 88.536 ;
     RECT  40.504 9.072 41.821 9.096 ;
     RECT  41.321 29.28 41.825 50.616 ;
     RECT  41.749 5.76 41.852 7.992 ;
     RECT  41.825 29.28 41.861 50.232 ;
     RECT  40.504 70.944 41.897 70.968 ;
     RECT  40.853 71.952 41.929 75.432 ;
     RECT  41.861 29.28 41.933 44.472 ;
     RECT  41.852 5.616 41.939 7.992 ;
     RECT  41.645 10.656 42.001 10.824 ;
     RECT  41.821 9.072 42.037 9.384 ;
     RECT  41.027 20.928 42.037 28.296 ;
     RECT  41.933 29.28 42.037 36.36 ;
     RECT  42.037 9.024 42.073 9.384 ;
     RECT  42.001 10.608 42.073 10.824 ;
     RECT  41.681 78.096 42.109 79.224 ;
     RECT  41.681 80.4 42.109 81 ;
     RECT  41.861 45.984 42.179 50.232 ;
     RECT  41.681 76.944 42.185 76.968 ;
     RECT  42.109 78.096 42.329 81 ;
     RECT  41.753 88.224 42.365 88.536 ;
     RECT  41.681 81.984 42.469 86.088 ;
     RECT  42.277 87.168 42.469 87.192 ;
     RECT  42.073 9.024 42.509 10.824 ;
     RECT  41.939 5.856 42.541 7.992 ;
     RECT  42.509 9.024 42.541 10.632 ;
     RECT  41.321 51.696 42.613 69.912 ;
     RECT  41.929 71.952 42.613 75.576 ;
     RECT  42.541 5.856 42.617 10.632 ;
     RECT  42.329 78.096 42.649 78.936 ;
     RECT  42.329 79.92 42.649 81 ;
     RECT  42.469 81.984 42.649 87.192 ;
     RECT  42.613 71.664 42.793 75.576 ;
     RECT  42.617 6.384 42.833 10.632 ;
     RECT  41.933 37.44 42.901 44.472 ;
     RECT  42.901 37.44 42.908 45 ;
     RECT  42.179 45.984 42.908 50.136 ;
     RECT  42.908 37.44 42.995 50.136 ;
     RECT  42.613 51.648 43.009 69.912 ;
     RECT  42.995 37.44 43.043 45 ;
     RECT  42.995 45.984 43.043 50.136 ;
     RECT  43.043 49.872 43.049 50.136 ;
     RECT  43.009 51.216 43.081 69.912 ;
     RECT  42.649 79.92 43.081 87.192 ;
     RECT  41.429 4.224 43.085 4.248 ;
     RECT  41.177 17.04 43.117 19.656 ;
     RECT  42.037 20.928 43.117 36.36 ;
     RECT  43.081 51.216 43.117 70.392 ;
     RECT  42.833 6.384 43.229 10.056 ;
     RECT  42.793 71.664 43.229 76.392 ;
     RECT  43.229 74.016 43.301 76.392 ;
     RECT  42.365 88.512 43.333 88.536 ;
     RECT  43.081 79.92 43.373 87.24 ;
     RECT  43.117 17.04 43.381 36.36 ;
     RECT  43.373 80.88 43.388 87.24 ;
     RECT  43.333 88.416 43.388 88.536 ;
     RECT  43.229 9.648 43.445 10.056 ;
     RECT  43.381 16.992 43.549 36.36 ;
     RECT  43.043 37.44 43.549 44.472 ;
     RECT  43.049 50.112 43.549 50.136 ;
     RECT  43.117 51.216 43.549 70.584 ;
     RECT  43.388 80.88 43.553 88.536 ;
     RECT  43.229 6.384 43.729 8.424 ;
     RECT  41.645 11.808 43.837 16.008 ;
     RECT  43.549 16.992 43.837 44.472 ;
     RECT  42.649 77.52 43.837 78.936 ;
     RECT  43.729 6.048 43.873 8.424 ;
     RECT  43.837 11.808 43.945 44.472 ;
     RECT  43.043 45.984 43.949 48.84 ;
     RECT  43.549 50.112 43.949 70.584 ;
     RECT  43.873 6 44.021 8.424 ;
     RECT  43.229 71.664 44.053 72.84 ;
     RECT  43.949 50.592 44.057 70.584 ;
     RECT  43.945 11.04 44.129 44.472 ;
     RECT  43.301 75.936 44.161 76.392 ;
     RECT  43.837 77.52 44.161 79.752 ;
     RECT  43.445 9.648 44.165 9.912 ;
     RECT  43.225 4.704 44.233 4.728 ;
     RECT  44.129 20.112 44.237 44.472 ;
     RECT  44.057 50.592 44.237 70.392 ;
     RECT  43.553 83.088 44.243 88.536 ;
     RECT  44.233 4.704 44.269 4.776 ;
     RECT  44.021 6 44.269 7.608 ;
     RECT  44.161 75.936 44.405 79.752 ;
     RECT  44.165 9.888 44.417 9.912 ;
     RECT  44.243 87.744 44.453 88.536 ;
     RECT  44.269 4.704 44.485 7.608 ;
     RECT  44.053 71.616 44.485 72.84 ;
     RECT  43.301 74.016 44.485 74.616 ;
     RECT  44.485 4.656 44.593 7.608 ;
     RECT  44.129 11.04 44.597 19.08 ;
     RECT  44.597 11.04 44.989 17.496 ;
     RECT  43.553 80.88 45.025 82.008 ;
     RECT  44.243 83.088 45.025 86.712 ;
     RECT  44.237 27.936 45.061 44.472 ;
     RECT  44.593 4.464 45.169 7.608 ;
     RECT  44.597 18.72 45.205 19.08 ;
     RECT  44.237 20.112 45.205 26.856 ;
     RECT  45.205 18.72 45.253 26.856 ;
     RECT  45.061 27.936 45.253 44.616 ;
     RECT  44.485 71.616 45.308 74.616 ;
     RECT  44.405 75.936 45.308 79.848 ;
     RECT  45.308 71.616 45.349 79.848 ;
     RECT  45.025 80.88 45.349 86.712 ;
     RECT  45.169 4.464 45.421 7.992 ;
     RECT  45.349 71.616 45.445 86.712 ;
     RECT  44.453 87.792 45.445 88.536 ;
     RECT  43.949 45.984 45.493 48.408 ;
     RECT  43.261 3.408 45.608 3.432 ;
     RECT  45.421 4.464 45.608 8.184 ;
     RECT  44.989 10.368 45.608 17.496 ;
     RECT  45.253 18.72 45.608 44.616 ;
     RECT  45.493 45.984 45.608 49.08 ;
     RECT  44.237 50.592 45.608 68.136 ;
     RECT  44.237 69.264 45.608 70.392 ;
     RECT  45.445 71.616 45.608 88.536 ;
     RECT  45.608 2.148 45.712 88.536 ;
     RECT  45.712 2.256 45.904 88.536 ;
     RECT  45.904 10.704 45.929 12.12 ;
     RECT  45.904 50.592 46.109 72.456 ;
     RECT  45.904 15.984 46.115 49.608 ;
     RECT  45.904 3.84 46.181 5.064 ;
     RECT  45.904 6.624 46.217 9.72 ;
     RECT  46.109 50.832 46.217 72.456 ;
     RECT  46.217 6.912 46.307 9.72 ;
     RECT  46.307 9.696 46.333 9.72 ;
     RECT  46.115 16.128 46.333 49.608 ;
     RECT  45.904 73.632 46.505 74.712 ;
     RECT  46.505 74.448 46.577 74.664 ;
     RECT  46.333 16.128 46.636 44.088 ;
     RECT  45.904 75.792 46.721 88.536 ;
     RECT  46.636 16.128 46.757 43.944 ;
     RECT  46.217 50.832 46.835 72.168 ;
     RECT  46.181 3.84 47.293 4.92 ;
     RECT  47.293 3.84 47.329 5.4 ;
     RECT  46.307 6.912 47.329 8.52 ;
     RECT  46.757 16.128 47.333 43.704 ;
     RECT  46.333 45.168 47.333 49.608 ;
     RECT  47.329 3.84 47.401 8.52 ;
     RECT  45.929 10.848 47.405 12.12 ;
     RECT  47.333 16.128 47.405 27.048 ;
     RECT  47.401 3.408 47.441 8.52 ;
     RECT  47.405 16.128 47.459 27 ;
     RECT  47.405 11.232 47.461 12.12 ;
     RECT  45.904 13.104 47.461 15 ;
     RECT  46.835 58.512 47.477 72.168 ;
     RECT  47.441 4.416 47.545 8.52 ;
     RECT  47.461 11.232 47.545 15 ;
     RECT  47.459 16.128 47.545 26.904 ;
     RECT  45.904 2.256 47.612 2.28 ;
     RECT  47.441 3.408 47.612 3.432 ;
     RECT  47.477 71.712 47.617 72.168 ;
     RECT  46.577 74.448 47.617 74.472 ;
     RECT  46.721 75.792 47.693 79.08 ;
     RECT  47.612 2.256 47.699 3.432 ;
     RECT  47.545 11.232 47.837 26.904 ;
     RECT  47.545 4.416 47.852 9.048 ;
     RECT  47.477 58.512 47.869 70.68 ;
     RECT  47.333 45.6 47.905 49.608 ;
     RECT  47.837 11.232 47.909 20.232 ;
     RECT  46.835 50.832 47.909 57.144 ;
     RECT  47.909 11.232 47.939 20.136 ;
     RECT  47.333 28.176 47.941 43.704 ;
     RECT  47.939 11.328 47.98 20.136 ;
     RECT  47.905 45.6 48.181 49.704 ;
     RECT  47.909 50.832 48.181 51.912 ;
     RECT  47.693 75.792 48.233 76.008 ;
     RECT  47.693 77.088 48.269 79.08 ;
     RECT  47.909 53.04 48.301 57.144 ;
     RECT  47.869 58.128 48.301 70.68 ;
     RECT  48.181 45.6 48.305 51.912 ;
     RECT  48.301 53.04 48.413 70.68 ;
     RECT  47.852 4.416 48.467 9.672 ;
     RECT  48.467 4.416 48.485 5.448 ;
     RECT  48.467 6.768 48.557 9.672 ;
     RECT  47.617 74.448 48.589 74.616 ;
     RECT  47.837 21.504 48.593 26.904 ;
     RECT  48.557 6.816 48.62 9.672 ;
     RECT  48.62 6.816 48.707 9.96 ;
     RECT  47.941 28.176 48.733 44.472 ;
     RECT  48.593 22.128 48.805 26.904 ;
     RECT  48.733 27.984 48.805 44.472 ;
     RECT  48.589 74.448 48.877 74.712 ;
     RECT  48.233 75.792 48.877 75.816 ;
     RECT  48.805 22.128 48.881 44.472 ;
     RECT  48.269 77.088 48.881 78.552 ;
     RECT  47.699 3.408 48.949 3.432 ;
     RECT  48.485 4.416 48.949 5.208 ;
     RECT  48.707 6.816 48.953 9.096 ;
     RECT  48.881 77.088 48.953 78.408 ;
     RECT  48.953 77.088 49.057 78.072 ;
     RECT  48.949 3.408 49.061 5.208 ;
     RECT  48.413 53.04 49.061 66.12 ;
     RECT  48.953 8.976 49.097 9 ;
     RECT  47.617 71.712 49.129 72.936 ;
     RECT  48.877 74.448 49.129 75.816 ;
     RECT  49.057 77.04 49.129 78.072 ;
     RECT  47.98 11.328 49.241 20.04 ;
     RECT  48.305 46.752 49.273 51.912 ;
     RECT  49.061 53.04 49.273 65.784 ;
     RECT  49.129 71.712 49.313 75.816 ;
     RECT  48.305 45.6 49.349 45.624 ;
     RECT  49.273 46.752 49.453 65.784 ;
     RECT  49.453 46.176 49.457 65.784 ;
     RECT  46.721 80.4 49.525 88.536 ;
     RECT  49.241 11.328 49.565 19.416 ;
     RECT  49.565 11.328 49.673 17.88 ;
     RECT  48.413 67.104 49.741 70.68 ;
     RECT  49.313 71.712 49.741 73.08 ;
     RECT  49.061 3.408 49.777 5.064 ;
     RECT  49.525 80.064 49.777 88.536 ;
     RECT  48.953 6.816 49.813 7.944 ;
     RECT  49.313 74.352 49.849 75.816 ;
     RECT  49.129 76.896 49.849 78.072 ;
     RECT  49.741 67.104 49.868 73.08 ;
     RECT  49.777 2.832 49.993 5.064 ;
     RECT  48.881 22.128 50.101 43.848 ;
     RECT  49.813 6.24 50.209 7.944 ;
     RECT  49.777 79.536 50.249 88.536 ;
     RECT  49.457 60.912 50.281 65.784 ;
     RECT  49.868 66.96 50.281 73.08 ;
     RECT  49.849 74.352 50.281 78.072 ;
     RECT  50.101 22.128 50.389 44.136 ;
     RECT  49.561 45.168 50.389 45.192 ;
     RECT  49.993 2.64 50.533 5.064 ;
     RECT  49.673 11.328 50.569 17.496 ;
     RECT  49.457 46.176 50.641 59.928 ;
     RECT  50.281 60.912 50.641 78.072 ;
     RECT  50.569 10.848 50.677 17.496 ;
     RECT  49.201 21.12 50.677 21.144 ;
     RECT  50.389 22.128 50.677 45.192 ;
     RECT  50.677 21.12 50.713 45.192 ;
     RECT  50.209 6.24 50.725 8.712 ;
     RECT  50.677 9.936 50.725 17.496 ;
     RECT  50.725 6.24 50.785 17.496 ;
     RECT  50.713 20.88 50.857 45.192 ;
     RECT  50.641 46.176 50.857 78.072 ;
     RECT  50.533 2.64 50.869 5.256 ;
     RECT  50.785 6.24 50.869 17.832 ;
     RECT  50.869 2.64 51.008 17.832 ;
     RECT  49.565 19.008 51.008 19.416 ;
     RECT  50.857 20.88 51.008 78.072 ;
     RECT  50.249 79.536 51.008 87.528 ;
     RECT  51.008 2.148 51.112 87.528 ;
     RECT  51.112 2.418 51.304 87.528 ;
     RECT  51.304 71.904 51.365 80.472 ;
     RECT  51.304 6.672 51.401 9.672 ;
     RECT  51.304 58.512 51.437 70.872 ;
     RECT  51.304 45.744 51.443 57.432 ;
     RECT  51.365 75.696 51.509 80.472 ;
     RECT  51.437 58.512 51.581 65.304 ;
     RECT  51.304 81.552 51.581 82.968 ;
     RECT  51.401 6.672 51.635 8.184 ;
     RECT  51.581 81.552 51.689 82.728 ;
     RECT  51.304 20.544 51.725 44.76 ;
     RECT  51.689 81.648 51.725 82.728 ;
     RECT  51.304 84.096 51.761 87.528 ;
     RECT  51.635 6.672 51.797 7.752 ;
     RECT  51.401 9.264 51.833 9.672 ;
     RECT  51.443 48.384 51.905 57.432 ;
     RECT  51.797 6.816 51.941 7.752 ;
     RECT  51.725 20.544 51.941 37.08 ;
     RECT  51.437 66.48 51.941 70.872 ;
     RECT  51.365 71.904 51.941 74.712 ;
     RECT  51.941 24.096 52.193 37.08 ;
     RECT  51.304 2.832 52.297 2.952 ;
     RECT  51.833 9.648 52.297 9.672 ;
     RECT  50.249 88.512 52.337 88.536 ;
     RECT  51.725 38.112 52.348 44.76 ;
     RECT  52.297 2.832 52.369 3.336 ;
     RECT  51.304 4.464 52.369 5.544 ;
     RECT  51.941 71.904 52.369 72.312 ;
     RECT  51.761 84.096 52.369 87.48 ;
     RECT  52.348 38.16 52.405 44.76 ;
     RECT  51.443 45.744 52.405 47.16 ;
     RECT  52.193 24.144 52.417 37.08 ;
     RECT  51.509 76.896 52.453 80.472 ;
     RECT  51.304 11.376 52.477 12.888 ;
     RECT  51.304 14.16 52.477 19.08 ;
     RECT  51.725 81.696 52.481 82.728 ;
     RECT  51.581 58.656 52.513 65.304 ;
     RECT  51.941 66.48 52.513 70.104 ;
     RECT  52.405 38.16 52.549 47.16 ;
     RECT  51.905 48.384 52.549 49.752 ;
     RECT  52.481 81.936 52.549 82.728 ;
     RECT  52.369 83.808 52.549 87.48 ;
     RECT  52.549 81.936 52.553 87.48 ;
     RECT  52.297 9.648 52.589 10.344 ;
     RECT  52.417 24.144 52.589 36.84 ;
     RECT  52.553 82.608 52.661 87.48 ;
     RECT  52.549 38.16 52.684 49.752 ;
     RECT  51.941 7.392 52.729 7.752 ;
     RECT  51.509 75.696 52.729 75.816 ;
     RECT  52.453 76.896 52.729 80.664 ;
     RECT  52.729 7.392 52.769 7.992 ;
     RECT  51.941 73.488 52.805 74.712 ;
     RECT  52.477 11.376 52.837 19.08 ;
     RECT  52.589 36.48 52.877 36.84 ;
     RECT  52.684 38.16 52.913 49.56 ;
     RECT  51.905 50.784 52.981 57.432 ;
     RECT  52.513 58.656 52.981 70.104 ;
     RECT  52.369 2.832 53.017 5.544 ;
     RECT  52.589 9.648 53.017 9.672 ;
     RECT  52.981 50.784 53.017 70.104 ;
     RECT  52.369 71.184 53.017 72.312 ;
     RECT  52.661 82.608 53.057 86.904 ;
     RECT  51.941 20.544 53.089 23.112 ;
     RECT  52.729 75.696 53.093 80.664 ;
     RECT  53.017 2.304 53.125 5.544 ;
     RECT  53.017 9.36 53.165 9.672 ;
     RECT  53.089 20.544 53.233 23.16 ;
     RECT  52.589 24.144 53.233 35.448 ;
     RECT  53.125 2.304 53.269 6.024 ;
     RECT  53.269 2.304 53.273 6.312 ;
     RECT  53.057 82.656 53.273 86.904 ;
     RECT  53.093 75.84 53.377 80.664 ;
     RECT  53.233 20.544 53.417 35.448 ;
     RECT  53.417 20.544 53.459 30.984 ;
     RECT  53.273 2.832 53.525 6.312 ;
     RECT  52.837 10.656 53.557 19.08 ;
     RECT  52.913 38.16 53.629 47.832 ;
     RECT  53.557 9.696 53.669 19.08 ;
     RECT  53.017 50.784 53.701 72.312 ;
     RECT  52.805 73.488 53.701 74.472 ;
     RECT  53.417 32.064 53.737 35.448 ;
     RECT  52.877 36.48 53.737 36.696 ;
     RECT  53.737 32.064 53.777 36.696 ;
     RECT  53.701 50.784 53.845 74.472 ;
     RECT  53.459 20.544 53.849 30.648 ;
     RECT  52.769 7.584 53.917 7.992 ;
     RECT  53.777 35.424 53.953 36.696 ;
     RECT  53.629 37.872 53.953 47.832 ;
     RECT  52.913 49.008 53.953 49.56 ;
     RECT  53.849 20.544 53.957 29.016 ;
     RECT  53.669 19.056 53.989 19.08 ;
     RECT  53.957 20.544 53.989 28.968 ;
     RECT  53.953 35.424 53.989 47.832 ;
     RECT  53.953 49.008 53.989 49.608 ;
     RECT  53.845 50.784 53.989 74.664 ;
     RECT  53.525 2.832 53.993 2.856 ;
     RECT  53.989 50.736 53.993 74.664 ;
     RECT  53.989 19.056 54.029 28.968 ;
     RECT  53.917 7.488 54.065 7.992 ;
     RECT  53.377 75.84 54.197 80.904 ;
     RECT  54.065 7.488 54.241 7.944 ;
     RECT  53.993 50.736 54.241 74.616 ;
     RECT  54.029 19.056 54.281 26.76 ;
     RECT  54.197 75.84 54.281 81.48 ;
     RECT  53.525 4.08 54.349 6.312 ;
     RECT  54.241 7.44 54.349 7.944 ;
     RECT  53.273 84.288 54.353 86.904 ;
     RECT  54.349 4.08 54.389 7.944 ;
     RECT  53.669 9.696 54.421 17.64 ;
     RECT  53.849 30.288 54.565 30.648 ;
     RECT  53.777 32.064 54.565 34.2 ;
     RECT  54.281 20.4 54.569 26.76 ;
     RECT  54.389 4.56 54.605 7.944 ;
     RECT  54.421 9.264 54.637 17.64 ;
     RECT  54.241 50.688 54.707 74.616 ;
     RECT  54.637 9.216 54.749 17.64 ;
     RECT  54.565 30.288 54.781 34.2 ;
     RECT  53.989 35.424 54.781 49.608 ;
     RECT  54.605 4.56 54.821 5.208 ;
     RECT  54.707 72.336 54.821 74.616 ;
     RECT  54.749 12.48 54.857 17.64 ;
     RECT  54.569 20.4 54.857 26.664 ;
     RECT  54.781 30.288 54.889 49.608 ;
     RECT  54.707 50.688 54.889 71.16 ;
     RECT  54.889 30.288 54.929 71.16 ;
     RECT  54.821 72.816 54.965 74.616 ;
     RECT  54.605 6.384 55.033 7.944 ;
     RECT  54.749 9.216 55.033 10.92 ;
     RECT  54.857 13.104 55.037 17.64 ;
     RECT  54.281 75.84 55.037 80.904 ;
     RECT  54.929 30.288 55.043 51.288 ;
     RECT  55.037 13.92 55.073 17.64 ;
     RECT  54.281 19.056 55.105 19.08 ;
     RECT  54.965 72.912 55.105 74.616 ;
     RECT  55.073 14.016 55.109 14.184 ;
     RECT  55.043 30.288 55.181 49.608 ;
     RECT  54.929 52.464 55.253 71.16 ;
     RECT  55.105 18.768 55.285 19.08 ;
     RECT  55.037 79.68 55.285 80.904 ;
     RECT  55.181 30.288 55.289 49.368 ;
     RECT  54.029 28.272 55.321 28.968 ;
     RECT  55.289 30.288 55.321 49.032 ;
     RECT  55.321 28.272 55.361 49.032 ;
     RECT  55.285 79.68 55.369 81 ;
     RECT  55.253 52.464 55.397 66.12 ;
     RECT  55.105 72.912 55.397 74.76 ;
     RECT  55.361 28.272 55.537 32.712 ;
     RECT  54.857 20.64 55.645 26.664 ;
     RECT  55.537 27.648 55.645 32.712 ;
     RECT  55.249 3.408 55.753 3.432 ;
     RECT  55.753 2.256 55.82 3.432 ;
     RECT  55.82 2.256 55.861 3.864 ;
     RECT  54.821 4.992 55.861 5.016 ;
     RECT  53.273 82.656 55.861 83.256 ;
     RECT  54.353 84.288 55.861 86.52 ;
     RECT  55.073 15.456 55.933 17.64 ;
     RECT  55.285 18.768 55.933 19.272 ;
     RECT  55.397 73.104 56.041 74.76 ;
     RECT  55.037 75.84 56.041 78.552 ;
     RECT  55.369 79.68 56.041 80.904 ;
     RECT  55.109 14.112 56.113 14.184 ;
     RECT  55.645 20.64 56.113 32.712 ;
     RECT  55.033 6.384 56.149 10.92 ;
     RECT  55.861 2.256 56.185 5.016 ;
     RECT  56.185 2.256 56.293 5.064 ;
     RECT  55.397 52.464 56.401 60.984 ;
     RECT  55.397 62.16 56.401 66.12 ;
     RECT  56.293 2.256 56.408 5.16 ;
     RECT  56.149 6.384 56.408 10.968 ;
     RECT  56.113 13.392 56.408 14.184 ;
     RECT  55.933 15.456 56.408 19.272 ;
     RECT  56.113 20.592 56.408 32.712 ;
     RECT  55.361 33.84 56.408 48.984 ;
     RECT  55.043 50.592 56.408 51.288 ;
     RECT  56.401 52.464 56.408 66.12 ;
     RECT  55.253 67.104 56.408 71.16 ;
     RECT  56.041 73.104 56.408 80.904 ;
     RECT  55.861 82.656 56.408 86.52 ;
     RECT  56.408 2.148 56.512 86.52 ;
     RECT  56.512 2.418 56.704 86.52 ;
     RECT  56.704 6.384 56.765 11.928 ;
     RECT  56.704 32.928 56.765 44.76 ;
     RECT  56.704 75.936 56.873 80.904 ;
     RECT  56.765 6.912 56.981 11.928 ;
     RECT  56.765 35.76 56.989 44.76 ;
     RECT  56.704 12.96 57.011 19.272 ;
     RECT  56.765 32.928 57.017 34.776 ;
     RECT  56.704 67.104 57.059 71.16 ;
     RECT  56.981 6.912 57.089 11.832 ;
     RECT  56.704 48.144 57.161 57.576 ;
     RECT  57.011 12.96 57.233 18.264 ;
     RECT  57.161 49.824 57.233 57.576 ;
     RECT  56.704 58.656 57.244 65.688 ;
     RECT  57.089 6.912 57.377 7.656 ;
     RECT  56.704 81.888 57.377 86.52 ;
     RECT  56.704 2.496 57.413 2.52 ;
     RECT  57.233 50.064 57.413 57.576 ;
     RECT  57.244 58.944 57.485 65.688 ;
     RECT  56.704 20.592 57.529 29.16 ;
     RECT  56.873 75.936 57.593 79.224 ;
     RECT  57.485 58.944 57.629 61.368 ;
     RECT  57.017 32.928 57.665 34.68 ;
     RECT  57.377 81.888 57.733 83.208 ;
     RECT  57.665 32.928 57.737 34.488 ;
     RECT  57.011 19.248 57.773 19.272 ;
     RECT  57.413 50.064 57.773 57.144 ;
     RECT  56.704 72.384 57.781 74.76 ;
     RECT  57.593 75.936 57.781 79.176 ;
     RECT  57.161 48.144 57.805 48.696 ;
     RECT  57.529 20.592 57.809 29.064 ;
     RECT  57.089 8.688 57.845 11.832 ;
     RECT  57.485 62.4 57.845 65.688 ;
     RECT  57.845 62.448 57.877 65.688 ;
     RECT  57.059 67.104 57.877 69.576 ;
     RECT  57.059 70.656 57.877 71.16 ;
     RECT  57.773 50.064 57.881 53.256 ;
     RECT  56.989 35.808 57.884 44.76 ;
     RECT  56.704 45.792 57.884 46.632 ;
     RECT  57.884 35.808 57.971 46.632 ;
     RECT  56.704 30.192 57.985 30.648 ;
     RECT  57.877 70.656 57.985 71.256 ;
     RECT  57.233 13.008 58.057 18.264 ;
     RECT  57.971 45.84 58.093 46.632 ;
     RECT  57.733 81.456 58.097 83.208 ;
     RECT  57.809 20.592 58.163 29.016 ;
     RECT  57.845 11.376 58.169 11.832 ;
     RECT  57.985 30.192 58.169 30.696 ;
     RECT  57.737 32.928 58.169 34.44 ;
     RECT  57.877 62.448 58.201 69.576 ;
     RECT  57.985 70.656 58.201 71.304 ;
     RECT  58.163 20.592 58.205 26.76 ;
     RECT  58.169 30.384 58.237 30.696 ;
     RECT  57.377 84.336 58.241 86.52 ;
     RECT  57.781 72.384 58.273 79.176 ;
     RECT  58.205 20.592 58.309 23.112 ;
     RECT  57.805 47.712 58.309 48.696 ;
     RECT  57.881 50.064 58.309 53.064 ;
     RECT  58.273 72.288 58.313 79.176 ;
     RECT  58.201 62.448 58.345 71.304 ;
     RECT  58.313 72.288 58.345 74.76 ;
     RECT  58.057 13.008 58.349 18.696 ;
     RECT  58.169 11.376 58.413 11.736 ;
     RECT  57.845 8.688 58.457 10.2 ;
     RECT  58.349 13.008 58.493 13.176 ;
     RECT  58.313 75.84 58.493 79.176 ;
     RECT  58.309 80.352 58.501 80.376 ;
     RECT  58.237 30.384 58.601 31.224 ;
     RECT  57.629 58.992 58.633 61.368 ;
     RECT  58.501 80.352 58.637 80.52 ;
     RECT  56.704 4.656 58.669 5.352 ;
     RECT  58.097 81.888 58.705 83.208 ;
     RECT  58.241 84.336 58.705 86.28 ;
     RECT  57.971 35.808 58.709 44.76 ;
     RECT  57.773 54.576 58.741 57.144 ;
     RECT  58.349 14.832 58.745 18.696 ;
     RECT  58.741 54.336 58.777 57.144 ;
     RECT  58.709 35.952 58.781 37.032 ;
     RECT  58.633 58.992 58.813 61.464 ;
     RECT  58.601 31.2 58.849 31.224 ;
     RECT  58.813 58.896 58.849 61.464 ;
     RECT  58.309 20.496 58.957 23.112 ;
     RECT  58.309 47.712 58.957 53.064 ;
     RECT  58.777 54.336 58.957 57.768 ;
     RECT  58.669 4.272 58.993 5.352 ;
     RECT  58.093 45.84 58.993 46.68 ;
     RECT  58.957 47.712 58.993 57.768 ;
     RECT  58.457 8.928 59.029 10.2 ;
     RECT  58.745 15.072 59.029 18.696 ;
     RECT  58.957 19.776 59.029 23.112 ;
     RECT  58.993 45.84 59.101 57.768 ;
     RECT  58.849 58.752 59.101 61.464 ;
     RECT  58.993 3.984 59.173 5.352 ;
     RECT  58.205 24.432 59.173 26.76 ;
     RECT  58.163 28.032 59.173 29.016 ;
     RECT  58.709 38.16 59.173 44.76 ;
     RECT  59.101 45.84 59.173 61.464 ;
     RECT  58.345 62.448 59.173 74.76 ;
     RECT  59.173 24.432 59.177 29.016 ;
     RECT  59.173 3.984 59.209 5.4 ;
     RECT  57.377 7.2 59.209 7.656 ;
     RECT  59.177 24.48 59.209 29.016 ;
     RECT  58.849 31.2 59.221 31.32 ;
     RECT  58.169 32.928 59.221 34.2 ;
     RECT  58.705 81.888 59.249 86.28 ;
     RECT  59.173 38.16 59.267 74.76 ;
     RECT  59.249 81.888 59.281 85.56 ;
     RECT  59.267 38.16 59.285 55.752 ;
     RECT  59.221 31.2 59.317 34.2 ;
     RECT  59.281 81.792 59.317 85.56 ;
     RECT  59.285 46.608 59.321 55.752 ;
     RECT  59.276 80.208 59.363 80.232 ;
     RECT  59.267 56.832 59.393 74.76 ;
     RECT  59.209 6.816 59.461 7.656 ;
     RECT  59.029 8.928 59.461 10.44 ;
     RECT  59.317 81.648 59.501 85.56 ;
     RECT  59.461 6.816 59.509 7.896 ;
     RECT  59.461 8.928 59.509 10.728 ;
     RECT  58.493 75.84 59.573 76.632 ;
     RECT  59.509 6.816 59.596 10.728 ;
     RECT  59.501 81.648 59.605 82.68 ;
     RECT  59.285 38.16 59.609 45.336 ;
     RECT  59.317 31.2 59.641 34.248 ;
     RECT  59.393 56.832 59.717 74.712 ;
     RECT  59.641 31.2 59.725 34.536 ;
     RECT  59.029 15.072 59.749 23.112 ;
     RECT  59.573 75.84 59.753 76.584 ;
     RECT  59.749 15.072 59.821 23.304 ;
     RECT  59.717 56.88 59.833 74.712 ;
     RECT  59.605 81.216 59.833 82.68 ;
     RECT  58.781 36 59.857 37.032 ;
     RECT  58.493 13.104 59.861 13.176 ;
     RECT  59.501 83.76 59.861 85.56 ;
     RECT  59.596 9.024 59.893 10.728 ;
     RECT  58.413 11.712 59.893 11.736 ;
     RECT  59.833 56.88 59.897 74.088 ;
     RECT  59.821 14.4 59.933 23.304 ;
     RECT  59.725 31.2 59.965 34.392 ;
     RECT  58.493 77.616 59.969 79.176 ;
     RECT  59.861 83.76 59.969 84.936 ;
     RECT  59.861 13.104 60.113 13.128 ;
     RECT  59.969 78.144 60.113 79.176 ;
     RECT  59.209 3.984 60.217 5.688 ;
     RECT  59.596 6.816 60.217 7.944 ;
     RECT  59.321 48.384 60.253 55.752 ;
     RECT  59.893 9.024 60.329 11.736 ;
     RECT  60.253 48.384 60.329 55.848 ;
     RECT  59.969 83.76 60.329 84.216 ;
     RECT  59.321 46.608 60.332 47.304 ;
     RECT  59.857 35.952 60.361 37.032 ;
     RECT  59.609 38.16 60.361 39.24 ;
     RECT  59.933 14.832 60.397 23.304 ;
     RECT  59.209 24.48 60.397 29.64 ;
     RECT  59.833 81.216 60.397 81.912 ;
     RECT  60.329 83.76 60.401 83.832 ;
     RECT  59.609 40.56 60.419 45.336 ;
     RECT  60.329 9.888 60.428 11.736 ;
     RECT  59.897 56.88 60.46 72.312 ;
     RECT  60.217 3.984 60.473 7.944 ;
     RECT  60.397 80.496 60.505 81.912 ;
     RECT  60.332 46.416 60.541 47.304 ;
     RECT  60.397 14.832 60.581 29.64 ;
     RECT  60.46 56.88 60.581 72.264 ;
     RECT  60.581 21.456 60.611 29.64 ;
     RECT  60.505 79.68 60.652 81.912 ;
     RECT  60.473 4.32 60.685 7.944 ;
     RECT  59.965 30.624 60.721 34.392 ;
     RECT  60.685 4.32 60.797 8.088 ;
     RECT  60.329 52.704 60.865 55.848 ;
     RECT  60.581 56.88 60.865 69.528 ;
     RECT  60.652 79.728 60.937 81.912 ;
     RECT  60.611 28.224 60.997 29.64 ;
     RECT  60.721 30.624 60.997 34.968 ;
     RECT  59.753 76.224 61.153 76.584 ;
     RECT  60.428 9.888 61.225 11.976 ;
     RECT  60.997 28.224 61.261 34.968 ;
     RECT  60.361 35.952 61.261 39.24 ;
     RECT  60.419 40.56 61.261 44.952 ;
     RECT  61.153 76.224 61.261 76.824 ;
     RECT  61.225 9.888 61.405 12.072 ;
     RECT  61.261 13.056 61.405 13.08 ;
     RECT  61.261 75.264 61.405 76.824 ;
     RECT  61.261 28.224 61.477 44.952 ;
     RECT  60.541 45.984 61.477 47.304 ;
     RECT  59.897 73.392 61.477 74.088 ;
     RECT  60.401 83.808 61.513 83.832 ;
     RECT  60.581 14.832 61.549 20.088 ;
     RECT  61.549 14.784 61.573 20.088 ;
     RECT  61.513 83.808 61.585 84.6 ;
     RECT  61.405 9.888 61.621 13.08 ;
     RECT  61.621 9.888 61.669 13.656 ;
     RECT  61.573 14.64 61.669 20.088 ;
     RECT  60.581 70.656 61.693 72.264 ;
     RECT  61.477 73.392 61.693 74.136 ;
     RECT  60.797 4.32 61.808 7.992 ;
     RECT  61.669 9.888 61.808 20.088 ;
     RECT  60.611 21.456 61.808 27.24 ;
     RECT  61.477 28.224 61.808 47.304 ;
     RECT  60.329 48.384 61.808 51.288 ;
     RECT  60.865 52.704 61.808 69.528 ;
     RECT  61.693 70.656 61.808 74.136 ;
     RECT  61.405 75.264 61.808 77.064 ;
     RECT  60.113 78.144 61.808 78.696 ;
     RECT  60.937 79.728 61.808 82.392 ;
     RECT  61.585 83.808 61.808 85.512 ;
     RECT  61.808 2.148 61.912 86.412 ;
     RECT  61.912 2.418 62.104 86.142 ;
     RECT  62.104 62.16 62.165 67.848 ;
     RECT  62.104 14.736 62.201 18.456 ;
     RECT  62.104 52.704 62.237 54.792 ;
     RECT  62.104 56.736 62.273 58.248 ;
     RECT  62.104 59.28 62.309 61.128 ;
     RECT  62.104 9.552 62.345 12.36 ;
     RECT  62.104 70.656 62.489 72.984 ;
     RECT  62.104 84.336 62.525 85.512 ;
     RECT  62.104 36 62.561 50.904 ;
     RECT  62.561 36 62.633 50.568 ;
     RECT  62.489 70.704 62.633 72.984 ;
     RECT  62.104 76.272 62.633 81.48 ;
     RECT  62.633 36 62.669 36.36 ;
     RECT  62.633 78.192 62.669 81.48 ;
     RECT  62.633 70.8 62.705 72.984 ;
     RECT  62.669 78.192 62.741 80.904 ;
     RECT  62.633 37.584 62.813 50.568 ;
     RECT  62.741 78.192 62.813 80.856 ;
     RECT  62.309 60.384 62.819 61.128 ;
     RECT  62.104 68.88 62.849 69.528 ;
     RECT  62.104 74.064 62.885 75.048 ;
     RECT  62.633 76.272 62.885 76.824 ;
     RECT  62.104 4.368 62.921 6.024 ;
     RECT  62.104 28.224 62.963 34.632 ;
     RECT  62.885 74.112 62.993 75.048 ;
     RECT  62.849 68.88 63.029 69.336 ;
     RECT  62.813 79.728 63.029 80.856 ;
     RECT  62.104 82.464 63.029 83.208 ;
     RECT  62.963 28.704 63.065 34.632 ;
     RECT  62.993 74.112 63.065 75 ;
     RECT  62.885 76.272 63.097 76.296 ;
     RECT  62.201 14.784 63.101 18.456 ;
     RECT  62.813 78.192 63.101 78.696 ;
     RECT  62.525 84.336 63.101 84.6 ;
     RECT  62.669 36 63.133 36.312 ;
     RECT  63.065 28.992 63.137 34.632 ;
     RECT  62.921 5.088 63.164 6.024 ;
     RECT  62.104 7.056 63.164 8.184 ;
     RECT  62.165 62.64 63.169 67.848 ;
     RECT  62.104 13.584 63.173 13.608 ;
     RECT  63.137 30.768 63.173 34.632 ;
     RECT  62.104 20.064 63.241 20.424 ;
     RECT  62.104 21.456 63.241 21.72 ;
     RECT  62.104 23.856 63.245 26.664 ;
     RECT  62.813 37.584 63.245 50.04 ;
     RECT  63.164 5.088 63.251 8.184 ;
     RECT  63.245 24.48 63.277 26.664 ;
     RECT  62.309 59.28 63.313 59.4 ;
     RECT  62.819 60.384 63.313 60.888 ;
     RECT  62.705 71.52 63.317 72.984 ;
     RECT  63.251 5.088 63.353 6.024 ;
     RECT  62.237 52.8 63.385 54.792 ;
     RECT  62.273 56.736 63.385 57.912 ;
     RECT  63.353 5.616 63.389 6.024 ;
     RECT  62.345 9.552 63.497 12.072 ;
     RECT  63.101 84.576 63.529 84.6 ;
     RECT  63.385 52.8 63.565 57.912 ;
     RECT  63.313 59.28 63.565 60.888 ;
     RECT  63.101 78.192 63.601 78.36 ;
     RECT  63.173 31.2 63.673 34.632 ;
     RECT  63.133 35.664 63.673 36.312 ;
     RECT  63.169 61.968 63.685 67.848 ;
     RECT  63.029 68.88 63.685 69.288 ;
     RECT  62.104 22.704 63.709 22.728 ;
     RECT  63.685 61.968 63.731 69.288 ;
     RECT  63.101 14.88 63.817 18.456 ;
     RECT  63.277 24.48 63.817 26.808 ;
     RECT  63.097 76.08 63.925 76.296 ;
     RECT  63.709 13.104 64.033 13.128 ;
     RECT  63.251 7.056 64.037 8.184 ;
     RECT  63.497 9.552 64.069 11.304 ;
     RECT  63.565 52.8 64.073 60.888 ;
     RECT  63.029 83.184 64.076 83.208 ;
     RECT  63.529 84.576 64.076 85.512 ;
     RECT  63.245 37.584 64.145 49.56 ;
     RECT  63.731 61.968 64.145 68.184 ;
     RECT  64.069 9.072 64.153 11.304 ;
     RECT  63.241 20.064 64.177 21.72 ;
     RECT  63.709 22.704 64.177 23.016 ;
     RECT  64.073 59.328 64.177 60.888 ;
     RECT  64.145 61.968 64.177 62.664 ;
     RECT  64.037 7.056 64.181 8.088 ;
     RECT  63.925 73.104 64.213 73.128 ;
     RECT  63.065 74.64 64.213 75 ;
     RECT  63.817 14.88 64.285 18.648 ;
     RECT  64.073 52.8 64.285 57.96 ;
     RECT  63.029 80.352 64.325 80.376 ;
     RECT  63.389 5.616 64.357 5.64 ;
     RECT  64.181 7.056 64.357 7.8 ;
     RECT  63.925 76.08 64.357 76.392 ;
     RECT  63.601 77.424 64.357 78.36 ;
     RECT  64.357 76.08 64.403 79.272 ;
     RECT  64.285 14.88 64.405 18.792 ;
     RECT  64.405 14.832 64.412 18.792 ;
     RECT  64.177 20.064 64.433 23.016 ;
     RECT  64.213 73.104 64.433 75 ;
     RECT  64.033 12.72 64.537 13.128 ;
     RECT  64.412 14.544 64.537 18.792 ;
     RECT  64.357 5.616 64.54 7.8 ;
     RECT  64.145 37.824 64.54 49.56 ;
     RECT  63.817 24.48 64.573 27.24 ;
     RECT  64.54 37.824 64.613 48.456 ;
     RECT  64.433 73.104 64.613 74.664 ;
     RECT  63.137 28.992 64.645 29.784 ;
     RECT  64.433 22.992 64.649 23.016 ;
     RECT  64.076 83.184 64.649 85.512 ;
     RECT  63.673 31.2 64.717 36.408 ;
     RECT  64.649 83.184 64.721 84.6 ;
     RECT  64.645 28.992 64.753 29.832 ;
     RECT  64.153 9.6 64.793 11.304 ;
     RECT  64.573 24.144 64.835 27.24 ;
     RECT  64.403 78.048 64.861 79.272 ;
     RECT  64.613 38.112 64.865 48.456 ;
     RECT  64.613 73.104 64.897 74.52 ;
     RECT  64.835 26.256 64.933 27.24 ;
     RECT  64.753 28.56 64.933 29.832 ;
     RECT  63.731 69.264 64.969 69.288 ;
     RECT  64.933 26.256 64.973 29.832 ;
     RECT  64.969 69.264 65.005 69.432 ;
     RECT  64.897 73.008 65.005 74.52 ;
     RECT  65.005 72.96 65.009 74.52 ;
     RECT  64.145 63.792 65.036 68.184 ;
     RECT  65.005 69.264 65.036 69.528 ;
     RECT  64.537 12.72 65.081 18.792 ;
     RECT  65.036 63.792 65.081 69.528 ;
     RECT  64.835 24.144 65.113 25.128 ;
     RECT  64.285 52.752 65.113 57.96 ;
     RECT  64.865 38.112 65.117 46.536 ;
     RECT  65.081 63.792 65.117 65.928 ;
     RECT  64.721 83.424 65.189 84.6 ;
     RECT  64.973 26.352 65.221 29.832 ;
     RECT  64.54 6.24 65.225 7.8 ;
     RECT  65.113 23.952 65.225 25.128 ;
     RECT  65.081 12.72 65.257 18.696 ;
     RECT  65.225 6.24 65.261 7.416 ;
     RECT  64.717 31.2 65.261 36.456 ;
     RECT  64.403 76.08 65.297 76.92 ;
     RECT  64.177 59.328 65.329 62.664 ;
     RECT  64.793 10.176 65.365 11.304 ;
     RECT  65.257 12.48 65.365 18.696 ;
     RECT  65.261 6.24 65.369 7.32 ;
     RECT  64.861 78.048 65.369 79.848 ;
     RECT  65.297 76.272 65.411 76.92 ;
     RECT  65.189 83.424 65.411 83.448 ;
     RECT  65.189 84.576 65.411 84.6 ;
     RECT  65.117 38.112 65.521 38.808 ;
     RECT  65.225 23.952 65.585 24.936 ;
     RECT  65.117 39.792 65.585 46.536 ;
     RECT  65.369 79.776 65.585 79.848 ;
     RECT  65.369 78.048 65.617 78.744 ;
     RECT  65.081 67.056 65.621 69.528 ;
     RECT  65.329 59.28 65.653 62.664 ;
     RECT  65.117 63.792 65.653 65.688 ;
     RECT  65.365 10.176 65.657 18.696 ;
     RECT  65.585 24 65.693 24.936 ;
     RECT  65.617 77.52 65.701 78.744 ;
     RECT  65.221 26.352 65.729 29.928 ;
     RECT  65.585 39.792 65.765 41.208 ;
     RECT  65.521 38.112 65.797 38.664 ;
     RECT  65.113 52.56 65.797 57.96 ;
     RECT  65.653 59.28 65.797 65.688 ;
     RECT  65.261 35.952 65.833 36.456 ;
     RECT  65.221 50.736 65.869 50.76 ;
     RECT  65.621 67.056 65.873 67.128 ;
     RECT  64.54 49.536 65.905 49.56 ;
     RECT  65.869 50.736 65.905 51.192 ;
     RECT  65.657 10.608 65.945 18.696 ;
     RECT  65.585 42.384 65.948 46.536 ;
     RECT  65.833 35.952 65.977 36.552 ;
     RECT  65.797 37.584 65.977 38.664 ;
     RECT  64.433 20.16 66.013 21.672 ;
     RECT  65.945 11.952 66.017 18.696 ;
     RECT  65.729 26.352 66.025 29.688 ;
     RECT  65.948 42.384 66.053 46.776 ;
     RECT  65.989 8.832 66.076 8.856 ;
     RECT  65.797 52.56 66.085 65.688 ;
     RECT  64.865 47.904 66.092 48.456 ;
     RECT  65.905 49.536 66.092 51.192 ;
     RECT  65.009 72.96 66.121 73.128 ;
     RECT  66.121 72.96 66.229 73.32 ;
     RECT  65.977 35.952 66.233 38.664 ;
     RECT  65.693 24.144 66.332 24.936 ;
     RECT  66.025 26.352 66.332 29.064 ;
     RECT  66.013 20.16 66.337 22.056 ;
     RECT  66.092 47.904 66.337 51.192 ;
     RECT  66.017 15.936 66.476 18.696 ;
     RECT  66.337 19.872 66.476 22.056 ;
     RECT  65.369 6.288 66.553 7.32 ;
     RECT  66.233 35.952 66.553 38.184 ;
     RECT  66.476 15.936 66.661 22.056 ;
     RECT  66.229 72.72 66.661 73.32 ;
     RECT  65.617 70.848 66.697 70.872 ;
     RECT  66.332 24.144 66.769 29.064 ;
     RECT  65.261 31.2 66.769 34.776 ;
     RECT  66.053 42.432 66.877 46.776 ;
     RECT  66.337 47.904 66.877 51.288 ;
     RECT  65.621 68.16 66.977 69.528 ;
     RECT  66.697 70.848 66.977 71.496 ;
     RECT  66.769 31.104 66.985 34.776 ;
     RECT  66.977 68.16 67.045 71.496 ;
     RECT  66.661 72.528 67.045 73.368 ;
     RECT  66.661 15.936 67.057 22.248 ;
     RECT  67.045 68.16 67.057 73.368 ;
     RECT  65.009 74.496 67.057 74.52 ;
     RECT  65.765 39.792 67.093 41.16 ;
     RECT  66.877 42.432 67.093 51.288 ;
     RECT  67.057 68.16 67.093 74.52 ;
     RECT  65.701 77.952 67.093 78.744 ;
     RECT  66.769 23.952 67.129 29.064 ;
     RECT  66.985 30.144 67.129 34.776 ;
     RECT  66.085 52.56 67.129 66.312 ;
     RECT  67.093 68.16 67.165 74.616 ;
     RECT  66.553 6.288 67.208 8.328 ;
     RECT  65.945 10.608 67.208 10.632 ;
     RECT  66.017 11.952 67.208 14.856 ;
     RECT  67.057 15.936 67.208 22.776 ;
     RECT  67.129 23.952 67.208 34.776 ;
     RECT  66.553 35.856 67.208 38.184 ;
     RECT  67.093 39.792 67.208 51.288 ;
     RECT  67.129 52.512 67.208 66.312 ;
     RECT  67.165 67.296 67.208 74.616 ;
     RECT  65.411 76.272 67.208 76.392 ;
     RECT  67.093 77.904 67.208 78.744 ;
     RECT  65.585 79.776 67.208 79.8 ;
     RECT  67.208 2.148 67.312 86.412 ;
     RECT  67.312 2.418 67.504 86.142 ;
     RECT  67.504 47.424 67.619 54.456 ;
     RECT  67.504 10.128 67.637 10.632 ;
     RECT  67.637 10.608 67.673 10.632 ;
     RECT  67.504 19.392 67.673 22.824 ;
     RECT  67.504 76.272 67.709 79.752 ;
     RECT  67.673 19.392 67.715 21.816 ;
     RECT  67.709 76.8 67.817 79.752 ;
     RECT  67.504 55.488 67.853 69.528 ;
     RECT  67.504 23.952 67.889 27.432 ;
     RECT  67.504 12.384 67.925 16.968 ;
     RECT  67.619 47.424 67.925 54.36 ;
     RECT  67.853 62.784 67.997 69.528 ;
     RECT  67.817 77.904 68.099 79.752 ;
     RECT  67.925 47.424 68.105 51.384 ;
     RECT  68.099 79.728 68.14 79.752 ;
     RECT  67.673 22.8 68.141 22.824 ;
     RECT  67.889 23.952 68.141 26.712 ;
     RECT  68.105 48.672 68.177 51.384 ;
     RECT  67.504 31.92 68.213 46.104 ;
     RECT  68.099 77.904 68.429 78.648 ;
     RECT  67.925 15.36 68.435 16.968 ;
     RECT  68.435 15.984 68.485 16.968 ;
     RECT  67.504 18 68.485 18.216 ;
     RECT  67.715 19.392 68.485 21.672 ;
     RECT  67.997 66.048 68.485 69.528 ;
     RECT  68.485 15.984 68.531 21.672 ;
     RECT  67.925 12.384 68.537 13.704 ;
     RECT  67.504 71.472 68.605 73.56 ;
     RECT  68.531 15.984 68.645 18.888 ;
     RECT  68.177 48.672 68.645 49.512 ;
     RECT  68.645 15.984 68.681 17.496 ;
     RECT  67.925 52.512 68.713 54.36 ;
     RECT  67.853 55.488 68.713 61.512 ;
     RECT  68.681 15.984 68.771 16.632 ;
     RECT  68.605 71.472 68.785 73.704 ;
     RECT  68.213 44.16 68.825 46.104 ;
     RECT  68.825 46.08 68.861 46.104 ;
     RECT  68.785 70.896 68.897 73.704 ;
     RECT  67.504 80.88 68.897 80.904 ;
     RECT  68.213 31.92 68.965 43.176 ;
     RECT  67.504 28.464 68.969 30.168 ;
     RECT  68.141 26.112 69.001 26.712 ;
     RECT  69.001 26.112 69.005 26.808 ;
     RECT  68.713 52.512 69.005 61.512 ;
     RECT  68.771 15.984 69.041 16.536 ;
     RECT  67.817 76.8 69.041 76.824 ;
     RECT  68.969 28.512 69.077 30.168 ;
     RECT  68.965 31.152 69.149 43.176 ;
     RECT  68.141 23.952 69.155 25.128 ;
     RECT  69.149 31.152 69.155 39.096 ;
     RECT  68.105 47.424 69.217 47.496 ;
     RECT  68.825 44.16 69.221 45 ;
     RECT  68.537 12.912 69.401 13.704 ;
     RECT  69.077 28.512 69.437 29.352 ;
     RECT  68.177 50.688 69.469 51.384 ;
     RECT  69.005 52.512 69.469 52.872 ;
     RECT  68.645 18.864 69.493 18.888 ;
     RECT  68.821 75.216 69.493 75.24 ;
     RECT  68.531 20.112 69.509 21.672 ;
     RECT  69.469 50.688 69.509 52.872 ;
     RECT  68.897 70.896 69.509 71.928 ;
     RECT  69.401 12.912 69.539 12.936 ;
     RECT  69.509 20.352 69.539 21.672 ;
     RECT  68.429 77.952 69.539 78.648 ;
     RECT  67.997 62.784 69.541 64.92 ;
     RECT  69.539 78.624 69.541 78.648 ;
     RECT  69.155 23.952 69.548 25.08 ;
     RECT  69.548 23.856 69.577 25.08 ;
     RECT  69.541 78.624 69.587 78.744 ;
     RECT  68.897 73.008 69.617 73.704 ;
     RECT  69.493 18.864 69.685 18.936 ;
     RECT  69.155 31.296 69.725 39.096 ;
     RECT  69.509 71.904 69.725 71.928 ;
     RECT  69.685 18.24 69.757 18.936 ;
     RECT  69.109 79.92 69.757 79.944 ;
     RECT  69.041 15.984 69.833 16.344 ;
     RECT  69.149 40.176 69.833 43.176 ;
     RECT  69.541 62.784 69.833 65.016 ;
     RECT  68.645 49.056 69.865 49.368 ;
     RECT  69.509 50.688 69.865 50.712 ;
     RECT  69.757 17.664 69.937 18.936 ;
     RECT  69.833 64.08 70.045 65.016 ;
     RECT  68.485 66.048 70.045 69.912 ;
     RECT  69.833 42.72 70.117 43.176 ;
     RECT  69.005 54.096 70.117 61.512 ;
     RECT  69.833 62.784 70.117 63.096 ;
     RECT  69.577 23.328 70.121 25.08 ;
     RECT  69.937 17.664 70.157 19.368 ;
     RECT  69.865 49.056 70.157 50.712 ;
     RECT  69.685 76.272 70.189 76.392 ;
     RECT  70.109 80.928 70.193 80.952 ;
     RECT  69.725 38.112 70.225 39.096 ;
     RECT  69.833 40.176 70.225 41.688 ;
     RECT  70.117 42.72 70.225 43.224 ;
     RECT  69.221 44.304 70.225 45 ;
     RECT  70.157 18.24 70.265 19.368 ;
     RECT  69.539 20.352 70.265 20.568 ;
     RECT  69.217 47.28 70.297 47.496 ;
     RECT  70.157 49.056 70.297 49.896 ;
     RECT  70.297 47.28 70.301 49.896 ;
     RECT  70.121 23.328 70.333 24.456 ;
     RECT  70.265 20.352 70.337 20.376 ;
     RECT  69.833 16.32 70.373 16.344 ;
     RECT  70.225 42.72 70.409 45 ;
     RECT  70.045 64.08 70.409 69.912 ;
     RECT  69.725 31.296 70.445 37.128 ;
     RECT  69.509 51.696 70.501 52.872 ;
     RECT  70.117 54.096 70.517 63.096 ;
     RECT  69.587 78.72 70.556 78.744 ;
     RECT  69.757 79.728 70.556 79.944 ;
     RECT  69.437 28.8 70.585 29.352 ;
     RECT  69.509 70.896 70.585 70.92 ;
     RECT  70.501 51.696 70.588 53.016 ;
     RECT  70.517 54.096 70.589 56.808 ;
     RECT  70.585 28.176 70.621 29.352 ;
     RECT  69.617 73.008 70.625 73.464 ;
     RECT  70.556 78.72 70.643 79.944 ;
     RECT  70.621 27.888 70.657 29.352 ;
     RECT  70.643 78.72 70.661 78.744 ;
     RECT  69.539 21.648 70.693 21.672 ;
     RECT  70.333 22.704 70.693 24.456 ;
     RECT  70.693 21.648 70.697 24.456 ;
     RECT  69.005 26.592 70.729 26.808 ;
     RECT  70.657 27.888 70.729 29.64 ;
     RECT  70.588 51.696 70.733 52.584 ;
     RECT  70.733 51.696 70.765 52.488 ;
     RECT  70.265 18.24 70.769 18.408 ;
     RECT  70.225 38.112 70.769 41.688 ;
     RECT  70.301 47.28 70.805 48.456 ;
     RECT  70.625 73.248 70.805 73.464 ;
     RECT  70.769 18.24 70.877 18.264 ;
     RECT  70.729 26.592 70.933 29.64 ;
     RECT  70.765 78.672 70.949 78.696 ;
     RECT  70.643 79.92 70.949 79.944 ;
     RECT  70.769 41.472 70.981 41.688 ;
     RECT  70.409 42.72 70.981 44.904 ;
     RECT  70.697 22.176 71.021 24.36 ;
     RECT  70.409 64.896 71.021 69.912 ;
     RECT  71.021 22.704 71.027 24.36 ;
     RECT  70.445 31.92 71.036 37.128 ;
     RECT  70.769 38.112 71.036 40.2 ;
     RECT  70.933 26.448 71.053 29.64 ;
     RECT  69.493 75.12 71.089 75.24 ;
     RECT  70.189 76.272 71.089 76.776 ;
     RECT  70.805 48.432 71.093 48.456 ;
     RECT  71.036 31.92 71.123 40.2 ;
     RECT  71.123 31.92 71.129 37.032 ;
     RECT  71.053 25.632 71.171 29.64 ;
     RECT  70.805 73.344 71.201 73.464 ;
     RECT  71.123 38.4 71.273 40.2 ;
     RECT  70.981 41.472 71.273 44.904 ;
     RECT  71.171 25.632 71.315 28.2 ;
     RECT  71.273 42.72 71.345 44.904 ;
     RECT  71.089 75.12 71.372 76.776 ;
     RECT  71.273 41.472 71.381 41.64 ;
     RECT  70.301 49.872 71.413 49.896 ;
     RECT  71.027 22.8 71.417 24.36 ;
     RECT  71.381 41.472 71.417 41.496 ;
     RECT  71.171 29.616 71.453 29.64 ;
     RECT  71.129 31.92 71.453 36.552 ;
     RECT  70.765 51.408 71.453 52.488 ;
     RECT  71.372 75.12 71.459 77.304 ;
     RECT  70.589 54.096 71.485 56.376 ;
     RECT  71.273 39.84 71.489 40.2 ;
     RECT  70.585 70.896 71.489 71.832 ;
     RECT  71.413 49.872 71.521 50.184 ;
     RECT  70.517 58.272 71.555 63.096 ;
     RECT  71.021 64.896 71.593 66.312 ;
     RECT  71.417 22.8 71.597 22.824 ;
     RECT  71.417 24.336 71.597 24.36 ;
     RECT  71.315 25.632 71.597 27.96 ;
     RECT  71.453 51.696 71.597 52.488 ;
     RECT  71.555 60.384 71.708 63.096 ;
     RECT  71.593 64.128 71.708 66.312 ;
     RECT  71.489 40.176 71.917 40.2 ;
     RECT  71.485 53.568 71.953 56.376 ;
     RECT  71.555 58.272 71.953 59.208 ;
     RECT  71.201 73.344 71.989 73.368 ;
     RECT  71.708 60.384 72.169 66.312 ;
     RECT  71.021 67.488 72.169 69.912 ;
     RECT  71.989 72.912 72.236 73.368 ;
     RECT  72.236 72.912 72.277 73.992 ;
     RECT  71.459 75.12 72.277 76.392 ;
     RECT  71.845 30.816 72.349 30.84 ;
     RECT  72.169 60.384 72.349 69.912 ;
     RECT  71.489 70.896 72.349 71.784 ;
     RECT  71.273 38.4 72.457 38.424 ;
     RECT  72.349 29.712 72.469 30.84 ;
     RECT  71.917 40.176 72.469 40.536 ;
     RECT  71.597 51.696 72.601 52.056 ;
     RECT  71.597 25.632 72.608 25.848 ;
     RECT  71.597 26.832 72.608 27.96 ;
     RECT  72.469 28.992 72.608 30.84 ;
     RECT  71.453 32.16 72.608 36.552 ;
     RECT  72.457 38.16 72.608 38.424 ;
     RECT  72.469 40.176 72.608 41.16 ;
     RECT  71.345 42.816 72.608 44.904 ;
     RECT  71.941 46.08 72.608 46.104 ;
     RECT  71.053 47.184 72.608 47.208 ;
     RECT  71.521 48.912 72.608 50.184 ;
     RECT  72.601 51.216 72.608 52.056 ;
     RECT  71.953 53.568 72.608 57 ;
     RECT  71.953 58.128 72.608 59.208 ;
     RECT  72.349 60.384 72.608 71.784 ;
     RECT  72.277 72.816 72.608 76.392 ;
     RECT  71.593 78.624 72.608 78.648 ;
     RECT  72.608 2.148 72.712 86.412 ;
     RECT  72.712 2.418 72.904 86.142 ;
     RECT  72.904 26.88 72.965 26.904 ;
     RECT  72.904 35.184 72.965 35.208 ;
     RECT  72.904 60.96 72.965 64.728 ;
     RECT  72.904 32.88 73.001 34.104 ;
     RECT  72.904 40.608 73.001 41.16 ;
     RECT  72.965 60.96 73.091 62.04 ;
     RECT  72.904 42.72 73.109 43.08 ;
     RECT  72.904 66.096 73.109 66.6 ;
     RECT  73.091 60.96 73.132 61.032 ;
     RECT  72.904 67.776 73.235 69 ;
     RECT  72.904 50.448 73.289 54.744 ;
     RECT  73.109 42.72 73.397 42.744 ;
     RECT  73.001 40.608 73.469 40.632 ;
     RECT  72.965 63.216 73.469 64.728 ;
     RECT  73.289 50.448 73.523 51.24 ;
     RECT  73.289 52.416 73.571 54.744 ;
     RECT  73.523 50.448 73.613 50.472 ;
     RECT  72.904 56.352 73.613 56.616 ;
     RECT  73.613 56.592 73.969 56.616 ;
     RECT  72.904 58.272 73.969 59.208 ;
     RECT  72.904 72.816 73.973 74.088 ;
     RECT  73.969 58.272 74.041 59.592 ;
     RECT  73.571 52.992 74.045 53.016 ;
     RECT  73.132 61.008 74.113 61.032 ;
     RECT  73.091 62.016 74.113 62.04 ;
     RECT  73.469 63.216 74.113 64.344 ;
     RECT  73.571 54.096 74.221 54.744 ;
     RECT  73.109 66.096 74.221 66.12 ;
     RECT  73.235 67.776 74.221 68.904 ;
     RECT  74.221 66.096 74.293 68.904 ;
     RECT  74.041 58.272 74.329 59.64 ;
     RECT  74.113 61.008 74.329 64.344 ;
     RECT  72.904 70.368 74.329 70.392 ;
     RECT  74.329 58.272 74.333 64.344 ;
     RECT  74.333 58.272 74.369 63.288 ;
     RECT  73.969 56.592 74.405 56.856 ;
     RECT  74.405 56.832 74.437 56.856 ;
     RECT  74.369 61.968 74.549 63.288 ;
     RECT  74.549 61.968 74.657 62.712 ;
     RECT  74.329 70.368 74.677 70.728 ;
     RECT  74.657 62.016 74.693 62.712 ;
     RECT  74.677 70.08 74.723 70.728 ;
     RECT  74.723 70.08 74.764 70.632 ;
     RECT  74.437 56.832 74.801 57.096 ;
     RECT  74.221 54.096 74.837 55.032 ;
     RECT  74.764 70.368 74.837 70.632 ;
     RECT  73.973 72.816 74.909 73.512 ;
     RECT  74.909 73.056 74.945 73.512 ;
     RECT  74.293 66.096 74.981 69.048 ;
     RECT  74.837 54.144 75.161 55.032 ;
     RECT  74.981 66.096 75.337 68.472 ;
     RECT  75.337 65.904 75.341 68.472 ;
     RECT  75.161 54.144 75.377 54.504 ;
     RECT  75.341 67.104 75.449 68.472 ;
     RECT  75.377 54.48 75.485 54.504 ;
     RECT  75.449 67.104 75.521 68.376 ;
     RECT  74.369 58.272 75.625 60.408 ;
     RECT  75.521 67.248 75.629 68.376 ;
     RECT  74.801 57.072 75.733 57.096 ;
     RECT  75.625 58.224 75.733 60.408 ;
     RECT  75.341 65.904 75.737 66.12 ;
     RECT  74.693 62.016 75.841 62.04 ;
     RECT  75.841 61.824 75.917 62.04 ;
     RECT  75.733 57.072 75.985 60.408 ;
     RECT  75.917 61.824 75.985 61.848 ;
     RECT  74.945 73.488 75.989 73.512 ;
     RECT  75.985 57.072 76.025 61.848 ;
     RECT  75.629 67.248 76.061 68.184 ;
     RECT  75.877 55.968 76.097 55.992 ;
     RECT  76.025 60.96 76.169 61.848 ;
     RECT  76.061 68.16 76.205 68.184 ;
     RECT  74.333 64.32 76.273 64.344 ;
     RECT  76.025 57.072 76.313 59.592 ;
     RECT  76.169 60.96 76.349 61.704 ;
     RECT  74.837 70.608 76.357 70.632 ;
     RECT  76.273 64.176 77.18 64.344 ;
     RECT  77.18 63.696 77.201 64.344 ;
     RECT  76.313 57.072 77.276 58.728 ;
     RECT  77.029 69.456 77.281 69.48 ;
     RECT  76.357 70.608 77.281 71.256 ;
     RECT  76.349 60.96 77.317 60.984 ;
     RECT  75.737 66.096 77.509 66.12 ;
     RECT  73.001 32.88 78.008 33.912 ;
     RECT  77.029 55.44 78.008 55.464 ;
     RECT  77.276 57.072 78.008 59.448 ;
     RECT  77.317 60.528 78.008 60.984 ;
     RECT  77.201 63.696 78.008 65.064 ;
     RECT  77.509 66.096 78.008 66.936 ;
     RECT  77.173 68.4 78.008 68.424 ;
     RECT  77.281 69.456 78.008 71.256 ;
     RECT  76.345 72.384 78.008 72.408 ;
     RECT  78.008 2.148 78.112 86.412 ;
     RECT  78.112 2.418 78.304 86.142 ;
     RECT  78.304 32.88 83.408 33.912 ;
     RECT  83.408 2.148 83.512 86.412 ;
     RECT  83.512 2.418 83.704 86.142 ;
     RECT  83.704 32.88 85.025 33.912 ;
     RECT  85.025 32.88 87.181 33.096 ;
     RECT  87.181 32.88 88.524 33.288 ;
    LAYER M5 ;
     RECT  2.4 2.137 2.52 2.151 ;
     RECT  7.8 2.137 7.92 2.151 ;
     RECT  13.2 2.137 13.32 2.151 ;
     RECT  18.6 2.137 18.72 2.151 ;
     RECT  24 2.137 24.12 2.151 ;
     RECT  29.4 2.137 29.52 2.151 ;
     RECT  34.8 2.137 34.92 2.151 ;
     RECT  40.2 2.137 40.32 2.151 ;
     RECT  45.6 2.137 45.72 2.151 ;
     RECT  51 2.137 51.12 2.151 ;
     RECT  56.4 2.137 56.52 2.151 ;
     RECT  61.8 2.137 61.92 2.151 ;
     RECT  67.2 2.137 67.32 2.151 ;
     RECT  72.6 2.137 72.72 2.151 ;
     RECT  78 2.137 78.12 2.151 ;
     RECT  83.4 2.137 83.52 2.151 ;
     RECT  56.4 2.151 56.712 2.245 ;
     RECT  31.536 2.245 31.56 2.915 ;
     RECT  47.664 2.245 47.688 3.443 ;
     RECT  51 2.151 51.312 3.637 ;
     RECT  33.168 3.685 33.192 3.829 ;
     RECT  55.872 2.245 56.712 3.875 ;
     RECT  32.4 3.829 33.192 4.115 ;
     RECT  61.8 2.151 62.112 4.357 ;
     RECT  38.784 3.397 38.808 4.595 ;
     RECT  32.4 4.115 32.904 4.931 ;
     RECT  56.304 3.875 56.712 5.171 ;
     RECT  50.544 3.637 51.312 5.267 ;
     RECT  61.8 4.357 62.904 5.605 ;
     RECT  61.8 5.605 63.24 5.651 ;
     RECT  45.6 2.151 45.912 5.653 ;
     RECT  45.408 5.653 45.912 5.701 ;
     RECT  61.8 5.651 62.112 5.893 ;
     RECT  53.328 5.077 53.352 6.035 ;
     RECT  41.904 5.605 41.928 6.275 ;
     RECT  64.464 5.605 64.488 6.275 ;
     RECT  32.4 4.931 32.616 6.515 ;
     RECT  63.216 5.651 63.24 6.515 ;
     RECT  48.432 5.413 48.456 6.563 ;
     RECT  50.88 5.267 51.312 6.661 ;
     RECT  24 2.151 24.312 6.805 ;
     RECT  44.976 5.701 45.912 6.899 ;
     RECT  45.408 6.899 45.912 7.091 ;
     RECT  61.344 5.893 62.112 7.141 ;
     RECT  45.6 7.091 45.912 7.189 ;
     RECT  47.904 6.901 48.36 7.285 ;
     RECT  50.88 6.661 51.624 7.331 ;
     RECT  40.2 2.151 40.512 7.765 ;
     RECT  29.4 2.151 29.712 7.909 ;
     RECT  24 6.805 24.408 8.003 ;
     RECT  45.6 7.189 46.104 8.003 ;
     RECT  22.8 7.381 22.824 8.051 ;
     RECT  47.52 7.285 48.36 8.147 ;
     RECT  51 7.331 51.624 8.195 ;
     RECT  13.2 2.151 13.512 8.485 ;
     RECT  29.4 7.909 29.88 8.531 ;
     RECT  34.8 2.151 35.112 8.533 ;
     RECT  33.6 7.813 33.624 8.579 ;
     RECT  18.6 2.151 18.912 8.677 ;
     RECT  51 8.195 51.528 8.677 ;
     RECT  56.4 5.171 56.712 8.821 ;
     RECT  59.52 8.437 59.544 9.013 ;
     RECT  59.28 9.013 59.544 9.059 ;
     RECT  45.6 8.003 45.912 9.061 ;
     RECT  47.904 8.147 48.36 9.061 ;
     RECT  59.28 9.059 59.304 9.155 ;
     RECT  50.736 8.677 51.528 9.299 ;
     RECT  26.304 7.909 26.328 9.683 ;
     RECT  45.6 9.061 46.296 9.731 ;
     RECT  53.904 7.957 53.928 9.731 ;
     RECT  56.4 8.821 57 9.779 ;
     RECT  50.736 9.299 51.312 9.925 ;
     RECT  34.8 8.533 36.024 10.117 ;
     RECT  32.4 6.515 32.424 10.213 ;
     RECT  34.8 10.117 36.6 10.307 ;
     RECT  40.08 7.765 40.512 10.307 ;
     RECT  64.08 9.061 64.104 10.307 ;
     RECT  36.576 10.307 36.6 10.309 ;
     RECT  32.4 10.213 33.192 10.355 ;
     RECT  60.96 7.141 62.112 10.405 ;
     RECT  60.48 10.405 62.112 10.451 ;
     RECT  66 8.821 66.024 10.643 ;
     RECT  13.2 8.485 13.608 10.691 ;
     RECT  27.072 10.069 27.096 10.693 ;
     RECT  11.76 8.197 11.784 10.741 ;
     RECT  11.712 10.741 11.784 10.789 ;
     RECT  18.6 8.677 19.032 10.789 ;
     RECT  26.736 10.693 27.096 10.835 ;
     RECT  33.168 10.355 33.192 10.835 ;
     RECT  50.688 9.925 51.312 10.883 ;
     RECT  56.4 9.779 56.712 10.933 ;
     RECT  18.6 10.789 19.992 11.027 ;
     RECT  39.168 10.885 39.192 11.123 ;
     RECT  64.8 10.309 64.824 11.269 ;
     RECT  47.904 9.061 48.696 11.363 ;
     RECT  7.8 2.151 8.112 11.365 ;
     RECT  58.32 10.165 58.344 11.411 ;
     RECT  11.712 10.789 12.024 11.459 ;
     RECT  13.2 10.691 13.512 11.845 ;
     RECT  14.784 10.261 14.808 11.845 ;
     RECT  56.4 10.933 56.808 11.939 ;
     RECT  47.904 11.363 48.36 11.941 ;
     RECT  67.2 2.151 67.512 11.941 ;
     RECT  11.712 11.459 11.736 12.035 ;
     RECT  27.072 10.835 27.096 12.035 ;
     RECT  0.144 11.365 0.168 12.083 ;
     RECT  18.6 11.027 19.032 12.085 ;
     RECT  64.8 11.269 65.4 12.227 ;
     RECT  31.152 10.501 31.176 12.229 ;
     RECT  47.856 11.941 48.36 12.373 ;
     RECT  20.112 11.749 20.136 12.419 ;
     RECT  13.2 11.845 14.808 12.467 ;
     RECT  18.48 12.085 19.032 12.515 ;
     RECT  52.416 11.365 52.44 12.515 ;
     RECT  24 8.003 24.312 12.565 ;
     RECT  30.72 12.229 32.088 12.755 ;
     RECT  24 12.565 24.456 12.803 ;
     RECT  0.24 12.709 0.312 12.805 ;
     RECT  47.76 12.373 48.36 12.949 ;
     RECT  16.944 12.661 16.968 12.995 ;
     RECT  56.4 11.939 56.712 12.997 ;
     RECT  7.8 11.365 8.328 13.045 ;
     RECT  11.664 12.325 11.688 13.045 ;
     RECT  13.2 12.467 13.944 13.045 ;
     RECT  61.8 10.451 62.112 13.045 ;
     RECT  40.2 10.307 40.512 13.093 ;
     RECT  64.8 12.227 64.824 13.093 ;
     RECT  10.272 12.517 10.296 13.283 ;
     RECT  47.472 12.949 48.36 13.283 ;
     RECT  36.576 10.309 37.368 13.573 ;
     RECT  0.24 12.805 0.36 13.715 ;
     RECT  11.664 13.045 13.944 13.715 ;
     RECT  31.152 12.755 32.088 13.811 ;
     RECT  17.232 13.045 17.256 13.813 ;
     RECT  18.6 12.515 19.032 13.813 ;
     RECT  7.8 13.045 9.096 13.859 ;
     RECT  17.232 13.813 19.032 13.859 ;
     RECT  45.6 9.731 45.912 13.861 ;
     RECT  0.24 13.715 0.312 13.909 ;
     RECT  7.8 13.859 8.52 14.387 ;
     RECT  7.8 14.387 8.328 14.483 ;
     RECT  24 12.803 24.312 14.485 ;
     RECT  42.192 13.621 42.216 14.485 ;
     RECT  44.928 13.861 45.912 14.485 ;
     RECT  47.76 13.283 48.36 14.485 ;
     RECT  64.608 13.093 64.824 14.533 ;
     RECT  41.856 14.485 42.216 14.627 ;
     RECT  61.68 13.045 62.112 14.629 ;
     RECT  2.4 2.151 2.712 14.677 ;
     RECT  44.928 14.485 46.44 14.771 ;
     RECT  23.136 14.485 24.312 14.773 ;
     RECT  47.76 14.485 48.744 14.773 ;
     RECT  61.584 14.629 62.112 14.819 ;
     RECT  56.4 12.997 56.856 14.821 ;
     RECT  64.464 14.533 64.824 14.821 ;
     RECT  66.384 11.941 67.512 14.821 ;
     RECT  10.32 14.341 10.344 14.867 ;
     RECT  20.016 14.197 20.04 14.867 ;
     RECT  36.336 13.573 37.368 14.867 ;
     RECT  7.8 14.483 8.112 14.917 ;
     RECT  61.8 14.819 62.112 14.917 ;
     RECT  17.616 13.859 19.032 15.349 ;
     RECT  34.8 10.307 35.112 15.349 ;
     RECT  36.336 14.867 36.6 15.349 ;
     RECT  64.416 14.821 67.512 15.349 ;
     RECT  0.144 13.909 0.312 15.443 ;
     RECT  2.4 14.677 2.856 15.443 ;
     RECT  7.68 14.917 8.112 15.443 ;
     RECT  61.8 14.917 62.568 15.443 ;
     RECT  64.416 15.349 68.424 15.443 ;
     RECT  17.616 15.349 19.8 15.491 ;
     RECT  33.792 14.677 33.816 15.491 ;
     RECT  60.48 10.451 60.504 15.491 ;
     RECT  22.752 14.773 24.312 15.493 ;
     RECT  22.752 15.493 24.408 15.539 ;
     RECT  40.2 13.093 40.776 15.587 ;
     RECT  31.152 13.811 31.176 15.589 ;
     RECT  15.36 14.485 15.384 15.731 ;
     RECT  27.312 15.301 27.336 15.781 ;
     RECT  34.8 15.349 36.6 15.875 ;
     RECT  11.664 13.715 11.688 15.877 ;
     RECT  27.216 15.781 27.336 15.877 ;
     RECT  27.216 15.877 28.248 15.923 ;
     RECT  18.6 15.491 19.8 15.973 ;
     RECT  44.928 14.771 45.912 15.973 ;
     RECT  0.24 15.443 0.312 16.019 ;
     RECT  27.312 15.923 28.248 16.019 ;
     RECT  56.4 14.821 57.816 16.019 ;
     RECT  66.144 15.443 68.424 16.019 ;
     RECT  69.504 12.901 69.528 16.021 ;
     RECT  66.144 16.019 67.512 16.067 ;
     RECT  47.76 14.773 49.128 16.069 ;
     RECT  0.288 16.019 0.312 16.115 ;
     RECT  44.928 15.973 46.104 16.115 ;
     RECT  44.976 16.115 46.104 16.117 ;
     RECT  47.76 16.069 49.56 16.117 ;
     RECT  64.416 15.443 64.824 16.163 ;
     RECT  22.752 15.539 22.776 16.259 ;
     RECT  11.424 15.877 11.688 16.357 ;
     RECT  13.2 13.715 13.944 16.357 ;
     RECT  44.976 16.117 49.56 16.403 ;
     RECT  31.152 15.589 31.944 16.405 ;
     RECT  40.2 15.587 40.512 16.405 ;
     RECT  2.4 15.443 2.808 16.501 ;
     RECT  24 15.539 24.408 16.501 ;
     RECT  38.064 16.069 38.088 16.501 ;
     RECT  34.8 15.875 35.544 16.595 ;
     RECT  5.616 13.621 5.64 16.645 ;
     RECT  29.4 8.531 29.712 16.789 ;
     RECT  31.152 16.405 32.856 16.789 ;
     RECT  29.4 16.789 32.856 16.885 ;
     RECT  28.224 16.019 28.248 17.027 ;
     RECT  39.792 16.405 40.512 17.029 ;
     RECT  51 10.883 51.312 17.029 ;
     RECT  47.04 16.403 49.56 17.075 ;
     RECT  29.4 16.885 33.048 17.123 ;
     RECT  44.976 16.403 46.008 17.123 ;
     RECT  64.464 16.163 64.824 17.125 ;
     RECT  11.424 16.357 13.944 17.219 ;
     RECT  63.792 17.125 64.824 17.219 ;
     RECT  56.4 16.019 57.336 17.315 ;
     RECT  7.8 15.443 8.112 17.461 ;
     RECT  68.736 16.021 69.528 17.461 ;
     RECT  47.04 17.075 49.128 17.651 ;
     RECT  50.832 17.029 51.312 17.843 ;
     RECT  45.6 17.123 46.008 17.941 ;
     RECT  63.792 17.219 63.816 17.941 ;
     RECT  63.552 17.941 63.816 17.987 ;
     RECT  66.144 16.067 66.168 18.037 ;
     RECT  67.2 16.067 67.512 18.037 ;
     RECT  66.144 18.037 67.512 18.083 ;
     RECT  29.4 17.123 32.808 18.179 ;
     RECT  17.568 18.133 17.592 18.181 ;
     RECT  18.6 15.973 19.992 18.181 ;
     RECT  30.768 18.179 32.808 18.181 ;
     RECT  5.088 16.645 5.64 18.227 ;
     RECT  2.304 16.501 2.808 18.275 ;
     RECT  47.76 17.651 49.128 18.323 ;
     RECT  56.4 17.315 57 18.323 ;
     RECT  27.936 17.029 27.96 18.421 ;
     RECT  27.936 18.421 28.392 18.467 ;
     RECT  17.568 18.181 20.04 18.565 ;
     RECT  37.584 16.501 38.088 18.611 ;
     RECT  39.312 17.029 40.512 18.611 ;
     RECT  13.2 17.219 13.944 18.661 ;
     RECT  39.792 18.611 40.512 18.661 ;
     RECT  41.856 14.627 41.88 18.661 ;
     RECT  17.568 18.565 20.568 18.755 ;
     RECT  7.8 17.461 8.712 18.803 ;
     RECT  2.304 18.275 2.712 18.851 ;
     RECT  20.016 18.755 20.568 18.851 ;
     RECT  17.568 18.755 19.032 18.899 ;
     RECT  44.448 18.181 44.472 18.995 ;
     RECT  38.064 18.611 38.088 19.331 ;
     RECT  36.576 15.875 36.6 19.333 ;
     RECT  68.496 17.461 69.528 19.333 ;
     RECT  30.768 18.181 33.096 19.427 ;
     RECT  68.496 19.333 70.152 19.427 ;
     RECT  5.328 18.227 5.64 19.475 ;
     RECT  24 16.501 25.08 19.477 ;
     RECT  26.112 19.093 26.136 19.477 ;
     RECT  45.6 17.941 46.776 19.523 ;
     RECT  28.368 18.467 28.392 19.621 ;
     RECT  29.4 18.179 29.712 19.621 ;
     RECT  43.392 16.981 43.416 19.621 ;
     RECT  20.544 18.851 20.568 19.667 ;
     RECT  39.792 18.661 41.88 19.667 ;
     RECT  34.8 16.595 35.112 19.909 ;
     RECT  17.616 18.899 19.032 20.003 ;
     RECT  54.144 19.093 54.168 20.003 ;
     RECT  5.616 19.475 5.64 20.005 ;
     RECT  13.2 18.661 14.232 20.051 ;
     RECT  5.616 20.005 5.688 20.147 ;
     RECT  11.424 17.219 12.168 20.147 ;
     RECT  66.528 18.083 67.512 20.147 ;
     RECT  28.368 19.621 29.712 20.245 ;
     RECT  30.768 19.427 32.472 20.245 ;
     RECT  68.736 19.427 70.152 20.291 ;
     RECT  28.368 20.245 32.472 20.339 ;
     RECT  64.8 17.219 64.824 20.341 ;
     RECT  34.8 19.909 35.208 20.389 ;
     RECT  36.576 19.333 36.792 20.389 ;
     RECT  7.8 18.803 8.112 20.437 ;
     RECT  64.8 20.341 65.016 20.437 ;
     RECT  17.952 20.003 19.032 20.579 ;
     RECT  69.504 20.291 70.152 20.579 ;
     RECT  56.4 18.323 56.808 20.627 ;
     RECT  60.48 19.429 60.504 20.627 ;
     RECT  12.048 20.147 12.168 20.675 ;
     RECT  39.792 19.667 40.512 20.677 ;
     RECT  41.856 19.667 41.88 20.677 ;
     RECT  24 19.477 26.136 20.771 ;
     RECT  24 20.771 25.944 20.819 ;
     RECT  69.504 20.579 69.528 20.867 ;
     RECT  0.144 18.565 0.168 21.013 ;
     RECT  5.664 20.147 5.688 21.109 ;
     RECT  5.664 21.109 5.88 21.155 ;
     RECT  63.552 17.987 63.576 21.155 ;
     RECT  43.344 19.621 43.416 21.251 ;
     RECT  38.784 20.533 38.808 21.397 ;
     RECT  67.104 20.147 67.512 21.397 ;
     RECT  68.496 21.061 68.52 21.397 ;
     RECT  67.104 21.397 68.52 21.443 ;
     RECT  28.368 20.339 32.28 21.539 ;
     RECT  38.448 21.397 38.808 21.539 ;
     RECT  28.368 21.539 31.512 21.635 ;
     RECT  51 17.843 51.312 21.637 ;
     RECT  0.144 21.013 0.216 21.683 ;
     RECT  28.368 21.635 30.072 21.683 ;
     RECT  31.488 21.635 31.512 21.683 ;
     RECT  58.32 20.485 58.344 21.683 ;
     RECT  64.8 20.437 65.304 21.683 ;
     RECT  27.264 19.765 27.288 21.925 ;
     RECT  38.784 21.539 38.808 21.971 ;
     RECT  17.952 20.579 18.912 22.021 ;
     RECT  12.048 20.675 12.072 22.067 ;
     RECT  7.632 20.437 8.112 22.165 ;
     RECT  34.8 20.389 36.792 22.165 ;
     RECT  10.896 21.301 10.92 22.211 ;
     RECT  34.8 22.165 37.032 22.307 ;
     RECT  39.792 20.677 41.88 22.307 ;
     RECT  26.928 21.925 27.288 22.499 ;
     RECT  50.688 21.637 51.312 22.547 ;
     RECT  28.56 21.683 30.072 22.691 ;
     RECT  70.704 22.165 70.728 22.693 ;
     RECT  70.704 22.693 71.016 22.739 ;
     RECT  24 20.819 24.456 22.741 ;
     RECT  5.856 21.155 5.88 22.835 ;
     RECT  17.952 22.021 19.512 22.835 ;
     RECT  43.92 21.829 43.944 22.835 ;
     RECT  67.2 21.443 68.52 22.835 ;
     RECT  70.992 22.739 71.016 22.835 ;
     RECT  0.144 21.683 0.168 23.029 ;
     RECT  39.792 22.307 40.632 23.075 ;
     RECT  27.264 22.499 27.288 23.317 ;
     RECT  51 22.547 51.312 23.317 ;
     RECT  22.704 21.781 22.728 23.363 ;
     RECT  33.408 23.125 33.432 23.365 ;
     RECT  7.632 22.165 8.424 23.411 ;
     RECT  0.144 23.029 0.216 23.557 ;
     RECT  13.2 20.051 13.944 23.653 ;
     RECT  34.8 22.307 36.792 23.749 ;
     RECT  45.6 19.523 45.912 23.893 ;
     RECT  49.488 19.333 49.512 23.893 ;
     RECT  38.784 23.701 38.808 23.939 ;
     RECT  43.536 23.317 43.56 23.939 ;
     RECT  53.52 22.501 53.544 23.939 ;
     RECT  34.8 23.749 37.032 23.941 ;
     RECT  60.768 23.029 60.792 23.941 ;
     RECT  61.8 15.443 62.112 23.941 ;
     RECT  60.768 23.941 62.112 23.987 ;
     RECT  6.24 23.893 6.264 24.083 ;
     RECT  32.544 23.365 33.432 24.131 ;
     RECT  45.6 23.893 46.44 24.133 ;
     RECT  47.76 18.323 48.168 24.133 ;
     RECT  49.488 23.893 49.608 24.325 ;
     RECT  49.488 24.325 49.848 24.371 ;
     RECT  0.144 23.557 0.552 24.467 ;
     RECT  13.2 23.653 14.856 24.515 ;
     RECT  27.264 23.317 27.912 24.515 ;
     RECT  13.2 24.515 13.944 24.517 ;
     RECT  39.792 23.075 40.512 24.517 ;
     RECT  59.472 10.693 59.496 24.517 ;
     RECT  4.464 23.701 4.488 24.611 ;
     RECT  61.68 23.987 62.112 24.659 ;
     RECT  28.896 22.691 30.072 24.803 ;
     RECT  31.872 24.517 31.896 24.901 ;
     RECT  41.856 22.307 41.88 24.901 ;
     RECT  45.6 24.133 48.168 24.901 ;
     RECT  34.704 23.941 37.032 24.947 ;
     RECT  18.6 22.835 19.512 25.045 ;
     RECT  54.672 23.845 54.696 25.091 ;
     RECT  69.6 23.845 69.624 25.091 ;
     RECT  68.496 22.835 68.52 25.093 ;
     RECT  0.144 24.467 0.408 25.139 ;
     RECT  27.264 24.515 27.288 25.139 ;
     RECT  31.344 24.901 31.896 25.139 ;
     RECT  41.856 24.901 42.312 25.139 ;
     RECT  58.704 24.517 59.496 25.187 ;
     RECT  0.24 25.139 0.408 25.235 ;
     RECT  34.8 24.947 37.032 25.237 ;
     RECT  45.312 24.901 48.168 25.427 ;
     RECT  56.4 20.627 56.712 25.477 ;
     RECT  17.856 25.045 19.512 25.573 ;
     RECT  21.024 21.829 21.048 25.573 ;
     RECT  45.312 25.427 46.296 25.573 ;
     RECT  67.2 22.835 67.512 25.573 ;
     RECT  2.4 18.851 2.712 25.621 ;
     RECT  12.432 24.517 13.944 25.621 ;
     RECT  61.8 24.659 62.112 25.621 ;
     RECT  12.432 25.621 13.992 25.667 ;
     RECT  17.856 25.573 21.048 25.667 ;
     RECT  47.328 25.427 48.168 25.669 ;
     RECT  49.824 24.371 49.848 25.669 ;
     RECT  64.8 21.683 64.824 25.669 ;
     RECT  34.8 25.237 37.08 25.715 ;
     RECT  47.328 25.669 49.848 25.715 ;
     RECT  64.656 25.669 64.824 25.715 ;
     RECT  51 23.317 51.624 25.717 ;
     RECT  64.656 25.715 64.68 25.717 ;
     RECT  7.632 23.411 8.232 25.859 ;
     RECT  7.68 25.859 8.232 26.101 ;
     RECT  18.6 25.667 21.048 26.149 ;
     RECT  29.4 24.803 30.072 26.149 ;
     RECT  25.92 20.819 25.944 26.197 ;
     RECT  39.792 24.517 40.824 26.197 ;
     RECT  53.424 25.045 53.448 26.197 ;
     RECT  0.24 25.235 0.264 26.243 ;
     RECT  7.68 26.101 9.048 26.243 ;
     RECT  33.408 24.131 33.432 26.243 ;
     RECT  68.496 25.093 69.144 26.243 ;
     RECT  63.792 25.717 64.68 26.291 ;
     RECT  7.68 26.243 8.232 26.387 ;
     RECT  66.384 25.573 67.512 26.435 ;
     RECT  2.304 25.621 2.808 26.437 ;
     RECT  47.328 25.715 47.832 26.723 ;
     RECT  13.2 25.667 13.992 26.725 ;
     RECT  45.024 25.573 46.296 26.771 ;
     RECT  13.2 26.725 14.328 26.773 ;
     RECT  48.912 25.715 49.848 26.773 ;
     RECT  51 25.717 51.864 26.773 ;
     RECT  2.304 26.437 2.856 26.819 ;
     RECT  39.792 26.197 40.872 26.867 ;
     RECT  18.6 26.149 21.912 26.869 ;
     RECT  31.344 25.139 31.368 27.013 ;
     RECT  31.344 27.013 31.704 27.059 ;
     RECT  47.328 26.723 47.784 27.059 ;
     RECT  12.96 26.773 14.328 27.109 ;
     RECT  29.088 26.149 30.072 27.203 ;
     RECT  45.264 26.771 46.296 27.251 ;
     RECT  29.088 27.203 29.88 27.299 ;
     RECT  45.312 27.251 46.296 27.299 ;
     RECT  7.8 26.387 8.232 27.301 ;
     RECT  9.36 26.581 9.384 27.301 ;
     RECT  39.792 26.867 40.68 27.301 ;
     RECT  41.856 25.139 41.88 27.301 ;
     RECT  43.008 26.773 43.032 27.301 ;
     RECT  72.6 2.151 72.912 27.301 ;
     RECT  64.656 26.291 64.68 27.349 ;
     RECT  2.4 26.819 2.856 27.395 ;
     RECT  48.768 26.773 51.864 27.395 ;
     RECT  51 27.395 51.864 27.635 ;
     RECT  36.576 25.715 37.08 27.683 ;
     RECT  53.328 26.197 53.448 27.829 ;
     RECT  25.92 26.197 26.424 27.875 ;
     RECT  24 22.741 24.504 27.877 ;
     RECT  25.92 27.875 25.944 27.877 ;
     RECT  70.944 26.437 70.968 27.925 ;
     RECT  2.4 27.395 2.808 27.971 ;
     RECT  16.56 26.725 16.584 27.971 ;
     RECT  18.6 26.869 22.104 28.163 ;
     RECT  38.928 27.301 40.68 28.163 ;
     RECT  56.016 25.477 56.712 28.163 ;
     RECT  70.944 27.925 71.304 28.211 ;
     RECT  61.8 25.621 62.52 28.213 ;
     RECT  41.856 27.301 43.032 28.259 ;
     RECT  60.576 28.165 60.6 28.261 ;
     RECT  61.8 28.213 62.952 28.261 ;
     RECT  60.576 28.261 62.952 28.307 ;
     RECT  45.312 27.299 46.2 28.309 ;
     RECT  12.48 27.109 14.328 28.451 ;
     RECT  31.68 27.059 31.704 28.453 ;
     RECT  64.656 27.349 65.016 28.453 ;
     RECT  66.144 26.725 66.168 28.453 ;
     RECT  7.8 27.301 9.384 28.501 ;
     RECT  7.344 28.501 9.384 28.547 ;
     RECT  12.48 28.451 13.992 28.547 ;
     RECT  58.128 27.301 58.152 28.643 ;
     RECT  18.6 28.163 21.912 28.691 ;
     RECT  9.168 28.547 9.384 28.693 ;
     RECT  29.4 27.299 29.88 28.693 ;
     RECT  9.168 28.693 9.72 28.739 ;
     RECT  70.944 28.211 71.16 28.835 ;
     RECT  36.576 27.683 36.648 28.837 ;
     RECT  15.504 27.733 15.528 28.979 ;
     RECT  31.68 28.453 33.048 28.979 ;
     RECT  24 27.877 25.944 28.981 ;
     RECT  18.6 28.691 19.32 29.027 ;
     RECT  47.76 27.059 47.784 29.029 ;
     RECT  56.4 28.163 56.712 29.029 ;
     RECT  64.656 28.453 66.168 29.075 ;
     RECT  31.68 28.979 32.568 29.123 ;
     RECT  52.992 27.829 53.448 29.123 ;
     RECT  24 28.981 26.28 29.171 ;
     RECT  56.4 29.029 57.48 29.171 ;
     RECT  24 29.171 24.504 29.509 ;
     RECT  29.4 28.693 29.928 29.509 ;
     RECT  61.536 28.307 62.952 29.557 ;
     RECT  45.312 28.309 46.296 29.605 ;
     RECT  47.424 29.029 47.784 29.605 ;
     RECT  61.536 29.557 63.048 29.605 ;
     RECT  64.656 29.075 65.976 29.605 ;
     RECT  67.2 26.435 67.512 29.653 ;
     RECT  61.008 29.605 65.976 29.699 ;
     RECT  29.232 29.509 29.928 29.701 ;
     RECT  36.576 28.837 37.176 29.747 ;
     RECT  72.48 27.301 72.912 29.747 ;
     RECT  48.768 27.395 49.848 30.035 ;
     RECT  34.8 25.715 35.112 30.037 ;
     RECT  29.232 29.701 30.264 30.179 ;
     RECT  67.2 29.653 67.8 30.179 ;
     RECT  12.96 28.547 13.992 30.181 ;
     RECT  21.024 28.691 21.912 30.181 ;
     RECT  25.92 29.171 26.28 30.227 ;
     RECT  41.856 28.259 41.88 30.229 ;
     RECT  9.36 28.739 9.72 30.275 ;
     RECT  21.024 30.181 22.248 30.275 ;
     RECT  41.76 30.229 41.88 30.275 ;
     RECT  29.232 30.179 29.928 30.323 ;
     RECT  31.68 29.123 31.704 30.323 ;
     RECT  39.792 28.163 40.68 30.373 ;
     RECT  12.336 30.181 13.992 30.419 ;
     RECT  38.064 30.373 40.68 30.421 ;
     RECT  41.76 30.275 41.784 30.421 ;
     RECT  54.864 26.629 54.888 30.421 ;
     RECT  34.704 30.037 35.112 30.565 ;
     RECT  53.04 29.123 53.448 30.613 ;
     RECT  36.576 29.747 36.84 30.659 ;
     RECT  29.4 30.323 29.928 30.707 ;
     RECT  27.648 30.277 27.672 30.709 ;
     RECT  18.6 29.027 18.912 30.757 ;
     RECT  12.336 30.419 13.656 30.803 ;
     RECT  22.224 30.275 22.248 30.803 ;
     RECT  61.008 29.699 65.208 30.851 ;
     RECT  45.312 29.605 47.784 30.899 ;
     RECT  17.52 28.453 17.544 30.901 ;
     RECT  18.6 30.757 19.224 30.901 ;
     RECT  43.008 28.259 43.032 30.901 ;
     RECT  25.92 30.227 26.04 30.947 ;
     RECT  42.816 30.901 43.032 30.949 ;
     RECT  42.816 30.949 43.32 31.043 ;
     RECT  26.016 30.947 26.04 31.139 ;
     RECT  38.064 30.421 41.784 31.139 ;
     RECT  69.12 26.243 69.144 31.187 ;
     RECT  39.792 31.139 41.784 31.235 ;
     RECT  61.152 30.851 65.208 31.235 ;
     RECT  21.024 30.275 21.048 31.285 ;
     RECT  59.472 25.187 59.496 31.285 ;
     RECT  64.656 31.235 65.208 31.333 ;
     RECT  54.768 30.421 54.888 31.379 ;
     RECT  17.52 30.901 19.224 31.427 ;
     RECT  7.344 28.547 8.112 31.475 ;
     RECT  45.312 30.899 46.728 31.571 ;
     RECT  61.152 31.235 63.048 31.715 ;
     RECT  43.296 31.043 43.32 31.859 ;
     RECT  20.976 31.285 21.048 31.861 ;
     RECT  47.76 30.899 47.784 31.861 ;
     RECT  27.552 30.709 27.672 31.907 ;
     RECT  61.152 31.715 62.232 31.909 ;
     RECT  15.408 29.557 15.432 31.955 ;
     RECT  27.648 31.907 27.672 31.955 ;
     RECT  23.856 29.509 24.504 32.005 ;
     RECT  18.432 31.427 19.224 32.099 ;
     RECT  52.992 30.613 53.448 32.099 ;
     RECT  34.368 30.565 35.112 32.195 ;
     RECT  38.064 31.139 38.376 32.245 ;
     RECT  9.36 30.275 9.384 32.339 ;
     RECT  52.992 32.099 53.016 32.341 ;
     RECT  7.392 31.475 8.112 32.435 ;
     RECT  39.792 31.235 40.68 32.437 ;
     RECT  41.76 31.235 41.784 32.437 ;
     RECT  71.136 28.835 71.16 32.437 ;
     RECT  70.704 32.437 71.16 32.675 ;
     RECT  37.872 32.245 38.376 32.723 ;
     RECT  12.96 30.803 13.656 32.771 ;
     RECT  22.56 31.861 22.584 32.963 ;
     RECT  47.328 31.861 47.784 32.965 ;
     RECT  48.912 30.035 49.848 32.965 ;
     RECT  60.576 31.909 62.232 32.965 ;
     RECT  20.352 31.861 21.048 33.011 ;
     RECT  29.4 30.707 29.832 33.013 ;
     RECT  59.232 31.285 59.496 33.013 ;
     RECT  60.576 32.965 62.904 33.013 ;
     RECT  32.496 31.861 32.52 33.059 ;
     RECT  59.232 33.013 62.904 33.107 ;
     RECT  47.328 32.965 49.848 33.299 ;
     RECT  61.152 33.107 62.904 33.299 ;
     RECT  18.432 32.099 18.912 33.349 ;
     RECT  71.088 32.675 71.16 33.541 ;
     RECT  52.416 32.341 53.016 33.587 ;
     RECT  18.432 33.349 19.176 33.635 ;
     RECT  64.656 31.333 65.304 33.925 ;
     RECT  67.2 30.179 67.512 33.925 ;
     RECT  45.312 31.571 45.912 34.069 ;
     RECT  71.088 33.541 71.256 34.069 ;
     RECT  72.6 29.747 72.912 34.069 ;
     RECT  34.8 32.195 35.112 34.117 ;
     RECT  36.576 30.659 36.6 34.117 ;
     RECT  28.464 33.013 29.832 34.259 ;
     RECT  45.024 34.069 45.912 34.259 ;
     RECT  64.656 33.925 67.512 34.307 ;
     RECT  71.088 34.069 72.912 34.309 ;
     RECT  64.656 34.307 65.208 34.355 ;
     RECT  47.76 33.299 49.848 34.403 ;
     RECT  59.472 33.107 59.688 34.547 ;
     RECT  37.872 32.723 37.896 34.693 ;
     RECT  37.632 34.693 37.896 34.739 ;
     RECT  64.656 34.355 65.064 34.787 ;
     RECT  66.24 34.307 67.512 34.787 ;
     RECT  15.36 34.165 15.384 34.835 ;
     RECT  70.272 34.309 72.912 34.835 ;
     RECT  71.088 34.835 72.912 34.883 ;
     RECT  34.8 34.117 36.6 35.027 ;
     RECT  71.232 34.883 72.912 35.315 ;
     RECT  7.8 32.435 8.112 35.317 ;
     RECT  12.96 32.771 13.608 35.317 ;
     RECT  39.792 32.437 41.784 35.363 ;
     RECT  47.76 34.403 48.984 35.413 ;
     RECT  54.816 31.379 54.888 35.605 ;
     RECT  47.76 35.413 49.56 35.653 ;
     RECT  56.4 29.171 56.712 35.749 ;
     RECT  22.608 35.461 22.632 35.795 ;
     RECT  41.76 35.363 41.784 35.797 ;
     RECT  23.76 32.005 24.504 35.845 ;
     RECT  52.992 33.587 53.016 35.845 ;
     RECT  23.76 35.845 25.416 35.891 ;
     RECT  41.76 35.797 42.168 35.893 ;
     RECT  47.424 35.653 49.56 35.893 ;
     RECT  51 27.635 51.312 35.893 ;
     RECT  12.096 35.317 13.608 35.987 ;
     RECT  71.952 35.315 72.912 35.987 ;
     RECT  54.816 35.605 55.272 36.181 ;
     RECT  54.816 36.181 55.368 36.227 ;
     RECT  37.632 34.739 37.656 36.275 ;
     RECT  38.784 35.317 38.808 36.275 ;
     RECT  45.312 34.259 45.912 36.277 ;
     RECT  56.4 35.749 56.952 36.323 ;
     RECT  12.96 35.987 13.608 36.325 ;
     RECT  47.424 35.893 51.312 36.325 ;
     RECT  46.992 36.325 51.312 36.371 ;
     RECT  67.2 34.787 67.512 36.421 ;
     RECT  45.024 36.277 45.912 36.467 ;
     RECT  15.648 34.885 15.672 36.469 ;
     RECT  18.432 33.635 18.912 36.515 ;
     RECT  24 35.891 25.416 36.515 ;
     RECT  43.872 35.845 43.896 36.515 ;
     RECT  48.864 36.371 51.312 36.515 ;
     RECT  34.8 35.027 35.352 36.563 ;
     RECT  34.8 36.563 35.112 36.565 ;
     RECT  51 36.515 51.312 36.661 ;
     RECT  52.368 35.845 53.016 36.661 ;
     RECT  7.68 35.317 8.28 36.803 ;
     RECT  24 36.515 24.504 36.997 ;
     RECT  25.584 36.853 25.608 36.997 ;
     RECT  45.312 36.467 45.912 36.997 ;
     RECT  46.992 36.371 47.784 36.997 ;
     RECT  54.864 36.227 55.368 37.043 ;
     RECT  5.952 26.725 5.976 37.045 ;
     RECT  7.68 36.803 8.112 37.045 ;
     RECT  12.96 36.325 13.656 37.045 ;
     RECT  28.128 36.373 28.152 37.091 ;
     RECT  48.864 36.515 49.56 37.091 ;
     RECT  21.024 33.011 21.048 37.333 ;
     RECT  5.952 37.045 8.112 37.427 ;
     RECT  15.648 36.469 16.008 37.571 ;
     RECT  30.816 36.997 30.84 37.619 ;
     RECT  66.72 36.421 67.512 37.619 ;
     RECT  61.488 33.299 62.112 37.621 ;
     RECT  12.912 37.045 13.656 37.667 ;
     RECT  23.712 36.997 24.504 37.861 ;
     RECT  25.584 36.997 25.992 37.861 ;
     RECT  21.024 37.333 21.864 37.909 ;
     RECT  48.864 37.091 48.888 37.955 ;
     RECT  23.712 37.861 25.992 38.005 ;
     RECT  32.16 35.413 32.184 38.005 ;
     RECT  20.736 37.909 21.864 38.101 ;
     RECT  22.848 38.005 25.992 38.101 ;
     RECT  31.92 38.005 32.184 38.149 ;
     RECT  39.792 35.363 40.68 38.149 ;
     RECT  67.2 37.619 67.512 38.149 ;
     RECT  68.928 35.701 68.952 38.149 ;
     RECT  72.6 35.987 72.912 38.149 ;
     RECT  41.76 35.893 42.648 38.195 ;
     RECT  20.736 38.101 25.992 38.243 ;
     RECT  64.656 34.787 64.968 38.243 ;
     RECT  64.944 38.243 64.968 38.245 ;
     RECT  45.312 36.997 47.784 38.291 ;
     RECT  26.976 37.045 27 38.435 ;
     RECT  71.088 37.573 71.112 38.435 ;
     RECT  29.4 34.259 29.832 38.485 ;
     RECT  20.736 38.243 21 38.531 ;
     RECT  54.864 37.043 55.032 38.531 ;
     RECT  20.736 38.531 20.76 38.579 ;
     RECT  31.92 38.149 32.616 38.629 ;
     RECT  6.864 37.427 8.112 38.675 ;
     RECT  18.48 36.515 18.912 38.725 ;
     RECT  56.4 36.323 56.712 38.725 ;
     RECT  29.4 38.485 29.928 38.771 ;
     RECT  29.4 38.771 29.832 38.819 ;
     RECT  64.944 38.245 65.496 38.819 ;
     RECT  39.552 38.149 40.68 39.061 ;
     RECT  60.96 37.621 62.112 39.107 ;
     RECT  56.4 38.725 56.808 39.205 ;
     RECT  61.632 39.107 62.112 39.205 ;
     RECT  39.552 39.061 41.064 39.251 ;
     RECT  48.816 38.005 48.84 39.253 ;
     RECT  51 36.661 53.016 39.253 ;
     RECT  12.96 37.667 13.656 39.301 ;
     RECT  56.304 39.205 56.808 39.301 ;
     RECT  67.2 38.149 67.896 39.301 ;
     RECT  68.928 38.149 69.768 39.301 ;
     RECT  31.776 38.629 32.616 39.347 ;
     RECT  51 39.253 53.592 39.347 ;
     RECT  47.088 38.291 47.784 39.349 ;
     RECT  48.816 39.253 48.984 39.349 ;
     RECT  45.312 38.291 45.912 39.493 ;
     RECT  42.624 38.195 42.648 39.731 ;
     RECT  47.088 39.349 48.984 39.731 ;
     RECT  45.264 39.493 45.912 39.779 ;
     RECT  31.776 39.347 32.184 39.875 ;
     RECT  34.704 36.565 35.112 39.877 ;
     RECT  51 39.347 51.312 39.925 ;
     RECT  67.2 39.301 69.768 40.019 ;
     RECT  56.304 39.301 57.624 40.021 ;
     RECT  12.864 39.301 13.656 40.067 ;
     RECT  31.872 39.875 32.184 40.067 ;
     RECT  48.816 39.731 48.984 40.067 ;
     RECT  56.256 40.021 57.624 40.067 ;
     RECT  18.48 38.725 19.128 40.259 ;
     RECT  64.944 38.819 64.968 40.403 ;
     RECT  61.632 39.205 62.904 40.405 ;
     RECT  47.088 39.731 47.784 40.499 ;
     RECT  9.408 39.589 9.432 40.547 ;
     RECT  56.256 40.067 57 40.835 ;
     RECT  34.224 39.877 35.112 40.981 ;
     RECT  16.704 40.165 16.728 41.027 ;
     RECT  50.736 39.925 51.312 41.027 ;
     RECT  68.832 40.019 69.768 41.027 ;
     RECT  11.232 39.781 11.256 41.075 ;
     RECT  22.848 38.243 25.992 41.075 ;
     RECT  72.48 38.149 72.912 41.171 ;
     RECT  31.872 40.067 31.944 41.221 ;
     RECT  51 41.027 51.312 41.221 ;
     RECT  31.872 41.221 32.52 41.267 ;
     RECT  61.632 40.405 63 41.267 ;
     RECT  52.56 39.347 53.592 41.363 ;
     RECT  39.792 39.251 41.064 41.365 ;
     RECT  7.68 38.675 8.112 41.413 ;
     RECT  42.816 39.829 42.84 41.459 ;
     RECT  52.56 41.363 53.016 41.603 ;
     RECT  5.712 38.101 5.736 41.651 ;
     RECT  61.632 41.267 62.904 41.651 ;
     RECT  69.744 41.027 69.768 41.651 ;
     RECT  56.256 40.835 56.712 41.797 ;
     RECT  54.864 38.531 54.888 41.845 ;
     RECT  56.256 41.797 56.808 41.845 ;
     RECT  48.816 40.067 48.84 41.939 ;
     RECT  13.2 40.067 13.656 41.989 ;
     RECT  13.104 41.989 13.656 42.035 ;
     RECT  34.224 40.981 35.352 42.179 ;
     RECT  39.792 41.365 41.16 42.179 ;
     RECT  54.864 41.845 56.808 42.181 ;
     RECT  15.648 37.571 15.672 42.227 ;
     RECT  34.224 42.179 35.112 42.227 ;
     RECT  38.736 40.453 38.76 42.227 ;
     RECT  54.864 42.181 57.048 42.227 ;
     RECT  52.56 41.603 52.824 42.323 ;
     RECT  51 41.221 51.432 42.325 ;
     RECT  61.632 41.651 62.112 42.419 ;
     RECT  22.848 41.075 22.872 42.469 ;
     RECT  24 41.075 25.992 42.469 ;
     RECT  22.848 42.469 25.992 42.659 ;
     RECT  47.328 40.499 47.784 42.659 ;
     RECT  59.472 34.547 59.496 42.709 ;
     RECT  54.864 42.227 55.416 42.755 ;
     RECT  50.208 42.325 51.432 42.803 ;
     RECT  7.584 41.413 8.112 42.949 ;
     RECT  72.6 41.171 72.912 42.997 ;
     RECT  59.328 42.709 59.496 43.093 ;
     RECT  5.856 42.133 5.88 43.139 ;
     RECT  6.864 42.949 8.112 43.285 ;
     RECT  22.848 42.659 22.872 43.285 ;
     RECT  39.792 42.179 40.68 43.285 ;
     RECT  61.8 42.419 62.112 43.285 ;
     RECT  6.864 43.285 8.568 43.331 ;
     RECT  50.208 42.803 51.312 43.331 ;
     RECT  31.92 41.267 32.52 43.379 ;
     RECT  29.4 38.819 29.712 43.381 ;
     RECT  45.312 39.779 45.912 43.381 ;
     RECT  0.288 42.181 0.312 43.525 ;
     RECT  66 42.709 66.024 43.571 ;
     RECT  18.48 40.259 18.912 43.619 ;
     RECT  59.328 43.093 60.216 43.811 ;
     RECT  56.4 42.227 57.048 43.813 ;
     RECT  61.8 43.285 62.712 43.907 ;
     RECT  7.8 43.331 8.568 43.955 ;
     RECT  11.376 42.565 11.4 43.955 ;
     RECT  24 42.659 25.992 43.955 ;
     RECT  31.92 43.379 31.944 43.955 ;
     RECT  56.4 43.813 57.432 43.955 ;
     RECT  52.8 42.323 52.824 44.051 ;
     RECT  22.224 43.285 22.872 44.099 ;
     RECT  24 43.955 24.408 44.099 ;
     RECT  45.312 43.381 46.584 44.099 ;
     RECT  59.472 43.811 60.216 44.099 ;
     RECT  71.952 42.997 72.912 44.099 ;
     RECT  0.288 43.525 0.408 44.195 ;
     RECT  0.288 44.195 0.312 44.293 ;
     RECT  0.192 44.293 0.312 44.339 ;
     RECT  6.576 43.861 6.6 44.389 ;
     RECT  34.8 42.227 35.112 44.389 ;
     RECT  36.576 35.027 36.6 44.389 ;
     RECT  2.4 27.971 2.712 44.437 ;
     RECT  13.104 42.035 13.512 44.483 ;
     RECT  25.968 43.955 25.992 44.917 ;
     RECT  2.4 44.437 2.856 45.059 ;
     RECT  57.936 44.437 57.96 45.155 ;
     RECT  39.792 43.285 41.064 45.203 ;
     RECT  45.312 44.099 46.296 45.203 ;
     RECT  43.008 44.965 43.032 45.301 ;
     RECT  59.472 44.099 59.496 45.301 ;
     RECT  0.192 44.339 0.216 45.347 ;
     RECT  22.848 44.099 22.872 45.491 ;
     RECT  28.992 43.381 29.712 45.541 ;
     RECT  28.272 45.541 29.712 45.587 ;
     RECT  32.016 44.629 32.04 45.683 ;
     RECT  63.792 44.389 63.816 45.731 ;
     RECT  47.568 42.659 47.784 45.733 ;
     RECT  10.464 44.965 10.488 46.069 ;
     RECT  72.6 44.099 72.912 46.069 ;
     RECT  18.6 43.619 18.912 46.117 ;
     RECT  20.208 44.965 20.232 46.117 ;
     RECT  25.968 44.917 26.904 46.117 ;
     RECT  51 43.331 51.312 46.165 ;
     RECT  15.984 46.117 16.008 46.213 ;
     RECT  6.24 44.389 6.6 46.259 ;
     RECT  21.216 45.493 21.24 46.259 ;
     RECT  42.96 45.301 43.032 46.403 ;
     RECT  9.6 46.069 10.488 46.645 ;
     RECT  50.64 46.165 51.312 46.645 ;
     RECT  13.2 44.483 13.512 46.741 ;
     RECT  47.424 45.733 47.784 46.741 ;
     RECT  50.64 46.645 51.432 46.741 ;
     RECT  66 44.965 66.024 46.787 ;
     RECT  13.104 46.741 13.512 46.837 ;
     RECT  15.984 46.213 16.536 46.885 ;
     RECT  28.272 45.587 28.296 46.885 ;
     RECT  29.4 45.587 29.712 46.885 ;
     RECT  54.864 42.755 54.888 46.931 ;
     RECT  18.6 46.117 20.232 47.027 ;
     RECT  49.68 46.741 51.432 47.027 ;
     RECT  39.792 45.203 40.68 47.029 ;
     RECT  13.104 46.837 13.656 47.125 ;
     RECT  9.12 46.645 10.488 47.171 ;
     RECT  71.952 46.069 72.912 47.219 ;
     RECT  61.8 43.907 62.112 47.221 ;
     RECT  59.472 45.301 60.408 47.269 ;
     RECT  59.232 47.269 60.408 47.315 ;
     RECT  15.216 46.885 16.536 47.317 ;
     RECT  24 44.099 24.312 47.317 ;
     RECT  25.968 46.117 27.288 47.317 ;
     RECT  15.216 47.317 16.68 47.459 ;
     RECT  67.2 40.019 67.512 47.461 ;
     RECT  39.792 47.029 40.968 47.603 ;
     RECT  24 47.317 27.288 47.701 ;
     RECT  28.272 46.885 29.712 47.701 ;
     RECT  15.216 47.459 16.104 47.795 ;
     RECT  24 47.701 29.712 47.843 ;
     RECT  47.328 46.741 47.784 47.843 ;
     RECT  6.336 46.259 6.6 47.845 ;
     RECT  31.872 47.701 31.896 47.845 ;
     RECT  50.4 47.027 51.432 47.891 ;
     RECT  13.056 47.125 13.656 47.987 ;
     RECT  16.08 47.795 16.104 48.131 ;
     RECT  9.6 47.171 10.488 48.277 ;
     RECT  59.232 47.315 59.496 48.419 ;
     RECT  13.056 47.987 13.608 48.421 ;
     RECT  21.936 47.461 21.96 48.421 ;
     RECT  31.344 47.845 31.896 48.515 ;
     RECT  12.912 48.421 13.608 48.563 ;
     RECT  38.784 47.461 38.808 48.659 ;
     RECT  66.144 47.893 66.168 48.659 ;
     RECT  18.6 47.027 20.184 48.947 ;
     RECT  39.792 47.603 40.68 48.949 ;
     RECT  7.8 43.955 8.112 48.997 ;
     RECT  9.6 48.277 10.584 48.997 ;
     RECT  18.6 48.947 18.912 48.997 ;
     RECT  43.008 46.403 43.032 48.997 ;
     RECT  24 47.843 25.992 49.043 ;
     RECT  52.8 47.749 53.592 49.045 ;
     RECT  61.8 47.221 62.232 49.045 ;
     RECT  12.912 48.563 13.512 49.091 ;
     RECT  31.872 48.515 31.896 49.091 ;
     RECT  34.8 44.389 36.6 49.093 ;
     RECT  7.8 48.997 10.584 49.139 ;
     RECT  21.936 48.421 22.776 49.379 ;
     RECT  72.6 47.219 72.912 49.381 ;
     RECT  5.664 47.845 6.6 49.475 ;
     RECT  9.6 49.139 10.584 49.477 ;
     RECT  58.08 45.829 58.104 49.525 ;
     RECT  64.464 48.805 64.488 49.571 ;
     RECT  47.76 47.843 47.784 49.573 ;
     RECT  39.024 48.949 40.68 49.619 ;
     RECT  52.608 49.045 53.592 49.763 ;
     RECT  18.48 48.997 18.912 49.811 ;
     RECT  9.6 49.477 11.544 50.003 ;
     RECT  61.056 49.045 62.232 50.003 ;
     RECT  13.056 49.091 13.512 50.005 ;
     RECT  34.8 49.093 37.56 50.005 ;
     RECT  31.92 50.005 31.944 50.101 ;
     RECT  11.52 50.003 11.544 50.195 ;
     RECT  9.6 50.003 9.624 50.243 ;
     RECT  42.144 48.997 43.032 50.243 ;
     RECT  71.856 49.381 72.912 50.437 ;
     RECT  61.8 50.003 62.232 50.483 ;
     RECT  58.08 49.525 58.344 50.531 ;
     RECT  19.968 48.947 20.184 50.533 ;
     RECT  21.936 49.379 21.96 50.533 ;
     RECT  19.968 50.533 21.96 50.579 ;
     RECT  59.472 48.419 59.496 50.581 ;
     RECT  33.216 50.197 33.24 50.629 ;
     RECT  13.056 50.005 14.232 50.677 ;
     RECT  45.312 45.203 45.912 50.677 ;
     RECT  52.896 49.763 53.592 50.677 ;
     RECT  55.008 50.053 55.032 50.677 ;
     RECT  27.264 47.843 29.712 50.723 ;
     RECT  15.936 49.813 15.96 50.725 ;
     RECT  31.536 50.101 31.944 50.819 ;
     RECT  24 49.043 24.744 50.869 ;
     RECT  25.968 49.043 25.992 50.869 ;
     RECT  47.76 49.573 48.216 50.917 ;
     RECT  27.408 50.723 29.712 50.965 ;
     RECT  52.896 50.677 55.032 51.061 ;
     RECT  52.8 51.061 55.032 51.107 ;
     RECT  47.616 50.917 48.216 51.109 ;
     RECT  49.296 50.101 49.32 51.109 ;
     RECT  56.4 43.955 56.712 51.109 ;
     RECT  58.08 50.531 58.152 51.109 ;
     RECT  12.48 50.677 14.232 51.203 ;
     RECT  34.368 50.005 37.56 51.251 ;
     RECT  71.856 50.437 73.512 51.251 ;
     RECT  67.2 47.461 67.608 51.253 ;
     RECT  6.336 49.475 6.6 51.347 ;
     RECT  24 50.869 25.992 51.349 ;
     RECT  45.024 50.677 45.912 51.395 ;
     RECT  39.792 49.619 40.68 51.493 ;
     RECT  36.576 51.251 37.56 51.587 ;
     RECT  23.424 51.349 25.992 51.635 ;
     RECT  33.024 50.629 33.24 51.637 ;
     RECT  34.368 51.251 35.112 51.637 ;
     RECT  20.064 50.579 21.96 51.733 ;
     RECT  59.328 50.581 59.496 51.877 ;
     RECT  6.336 51.347 6.552 51.923 ;
     RECT  47.616 51.109 49.32 51.923 ;
     RECT  56.4 51.109 58.152 51.923 ;
     RECT  59.328 51.877 59.832 51.923 ;
     RECT  27.408 50.965 30.312 52.069 ;
     RECT  31.536 50.819 31.56 52.069 ;
     RECT  36.576 51.587 36.84 52.259 ;
     RECT  27.408 52.069 31.56 52.261 ;
     RECT  33.024 51.637 35.112 52.403 ;
     RECT  20.064 51.733 22.872 52.405 ;
     RECT  71.856 51.251 72.912 52.405 ;
     RECT  49.296 51.923 49.32 52.453 ;
     RECT  4.464 49.525 4.488 52.499 ;
     RECT  43.008 50.243 43.032 52.499 ;
     RECT  19.968 52.405 22.872 52.547 ;
     RECT  47.616 51.923 47.832 52.547 ;
     RECT  27.408 52.261 31.608 52.739 ;
     RECT  38.688 52.405 38.712 52.741 ;
     RECT  39.792 51.493 41.064 52.741 ;
     RECT  33.408 52.403 35.112 52.787 ;
     RECT  38.688 52.741 41.064 52.883 ;
     RECT  59.472 51.923 59.832 52.979 ;
     RECT  7.8 49.139 8.112 52.981 ;
     RECT  50.4 47.891 51.312 52.981 ;
     RECT  52.8 51.107 54.408 52.981 ;
     RECT  66.384 51.253 67.8 52.981 ;
     RECT  50.4 52.981 54.408 53.027 ;
     RECT  61.8 50.483 62.112 53.029 ;
     RECT  15.936 50.725 16.536 53.075 ;
     RECT  19.968 52.547 22.2 53.075 ;
     RECT  31.536 52.739 31.608 53.075 ;
     RECT  7.8 52.981 8.376 53.123 ;
     RECT  38.688 52.883 38.712 53.173 ;
     RECT  47.76 52.547 47.832 53.315 ;
     RECT  38.544 53.173 38.712 53.363 ;
     RECT  42.288 53.221 42.312 53.555 ;
     RECT  2.4 45.059 2.712 53.557 ;
     RECT  19.968 53.075 20.232 53.603 ;
     RECT  21.648 53.075 22.2 53.603 ;
     RECT  39.792 52.883 41.064 53.603 ;
     RECT  49.296 52.453 49.416 53.603 ;
     RECT  47.76 53.315 47.784 53.749 ;
     RECT  27.408 52.739 30.312 53.797 ;
     RECT  47.424 53.749 47.784 53.939 ;
     RECT  61.8 53.029 62.712 53.987 ;
     RECT  65.856 52.981 67.8 54.035 ;
     RECT  2.4 53.557 2.808 54.085 ;
     RECT  70.512 52.981 70.536 54.131 ;
     RECT  71.856 52.405 73.56 54.131 ;
     RECT  3.984 53.557 4.008 54.179 ;
     RECT  51 53.027 54.408 54.179 ;
     RECT  71.856 54.131 72.912 54.179 ;
     RECT  42.576 54.229 42.6 54.277 ;
     RECT  66.384 54.035 67.8 54.371 ;
     RECT  34.8 52.787 35.112 54.373 ;
     RECT  34.8 54.373 35.544 54.515 ;
     RECT  56.4 51.923 58.104 54.659 ;
     RECT  59.472 52.979 59.496 54.661 ;
     RECT  42.576 54.277 42.696 54.757 ;
     RECT  41.808 54.757 42.696 54.853 ;
     RECT  9.648 54.085 9.672 54.899 ;
     RECT  27.312 53.797 30.312 54.899 ;
     RECT  41.808 54.853 42.792 55.043 ;
     RECT  24 51.635 25.992 55.045 ;
     RECT  27.312 54.899 28.056 55.045 ;
     RECT  41.808 55.043 41.832 55.139 ;
     RECT  18.6 49.811 18.912 55.141 ;
     RECT  20.064 53.603 20.232 55.141 ;
     RECT  24 55.045 28.056 55.237 ;
     RECT  39.792 53.603 40.68 55.237 ;
     RECT  64.944 54.565 64.968 55.237 ;
     RECT  66.384 54.371 67.608 55.237 ;
     RECT  21.936 53.603 22.2 55.331 ;
     RECT  33.408 52.787 33.432 55.379 ;
     RECT  64.944 55.237 67.608 55.523 ;
     RECT  34.8 54.515 35.112 55.525 ;
     RECT  65.472 55.523 67.608 55.525 ;
     RECT  6.528 51.923 6.552 55.717 ;
     RECT  7.8 53.123 8.112 55.717 ;
     RECT  45.312 51.395 45.912 55.765 ;
     RECT  6.528 55.717 8.112 55.813 ;
     RECT  45.312 55.765 46.104 55.813 ;
     RECT  23.76 55.237 28.056 55.859 ;
     RECT  39.792 55.237 41.064 55.907 ;
     RECT  45.024 55.813 46.104 55.907 ;
     RECT  18.6 55.141 20.232 55.955 ;
     RECT  63.744 53.413 63.768 55.955 ;
     RECT  47.76 53.939 47.784 56.053 ;
     RECT  49.296 53.603 49.32 56.053 ;
     RECT  29.088 54.899 30.312 56.101 ;
     RECT  31.536 53.075 31.56 56.101 ;
     RECT  65.472 55.525 68.088 56.147 ;
     RECT  47.76 56.053 49.32 56.195 ;
     RECT  49.296 56.195 49.32 56.389 ;
     RECT  51 54.179 51.312 56.389 ;
     RECT  56.4 54.659 56.856 56.389 ;
     RECT  29.088 56.101 31.56 56.483 ;
     RECT  34.32 55.525 35.112 56.483 ;
     RECT  37.584 55.813 37.608 56.483 ;
     RECT  59.232 54.661 59.496 56.483 ;
     RECT  24 55.859 28.056 56.531 ;
     RECT  24 56.531 27.96 56.579 ;
     RECT  18.6 55.955 18.912 56.677 ;
     RECT  16.416 53.075 16.536 56.725 ;
     RECT  66.384 56.147 68.088 56.771 ;
     RECT  52.8 54.179 53.784 56.819 ;
     RECT  39.792 55.907 40.68 56.869 ;
     RECT  6.528 55.813 8.328 56.915 ;
     RECT  29.088 56.483 30.984 56.915 ;
     RECT  43.008 55.045 43.032 56.915 ;
     RECT  45.024 55.907 45.912 56.915 ;
     RECT  7.8 56.915 8.328 56.965 ;
     RECT  20.064 55.955 20.232 56.965 ;
     RECT  36.576 52.259 36.6 56.965 ;
     RECT  29.088 56.915 30.312 57.011 ;
     RECT  21.936 55.331 22.104 57.059 ;
     RECT  19.968 56.965 20.232 57.107 ;
     RECT  21.936 57.059 21.96 57.107 ;
     RECT  16.416 56.725 16.584 57.109 ;
     RECT  63.84 56.965 63.864 57.157 ;
     RECT  49.296 56.389 51.312 57.203 ;
     RECT  24 56.579 24.84 57.347 ;
     RECT  63.84 57.157 64.728 57.347 ;
     RECT  45.312 56.915 45.912 57.445 ;
     RECT  61.8 53.987 62.112 57.445 ;
     RECT  25.968 56.579 27.96 57.539 ;
     RECT  34.8 56.483 35.112 57.541 ;
     RECT  36.336 56.965 36.6 57.541 ;
     RECT  55.872 56.389 56.856 57.541 ;
     RECT  55.872 57.541 57 57.587 ;
     RECT  69.792 56.917 69.816 57.635 ;
     RECT  12.48 51.203 13.512 57.829 ;
     RECT  45.312 57.445 46.344 57.829 ;
     RECT  47.76 56.195 47.784 57.829 ;
     RECT  49.296 57.203 49.32 58.021 ;
     RECT  49.104 58.021 49.32 58.067 ;
     RECT  2.304 54.085 2.808 58.117 ;
     RECT  12.24 57.829 13.512 58.117 ;
     RECT  71.52 56.341 71.544 58.117 ;
     RECT  72.6 54.179 72.912 58.117 ;
     RECT  21.888 57.541 21.912 58.405 ;
     RECT  25.968 57.539 26.664 58.501 ;
     RECT  59.472 56.483 59.496 58.501 ;
     RECT  25.344 58.501 26.664 58.547 ;
     RECT  45.312 57.829 47.784 58.547 ;
     RECT  56.4 57.587 57 58.645 ;
     RECT  58.08 54.659 58.104 58.645 ;
     RECT  78 2.151 78.312 58.645 ;
     RECT  34.8 57.541 36.6 58.691 ;
     RECT  31.392 58.117 31.416 58.739 ;
     RECT  50.496 57.203 51.312 58.787 ;
     RECT  45.312 58.547 46.344 58.979 ;
     RECT  6.528 56.915 6.552 59.029 ;
     RECT  21.888 58.405 21.96 59.029 ;
     RECT  4.56 58.021 4.584 59.075 ;
     RECT  21.648 59.029 21.96 59.075 ;
     RECT  71.52 58.117 72.912 59.171 ;
     RECT  12.192 58.117 13.512 59.219 ;
     RECT  16.416 57.109 16.632 59.221 ;
     RECT  10.176 56.965 10.2 59.267 ;
     RECT  59.472 58.501 60.216 59.267 ;
     RECT  52.8 56.819 53.304 59.269 ;
     RECT  2.304 58.117 2.856 59.315 ;
     RECT  50.736 58.787 51.312 59.315 ;
     RECT  75.168 58.501 75.192 59.315 ;
     RECT  27.84 57.539 27.96 59.413 ;
     RECT  27.84 59.413 28.056 59.507 ;
     RECT  50.88 59.315 51.312 59.507 ;
     RECT  27.936 59.507 28.056 59.555 ;
     RECT  66.384 56.771 67.608 59.557 ;
     RECT  21.648 59.075 21.912 59.603 ;
     RECT  12.24 59.219 13.512 59.651 ;
     RECT  52.416 59.269 53.304 59.651 ;
     RECT  5.712 59.029 6.552 59.653 ;
     RECT  7.8 56.965 8.52 59.653 ;
     RECT  5.712 59.653 8.52 59.699 ;
     RECT  31.296 59.173 31.32 59.699 ;
     RECT  39.792 56.869 41.208 59.795 ;
     RECT  5.712 59.699 5.736 59.843 ;
     RECT  21.648 59.603 21.672 59.891 ;
     RECT  47.712 58.547 47.784 59.987 ;
     RECT  66.096 59.557 67.608 60.131 ;
     RECT  29.4 57.011 30.312 60.277 ;
     RECT  31.968 59.701 31.992 60.373 ;
     RECT  33.552 59.893 33.576 60.373 ;
     RECT  47.76 59.987 47.784 60.373 ;
     RECT  36.336 58.691 36.6 60.419 ;
     RECT  66.096 60.131 67.512 60.467 ;
     RECT  27.936 59.555 28.008 60.563 ;
     RECT  77.328 58.645 78.312 60.563 ;
     RECT  24 57.347 24.312 60.565 ;
     RECT  25.344 58.547 25.992 60.565 ;
     RECT  43.632 58.933 43.656 60.661 ;
     RECT  6.816 59.699 8.52 60.709 ;
     RECT  61.536 57.445 62.112 60.709 ;
     RECT  6.048 60.709 8.52 60.755 ;
     RECT  24 60.565 25.992 60.805 ;
     RECT  51 59.507 51.312 60.805 ;
     RECT  66.096 60.467 66.168 60.805 ;
     RECT  27.984 60.563 28.008 60.899 ;
     RECT  45.312 58.979 45.912 60.949 ;
     RECT  72.6 59.171 72.912 60.949 ;
     RECT  29.04 60.277 30.312 60.997 ;
     RECT  14.88 59.605 14.904 61.043 ;
     RECT  36.432 60.419 36.6 61.043 ;
     RECT  44.736 60.949 45.912 61.045 ;
     RECT  16.176 59.221 16.632 61.093 ;
     RECT  17.616 56.677 18.912 61.093 ;
     RECT  24 60.805 26.376 61.139 ;
     RECT  61.536 60.709 62.808 61.139 ;
     RECT  31.968 60.373 33.576 61.235 ;
     RECT  16.176 61.093 18.912 61.237 ;
     RECT  15.408 61.237 18.912 61.283 ;
     RECT  69.168 61.189 69.192 61.331 ;
     RECT  6.048 60.755 6.072 61.333 ;
     RECT  50.688 60.805 51.312 61.381 ;
     RECT  0.192 59.605 0.216 61.429 ;
     RECT  52.8 59.651 53.304 61.477 ;
     RECT  54.48 58.021 54.504 61.477 ;
     RECT  28.416 60.997 30.312 61.571 ;
     RECT  37.68 58.117 37.704 61.571 ;
     RECT  47.76 60.373 47.832 61.571 ;
     RECT  18.096 61.283 18.912 61.619 ;
     RECT  32.784 61.235 33.576 61.667 ;
     RECT  72.6 60.949 73.08 61.667 ;
     RECT  15.408 61.283 16.632 61.859 ;
     RECT  25.344 61.139 26.376 61.859 ;
     RECT  34.8 58.691 35.112 61.861 ;
     RECT  7.152 60.755 8.52 61.907 ;
     RECT  20.16 57.107 20.232 61.909 ;
     RECT  44.736 61.045 46.152 61.955 ;
     RECT  34.8 61.861 35.208 62.003 ;
     RECT  0.144 61.429 0.216 62.005 ;
     RECT  49.104 58.067 49.128 62.149 ;
     RECT  50.16 61.381 51.312 62.149 ;
     RECT  33.552 61.667 33.576 62.195 ;
     RECT  49.104 62.149 51.312 62.195 ;
     RECT  71.52 59.171 71.544 62.195 ;
     RECT  45.024 61.955 46.152 62.243 ;
     RECT  51 62.195 51.312 62.245 ;
     RECT  52.8 61.477 54.504 62.245 ;
     RECT  45.312 62.243 46.152 62.339 ;
     RECT  12.288 59.651 13.512 62.485 ;
     RECT  51 62.245 54.504 62.579 ;
     RECT  24 61.139 24.312 62.629 ;
     RECT  25.344 61.859 25.992 62.629 ;
     RECT  65.76 60.805 66.168 62.629 ;
     RECT  65.664 62.629 66.168 62.675 ;
     RECT  29.04 61.571 30.312 62.677 ;
     RECT  43.344 60.661 43.656 62.723 ;
     RECT  52.8 62.579 54.504 62.723 ;
     RECT  39.792 59.795 41.16 62.819 ;
     RECT  28.848 62.677 30.312 62.965 ;
     RECT  5.712 61.333 6.072 63.011 ;
     RECT  61.8 61.139 62.808 63.109 ;
     RECT  0.144 62.005 0.312 63.157 ;
     RECT  28.848 62.965 30.552 63.157 ;
     RECT  39.792 62.819 40.512 63.205 ;
     RECT  47.76 61.571 47.784 63.205 ;
     RECT  68.976 61.333 69 63.205 ;
     RECT  59.472 59.267 59.496 63.253 ;
     RECT  61.8 63.109 63.768 63.299 ;
     RECT  4.08 60.277 4.104 63.539 ;
     RECT  7.8 61.907 8.52 63.637 ;
     RECT  78 60.563 78.312 63.685 ;
     RECT  43.344 62.723 43.512 63.733 ;
     RECT  7.8 63.637 9.144 63.779 ;
     RECT  15.408 61.859 16.344 63.779 ;
     RECT  28.464 63.157 30.552 63.781 ;
     RECT  51 62.579 51.312 63.781 ;
     RECT  56.4 58.645 58.104 63.781 ;
     RECT  61.8 63.299 62.112 63.781 ;
     RECT  72.6 61.667 72.912 63.781 ;
     RECT  28.464 63.781 31.368 63.827 ;
     RECT  7.8 63.779 8.52 63.875 ;
     RECT  33.072 63.205 33.096 64.211 ;
     RECT  42.672 63.733 43.512 64.357 ;
     RECT  65.664 62.675 65.784 64.357 ;
     RECT  10.224 63.157 10.248 64.403 ;
     RECT  39.216 63.205 40.512 64.403 ;
     RECT  56.304 63.781 58.104 64.451 ;
     RECT  68.928 63.205 69 64.451 ;
     RECT  18.6 61.619 18.912 64.501 ;
     RECT  12.288 62.485 13.656 64.547 ;
     RECT  29.232 63.827 31.368 64.595 ;
     RECT  50.88 63.781 51.312 64.595 ;
     RECT  65.52 64.357 65.784 64.595 ;
     RECT  68.928 64.451 68.952 64.595 ;
     RECT  61.68 63.781 62.112 64.643 ;
     RECT  71.76 63.781 72.912 64.739 ;
     RECT  47.328 63.205 47.784 64.885 ;
     RECT  19.968 61.909 20.232 64.931 ;
     RECT  22.08 63.781 22.104 64.933 ;
     RECT  24 62.629 25.992 64.933 ;
     RECT  21.744 64.933 22.104 64.979 ;
     RECT  2.4 59.315 2.856 65.027 ;
     RECT  52.8 62.723 53.304 65.027 ;
     RECT  65.52 64.595 65.688 65.027 ;
     RECT  77.232 63.685 78.312 65.075 ;
     RECT  46.992 64.885 47.784 65.123 ;
     RECT  21.744 64.979 21.768 65.171 ;
     RECT  63.744 63.299 63.768 65.171 ;
     RECT  59.472 63.253 59.928 65.315 ;
     RECT  42.672 64.357 43.752 65.509 ;
     RECT  45.312 62.339 45.912 65.509 ;
     RECT  49.344 62.195 49.368 65.509 ;
     RECT  47.76 65.123 47.784 65.557 ;
     RECT  6.048 63.011 6.072 65.603 ;
     RECT  29.232 64.595 30.552 65.603 ;
     RECT  42.48 65.509 43.752 65.939 ;
     RECT  61.8 64.643 62.112 66.085 ;
     RECT  67.2 60.467 67.512 66.085 ;
     RECT  45.312 65.509 46.008 66.131 ;
     RECT  32.88 65.509 32.904 66.179 ;
     RECT  59.472 65.315 59.832 66.179 ;
     RECT  45.312 66.131 45.912 66.229 ;
     RECT  45.072 66.229 45.912 66.371 ;
     RECT  2.4 65.027 2.712 66.373 ;
     RECT  42.48 65.939 43.512 66.419 ;
     RECT  4.56 65.509 4.584 66.469 ;
     RECT  4.56 66.469 4.68 66.515 ;
     RECT  47.76 65.557 48.216 66.515 ;
     RECT  61.248 66.085 63 66.515 ;
     RECT  23.76 64.933 25.992 66.517 ;
     RECT  27.792 65.509 27.816 66.659 ;
     RECT  61.8 66.515 63 66.661 ;
     RECT  67.2 66.085 67.8 66.661 ;
     RECT  0.144 63.157 0.408 66.707 ;
     RECT  36.576 61.043 36.6 66.709 ;
     RECT  54.48 62.723 54.504 66.755 ;
     RECT  61.8 66.661 63.72 66.755 ;
     RECT  23.76 66.517 26.808 66.803 ;
     RECT  36.576 66.709 37.32 66.851 ;
     RECT  16.176 63.779 16.344 66.901 ;
     RECT  17.712 64.501 18.912 66.901 ;
     RECT  23.76 66.803 24.312 66.901 ;
     RECT  42.48 66.419 43.368 66.901 ;
     RECT  78 65.075 78.312 66.901 ;
     RECT  49.344 65.509 49.944 66.995 ;
     RECT  31.536 65.509 31.56 67.043 ;
     RECT  39.792 64.403 40.512 67.141 ;
     RECT  56.4 64.451 58.104 67.189 ;
     RECT  59.472 66.179 59.496 67.189 ;
     RECT  7.8 63.875 8.112 67.237 ;
     RECT  9.168 66.709 9.192 67.237 ;
     RECT  15.168 65.797 15.192 67.283 ;
     RECT  67.2 66.661 68.616 67.283 ;
     RECT  75.84 66.085 75.864 67.283 ;
     RECT  25.536 66.803 26.808 67.331 ;
     RECT  67.2 67.283 67.8 67.331 ;
     RECT  34.8 62.003 35.112 67.333 ;
     RECT  7.8 67.237 9.192 67.475 ;
     RECT  72.6 64.739 72.912 67.477 ;
     RECT  4.656 66.515 4.68 67.525 ;
     RECT  3.984 67.525 4.68 67.571 ;
     RECT  51 64.595 51.312 67.669 ;
     RECT  39.792 67.141 40.92 67.715 ;
     RECT  34.8 67.333 35.304 67.765 ;
     RECT  36.576 66.851 36.6 67.765 ;
     RECT  52.8 65.027 52.824 67.765 ;
     RECT  71.856 67.477 72.912 67.765 ;
     RECT  2.4 66.373 2.808 67.859 ;
     RECT  49.344 66.995 49.656 67.859 ;
     RECT  71.856 67.765 73.224 67.909 ;
     RECT  56.4 67.189 59.496 68.005 ;
     RECT  47.76 66.515 47.784 68.053 ;
     RECT  20.16 64.931 20.232 68.099 ;
     RECT  42.384 66.901 43.368 68.101 ;
     RECT  5.952 67.141 5.976 68.147 ;
     RECT  56.112 68.005 59.496 68.147 ;
     RECT  67.2 67.331 67.512 68.149 ;
     RECT  71.088 67.909 73.224 68.195 ;
     RECT  42.384 68.101 43.656 68.245 ;
     RECT  42.144 68.245 43.656 68.291 ;
     RECT  61.8 66.755 62.112 68.341 ;
     RECT  43.344 68.291 43.656 68.387 ;
     RECT  77.52 66.901 78.312 68.435 ;
     RECT  71.088 68.195 71.112 68.675 ;
     RECT  65.664 65.027 65.688 68.773 ;
     RECT  50.88 67.669 51.312 68.821 ;
     RECT  52.8 67.765 53.592 68.821 ;
     RECT  65.088 68.773 65.688 68.915 ;
     RECT  2.4 67.859 2.712 68.917 ;
     RECT  45.312 66.371 45.912 68.917 ;
     RECT  63.696 66.755 63.72 68.963 ;
     RECT  15.12 67.765 15.144 69.011 ;
     RECT  50.88 68.821 53.592 69.011 ;
     RECT  72.6 68.195 73.224 69.011 ;
     RECT  47.376 68.053 47.784 69.059 ;
     RECT  3.984 67.571 4.008 69.203 ;
     RECT  25.536 67.331 25.992 69.203 ;
     RECT  47.76 69.059 47.784 69.205 ;
     RECT  49.344 67.859 49.368 69.205 ;
     RECT  50.88 69.011 52.824 69.251 ;
     RECT  20.448 68.245 20.472 69.301 ;
     RECT  20.256 69.301 20.472 69.347 ;
     RECT  51 69.251 52.824 69.395 ;
     RECT  23.328 66.901 24.312 69.493 ;
     RECT  21.552 66.085 21.576 69.635 ;
     RECT  16.176 66.901 18.912 69.683 ;
     RECT  7.8 67.475 8.472 69.827 ;
     RECT  16.752 69.683 18.912 69.827 ;
     RECT  0.144 66.707 0.216 69.829 ;
     RECT  68.496 68.917 68.52 69.877 ;
     RECT  42.144 68.291 42.168 69.923 ;
     RECT  68.496 69.877 69 69.923 ;
     RECT  45.312 68.917 46.392 70.019 ;
     RECT  14.784 69.445 14.808 70.069 ;
     RECT  25.632 69.203 25.992 70.069 ;
     RECT  14.784 70.069 15.096 70.115 ;
     RECT  67.008 68.149 67.512 70.163 ;
     RECT  10.464 69.781 10.488 70.259 ;
     RECT  55.008 69.493 55.032 70.259 ;
     RECT  25.632 70.069 26.76 70.403 ;
     RECT  23.232 69.493 24.312 70.451 ;
     RECT  32.208 67.957 32.232 70.453 ;
     RECT  32.208 70.453 32.52 70.499 ;
     RECT  16.752 69.827 17.064 70.595 ;
     RECT  2.4 68.917 2.808 70.597 ;
     RECT  16.752 70.595 17.016 70.645 ;
     RECT  29.4 65.603 30.552 70.693 ;
     RECT  74.688 70.069 74.712 70.739 ;
     RECT  60.864 68.341 62.112 70.787 ;
     RECT  12.288 64.547 13.512 70.789 ;
     RECT  29.088 70.693 30.552 70.789 ;
     RECT  27.888 69.301 27.912 70.835 ;
     RECT  29.088 70.789 31.32 70.835 ;
     RECT  51 69.395 51.312 70.837 ;
     RECT  18.192 69.827 18.912 71.075 ;
     RECT  2.4 70.597 3.384 71.123 ;
     RECT  76.368 70.597 76.392 71.221 ;
     RECT  76.368 71.221 76.776 71.267 ;
     RECT  2.4 71.123 2.808 71.315 ;
     RECT  15.072 70.115 15.096 71.413 ;
     RECT  16.272 70.645 17.016 71.413 ;
     RECT  61.68 70.787 62.112 71.509 ;
     RECT  0.144 69.829 0.264 71.557 ;
     RECT  20.256 69.347 20.28 71.605 ;
     RECT  19.968 71.605 20.28 71.651 ;
     RECT  7.8 69.827 8.112 71.749 ;
     RECT  15.072 71.413 17.016 71.795 ;
     RECT  67.056 70.163 67.512 71.797 ;
     RECT  68.976 69.923 69 71.797 ;
     RECT  29.4 70.835 31.32 71.843 ;
     RECT  32.496 70.499 32.52 71.843 ;
     RECT  67.056 71.797 69 71.843 ;
     RECT  15.072 71.795 16.872 71.891 ;
     RECT  25.632 70.403 25.704 71.893 ;
     RECT  67.056 71.843 68.232 71.939 ;
     RECT  29.4 71.843 30.552 71.941 ;
     RECT  23.328 70.451 24.312 71.987 ;
     RECT  29.184 71.941 30.552 72.037 ;
     RECT  43.632 68.387 43.656 72.131 ;
     RECT  47.76 69.205 49.368 72.131 ;
     RECT  29.088 72.037 30.552 72.179 ;
     RECT  25.584 71.893 25.704 72.227 ;
     RECT  0.144 71.557 0.312 72.275 ;
     RECT  15.456 71.891 16.872 72.275 ;
     RECT  56.4 68.147 59.496 72.277 ;
     RECT  39.792 67.715 40.512 72.373 ;
     RECT  19.968 71.651 19.992 72.419 ;
     RECT  49.248 72.131 49.368 72.419 ;
     RECT  76.752 71.267 76.776 72.419 ;
     RECT  0.144 72.275 0.264 72.467 ;
     RECT  34.8 67.765 36.6 72.517 ;
     RECT  21.12 71.797 21.144 72.805 ;
     RECT  72.6 69.011 72.912 72.805 ;
     RECT  50.784 70.837 51.312 72.851 ;
     RECT  29.4 72.179 30.552 72.949 ;
     RECT  0.144 72.467 0.216 72.995 ;
     RECT  61.68 71.509 63.096 72.995 ;
     RECT  0.192 72.995 0.216 73.091 ;
     RECT  38.784 71.509 38.808 73.235 ;
     RECT  24 71.987 24.312 73.237 ;
     RECT  25.584 72.227 25.656 73.237 ;
     RECT  56.4 72.277 60.408 73.427 ;
     RECT  20.112 73.381 20.136 73.477 ;
     RECT  21.12 72.805 21.672 73.477 ;
     RECT  26.736 70.403 26.76 73.477 ;
     RECT  27.936 71.989 27.96 73.477 ;
     RECT  15.456 72.275 16.296 73.523 ;
     RECT  67.2 71.939 68.232 73.523 ;
     RECT  74.688 72.997 74.712 73.523 ;
     RECT  7.8 71.749 8.856 73.525 ;
     RECT  12.288 70.789 13.608 73.571 ;
     RECT  15.792 73.523 16.296 73.571 ;
     RECT  24 73.237 25.656 73.571 ;
     RECT  34.8 72.517 37.128 73.571 ;
     RECT  39.792 72.373 41.16 73.717 ;
     RECT  20.112 73.477 21.672 73.763 ;
     RECT  39.792 73.717 41.832 73.763 ;
     RECT  34.8 73.571 35.208 73.811 ;
     RECT  54.672 71.077 54.696 73.859 ;
     RECT  72.288 72.805 72.912 74.003 ;
     RECT  61.68 72.995 62.112 74.051 ;
     RECT  51 72.851 51.312 74.053 ;
     RECT  5.568 69.781 5.592 74.147 ;
     RECT  15.792 73.571 16.008 74.147 ;
     RECT  26.736 73.477 27.96 74.147 ;
     RECT  29.4 72.949 30.792 74.147 ;
     RECT  26.736 74.147 27.912 74.339 ;
     RECT  7.2 73.525 8.856 74.581 ;
     RECT  2.4 71.315 2.712 74.629 ;
     RECT  24 73.571 25.608 74.677 ;
     RECT  26.736 74.339 26.76 74.677 ;
     RECT  24 74.677 26.76 74.723 ;
     RECT  56.4 73.427 59.784 74.723 ;
     RECT  20.112 73.763 21.144 74.819 ;
     RECT  41.808 73.763 41.832 74.819 ;
     RECT  27.888 74.339 27.912 74.963 ;
     RECT  25.488 74.723 26.76 75.251 ;
     RECT  7.2 74.581 9.096 75.299 ;
     RECT  2.4 74.629 3.528 75.395 ;
     RECT  25.488 75.251 25.896 75.395 ;
     RECT  20.112 74.819 20.232 75.443 ;
     RECT  33.216 73.477 33.24 75.491 ;
     RECT  15.984 74.147 16.008 75.683 ;
     RECT  7.8 75.299 9.096 75.827 ;
     RECT  10.752 75.205 10.776 75.827 ;
     RECT  52.8 69.395 52.824 76.309 ;
     RECT  45.312 70.019 45.912 76.357 ;
     RECT  31.728 74.581 31.752 76.499 ;
     RECT  27.648 75.781 27.672 76.739 ;
     RECT  29.4 74.147 30.552 76.885 ;
     RECT  49.248 72.419 49.272 76.885 ;
     RECT  50.88 74.053 51.312 76.885 ;
     RECT  65.664 68.915 65.688 76.885 ;
     RECT  5.52 76.885 5.544 76.933 ;
     RECT  20.208 75.443 20.232 76.979 ;
     RECT  15.936 76.885 15.96 77.315 ;
     RECT  71.424 76.357 71.448 77.315 ;
     RECT  7.8 75.827 8.112 77.365 ;
     RECT  10.224 76.885 10.248 77.555 ;
     RECT  49.248 76.885 51.312 77.555 ;
     RECT  65.376 76.885 65.688 77.555 ;
     RECT  14.784 76.885 14.808 78.083 ;
     RECT  52.8 76.309 53.496 78.083 ;
     RECT  69.504 75.109 69.528 78.083 ;
     RECT  4.56 76.933 5.544 78.131 ;
     RECT  26.736 77.461 26.76 78.131 ;
     RECT  54.72 76.309 54.744 78.371 ;
     RECT  25.488 75.395 25.512 78.419 ;
     RECT  45.312 76.357 46.152 78.517 ;
     RECT  7.8 77.365 8.232 78.613 ;
     RECT  12.288 73.571 13.512 78.613 ;
     RECT  67.2 73.523 67.512 78.613 ;
     RECT  5.52 78.131 5.544 78.659 ;
     RECT  22.752 78.037 22.776 78.659 ;
     RECT  11.664 78.613 13.512 78.707 ;
     RECT  28.464 76.885 30.552 78.709 ;
     RECT  69.552 78.613 69.576 78.755 ;
     RECT  28.464 78.709 30.888 79.043 ;
     RECT  7.296 78.613 8.232 79.093 ;
     RECT  45.312 78.517 46.248 79.189 ;
     RECT  11.664 78.707 11.688 79.283 ;
     RECT  32.688 77.413 32.712 79.283 ;
     RECT  64.368 76.885 64.392 79.283 ;
     RECT  20.496 78.085 20.52 79.475 ;
     RECT  18.48 71.075 18.912 79.477 ;
     RECT  39.792 73.763 40.512 79.669 ;
     RECT  7.248 79.093 8.232 79.717 ;
     RECT  49.248 77.555 49.272 79.717 ;
     RECT  50.736 77.555 51.312 79.717 ;
     RECT  70.608 79.189 70.632 79.717 ;
     RECT  52.8 78.083 52.824 79.765 ;
     RECT  56.4 74.723 59.496 79.765 ;
     RECT  27.216 79.669 27.24 79.811 ;
     RECT  44.448 79.189 46.248 79.859 ;
     RECT  36.576 73.571 37.128 79.861 ;
     RECT  24 74.723 24.312 79.909 ;
     RECT  43.104 78.661 43.128 79.955 ;
     RECT  70.128 79.717 70.632 79.955 ;
     RECT  29.04 79.043 30.888 80.003 ;
     RECT  24 79.909 25.08 80.099 ;
     RECT  5.184 79.141 5.208 80.147 ;
     RECT  7.248 79.717 8.952 80.435 ;
     RECT  33.024 79.573 33.048 80.435 ;
     RECT  39.36 79.669 40.512 80.531 ;
     RECT  60.576 78.613 60.6 80.531 ;
     RECT  49.248 79.717 51.312 80.675 ;
     RECT  52.464 79.765 52.824 80.675 ;
     RECT  61.8 74.051 62.112 80.821 ;
     RECT  67.2 78.613 68.088 80.915 ;
     RECT  14.832 79.765 14.856 80.963 ;
     RECT  49.248 80.675 49.704 80.963 ;
     RECT  70.128 79.955 70.152 80.963 ;
     RECT  55.296 80.533 55.32 81.011 ;
     RECT  18.48 79.477 19.464 81.059 ;
     RECT  24 80.099 24.312 81.205 ;
     RECT  34.8 73.811 35.112 81.205 ;
     RECT  56.304 79.765 59.496 81.205 ;
     RECT  47.76 72.131 47.784 81.253 ;
     RECT  49.248 80.963 49.272 81.253 ;
     RECT  47.76 81.253 49.272 81.539 ;
     RECT  61.008 80.821 62.112 81.587 ;
     RECT  26.928 80.917 26.952 81.875 ;
     RECT  39.792 80.531 40.512 82.021 ;
     RECT  23.52 81.205 24.312 82.115 ;
     RECT  34.176 81.205 35.112 82.115 ;
     RECT  16.704 77.701 16.728 82.165 ;
     RECT  13.104 78.707 13.512 82.453 ;
     RECT  42.72 80.341 42.744 82.453 ;
     RECT  34.8 82.115 35.112 82.501 ;
     RECT  7.8 80.435 8.52 82.597 ;
     RECT  50.736 80.675 51.312 82.597 ;
     RECT  16.56 82.165 16.728 82.645 ;
     RECT  29.4 80.003 30.888 82.645 ;
     RECT  32.352 81.973 32.376 82.645 ;
     RECT  16.512 82.645 16.728 82.691 ;
     RECT  56.304 81.205 59.784 82.691 ;
     RECT  7.632 82.597 8.52 82.931 ;
     RECT  47.76 81.539 48.408 82.979 ;
     RECT  54.24 81.445 54.264 82.979 ;
     RECT  6.288 81.445 6.312 83.027 ;
     RECT  7.632 82.931 8.112 83.075 ;
     RECT  45.312 79.859 46.248 83.173 ;
     RECT  47.76 82.979 47.784 83.173 ;
     RECT  29.4 82.645 32.376 83.267 ;
     RECT  34.8 82.501 35.256 83.267 ;
     RECT  39.792 82.021 41.064 83.267 ;
     RECT  29.4 83.267 31.56 83.315 ;
     RECT  42.72 82.453 43.128 83.315 ;
     RECT  12.912 82.453 13.512 83.363 ;
     RECT  27.6 82.885 27.624 83.507 ;
     RECT  34.8 83.267 35.112 83.653 ;
     RECT  16.512 82.691 16.584 83.749 ;
     RECT  36.576 79.861 37.224 83.843 ;
     RECT  56.304 82.691 59.496 83.843 ;
     RECT  40.2 83.267 41.064 83.845 ;
     RECT  42.72 83.315 42.744 83.845 ;
     RECT  40.2 83.845 42.744 84.035 ;
     RECT  49.968 82.597 51.312 84.035 ;
     RECT  50.736 84.035 51.312 84.083 ;
     RECT  37.104 83.843 37.224 84.179 ;
     RECT  56.4 83.843 59.496 84.181 ;
     RECT  18.48 81.059 18.912 84.227 ;
     RECT  30.864 83.315 31.56 84.275 ;
     RECT  13.2 83.363 13.512 84.325 ;
     RECT  33.888 83.653 35.112 84.371 ;
     RECT  39.024 83.749 39.048 84.371 ;
     RECT  52.8 80.675 52.824 84.373 ;
     RECT  11.424 83.509 11.448 84.419 ;
     RECT  56.4 84.181 59.544 84.419 ;
     RECT  65.376 77.555 65.4 84.611 ;
     RECT  45.312 83.173 47.784 84.757 ;
     RECT  40.2 84.035 42.6 84.805 ;
     RECT  16.512 83.749 16.68 84.995 ;
     RECT  25.632 84.277 25.656 84.995 ;
     RECT  45.024 84.757 47.784 84.995 ;
     RECT  58.08 84.419 59.544 84.995 ;
     RECT  13.2 84.325 13.608 85.091 ;
     RECT  43.776 84.901 43.8 85.093 ;
     RECT  45.024 84.995 46.92 85.093 ;
     RECT  29.4 83.315 29.88 85.235 ;
     RECT  43.776 85.093 46.92 85.235 ;
     RECT  39.504 84.805 42.6 85.285 ;
     RECT  43.776 85.235 43.8 85.285 ;
     RECT  52.8 84.373 53.016 85.379 ;
     RECT  49.296 84.229 49.32 85.477 ;
     RECT  16.512 84.995 16.536 85.523 ;
     RECT  59.52 84.995 59.544 85.523 ;
     RECT  64.128 83.749 64.152 85.523 ;
     RECT  39.504 85.285 43.8 85.667 ;
     RECT  48.912 85.477 49.32 85.717 ;
     RECT  22.608 84.901 22.632 85.811 ;
     RECT  31.536 84.275 31.56 85.955 ;
     RECT  44.928 85.235 46.92 86.053 ;
     RECT  48.432 85.717 49.32 86.053 ;
     RECT  20.736 81.781 20.76 86.099 ;
     RECT  52.8 85.379 52.824 86.099 ;
     RECT  58.08 84.995 58.104 86.099 ;
     RECT  39.504 85.667 43.272 86.341 ;
     RECT  2.4 75.395 2.712 86.409 ;
     RECT  7.8 83.075 8.112 86.409 ;
     RECT  13.2 85.091 13.512 86.409 ;
     RECT  18.6 84.227 18.912 86.409 ;
     RECT  24 82.115 24.312 86.409 ;
     RECT  29.4 85.235 29.712 86.409 ;
     RECT  34.8 84.371 35.112 86.409 ;
     RECT  51 84.083 51.312 86.409 ;
     RECT  56.4 84.419 56.712 86.409 ;
     RECT  61.8 81.587 62.112 86.409 ;
     RECT  67.2 80.915 67.512 86.409 ;
     RECT  72.6 74.003 72.912 86.409 ;
     RECT  78 68.435 78.312 86.409 ;
     RECT  83.4 2.151 83.712 86.409 ;
     RECT  2.4 86.409 2.52 86.423 ;
     RECT  7.8 86.409 7.92 86.423 ;
     RECT  13.2 86.409 13.32 86.423 ;
     RECT  18.6 86.409 18.72 86.423 ;
     RECT  24 86.409 24.12 86.423 ;
     RECT  29.4 86.409 29.52 86.423 ;
     RECT  34.8 86.409 34.92 86.423 ;
     RECT  51 86.409 51.12 86.423 ;
     RECT  56.4 86.409 56.52 86.423 ;
     RECT  61.8 86.409 61.92 86.423 ;
     RECT  67.2 86.409 67.32 86.423 ;
     RECT  72.6 86.409 72.72 86.423 ;
     RECT  78 86.409 78.12 86.423 ;
     RECT  83.4 86.409 83.52 86.423 ;
     RECT  44.928 86.053 49.32 86.629 ;
     RECT  44.88 86.629 49.32 87.157 ;
     RECT  37.104 84.179 37.128 87.205 ;
     RECT  38.16 86.629 38.184 87.205 ;
     RECT  39.216 86.341 43.272 87.205 ;
     RECT  44.88 87.157 49.416 87.205 ;
     RECT  37.104 87.205 49.416 88.528 ;
  END
END ot_dsrom_window_column_128
END LIBRARY
